VERSION 5.8 ;
BUSBITCHARS "[]" ;
DIVIDERCHAR "/" ;
UNITS
    DATABASE MICRONS 1000 ;
END UNITS

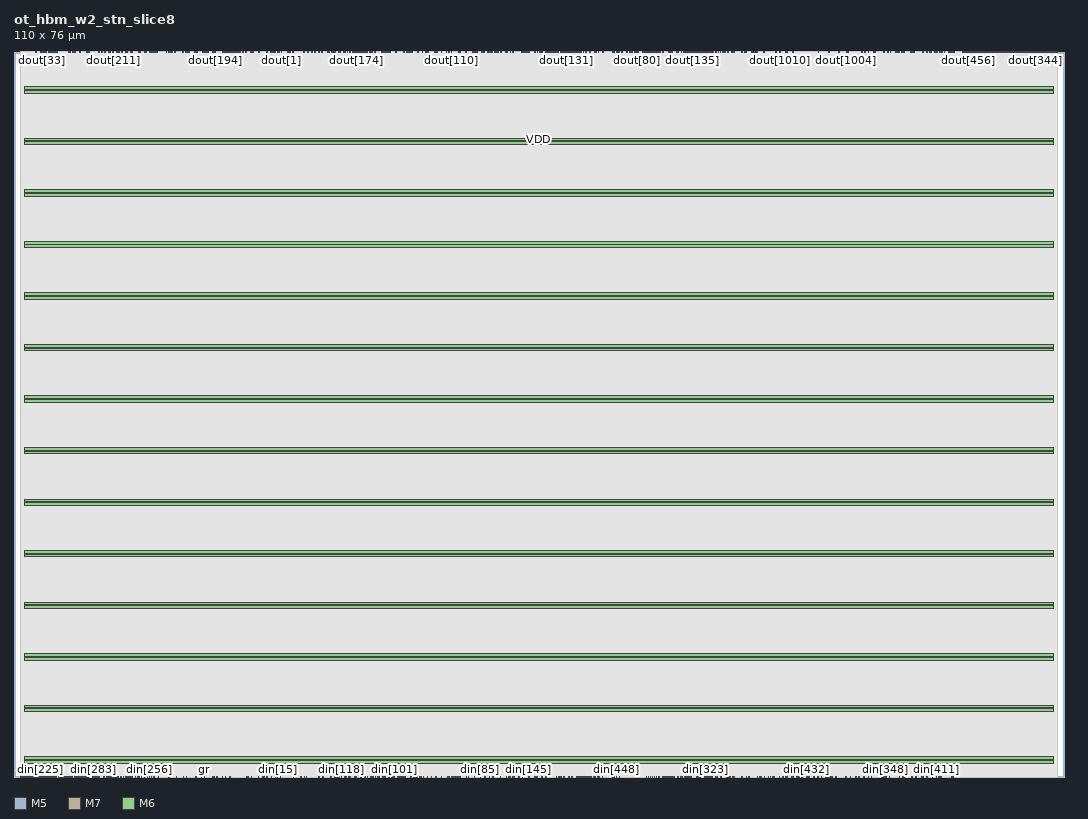
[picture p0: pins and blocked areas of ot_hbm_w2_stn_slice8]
MACRO ot_hbm_w2_stn_slice8
  FOREIGN ot_hbm_w2_stn_slice8 0 0 ;
  CLASS BLOCK ;
  SIZE 110 BY 76 ;
  PIN clk
    DIRECTION INPUT ;
    USE SIGNAL ;
    PORT
      LAYER M5 ;
        RECT  3.36 0 3.384 0.084 ;
    END
  END clk
  PIN din[0]
    DIRECTION INPUT ;
    USE SIGNAL ;
    PORT
      LAYER M5 ;
        RECT  13.68 0 13.704 0.084 ;
    END
  END din[0]
  PIN din[100]
    DIRECTION INPUT ;
    USE SIGNAL ;
    PORT
      LAYER M5 ;
        RECT  41.856 0 41.88 0.084 ;
    END
  END din[100]
  PIN din[101]
    DIRECTION INPUT ;
    USE SIGNAL ;
    PORT
      LAYER M5 ;
        RECT  39.84 0 39.864 0.084 ;
    END
  END din[101]
  PIN din[102]
    DIRECTION INPUT ;
    USE SIGNAL ;
    PORT
      LAYER M5 ;
        RECT  40.224 0 40.248 0.084 ;
    END
  END din[102]
  PIN din[103]
    DIRECTION INPUT ;
    USE SIGNAL ;
    PORT
      LAYER M5 ;
        RECT  38.592 0 38.616 0.084 ;
    END
  END din[103]
  PIN din[104]
    DIRECTION INPUT ;
    USE SIGNAL ;
    PORT
      LAYER M5 ;
        RECT  39.648 0 39.672 0.084 ;
    END
  END din[104]
  PIN din[105]
    DIRECTION INPUT ;
    USE SIGNAL ;
    PORT
      LAYER M5 ;
        RECT  38.832 0 38.856 0.084 ;
    END
  END din[105]
  PIN din[106]
    DIRECTION INPUT ;
    USE SIGNAL ;
    PORT
      LAYER M5 ;
        RECT  38.928 0 38.952 0.084 ;
    END
  END din[106]
  PIN din[107]
    DIRECTION INPUT ;
    USE SIGNAL ;
    PORT
      LAYER M5 ;
        RECT  35.808 0 35.832 0.084 ;
    END
  END din[107]
  PIN din[108]
    DIRECTION INPUT ;
    USE SIGNAL ;
    PORT
      LAYER M5 ;
        RECT  38.304 0 38.328 0.084 ;
    END
  END din[108]
  PIN din[109]
    DIRECTION INPUT ;
    USE SIGNAL ;
    PORT
      LAYER M5 ;
        RECT  35.904 0 35.928 0.084 ;
    END
  END din[109]
  PIN din[10]
    DIRECTION INPUT ;
    USE SIGNAL ;
    PORT
      LAYER M7 ;
        RECT  20.8 0 20.832 0.069 ;
    END
  END din[10]
  PIN din[110]
    DIRECTION INPUT ;
    USE SIGNAL ;
    PORT
      LAYER M5 ;
        RECT  38.88 0 38.904 0.084 ;
    END
  END din[110]
  PIN din[111]
    DIRECTION INPUT ;
    USE SIGNAL ;
    PORT
      LAYER M5 ;
        RECT  35.712 0 35.736 0.084 ;
    END
  END din[111]
  PIN din[112]
    DIRECTION INPUT ;
    USE SIGNAL ;
    PORT
      LAYER M5 ;
        RECT  35.856 0 35.88 0.084 ;
    END
  END din[112]
  PIN din[113]
    DIRECTION INPUT ;
    USE SIGNAL ;
    PORT
      LAYER M5 ;
        RECT  37.632 0 37.656 0.084 ;
    END
  END din[113]
  PIN din[114]
    DIRECTION INPUT ;
    USE SIGNAL ;
    PORT
      LAYER M5 ;
        RECT  35.232 0 35.256 0.084 ;
    END
  END din[114]
  PIN din[115]
    DIRECTION INPUT ;
    USE SIGNAL ;
    PORT
      LAYER M5 ;
        RECT  38.064 0 38.088 0.084 ;
    END
  END din[115]
  PIN din[116]
    DIRECTION INPUT ;
    USE SIGNAL ;
    PORT
      LAYER M7 ;
        RECT  33.536 0 33.568 0.069 ;
    END
  END din[116]
  PIN din[117]
    DIRECTION INPUT ;
    USE SIGNAL ;
    PORT
      LAYER M7 ;
        RECT  33.152 0 33.184 0.069 ;
    END
  END din[117]
  PIN din[118]
    DIRECTION INPUT ;
    USE SIGNAL ;
    PORT
      LAYER M5 ;
        RECT  34.272 0 34.296 0.084 ;
    END
  END din[118]
  PIN din[119]
    DIRECTION INPUT ;
    USE SIGNAL ;
    PORT
      LAYER M7 ;
        RECT  33.216 0 33.248 0.069 ;
    END
  END din[119]
  PIN din[11]
    DIRECTION INPUT ;
    USE SIGNAL ;
    PORT
      LAYER M5 ;
        RECT  17.04 0 17.064 0.084 ;
    END
  END din[11]
  PIN din[120]
    DIRECTION INPUT ;
    USE SIGNAL ;
    PORT
      LAYER M5 ;
        RECT  35.04 0 35.064 0.084 ;
    END
  END din[120]
  PIN din[121]
    DIRECTION INPUT ;
    USE SIGNAL ;
    PORT
      LAYER M5 ;
        RECT  37.008 0 37.032 0.084 ;
    END
  END din[121]
  PIN din[122]
    DIRECTION INPUT ;
    USE SIGNAL ;
    PORT
      LAYER M5 ;
        RECT  36.816 0 36.84 0.084 ;
    END
  END din[122]
  PIN din[123]
    DIRECTION INPUT ;
    USE SIGNAL ;
    PORT
      LAYER M5 ;
        RECT  36.768 0 36.792 0.084 ;
    END
  END din[123]
  PIN din[124]
    DIRECTION INPUT ;
    USE SIGNAL ;
    PORT
      LAYER M7 ;
        RECT  33.6 0 33.632 0.069 ;
    END
  END din[124]
  PIN din[125]
    DIRECTION INPUT ;
    USE SIGNAL ;
    PORT
      LAYER M5 ;
        RECT  34.656 0 34.68 0.084 ;
    END
  END din[125]
  PIN din[126]
    DIRECTION INPUT ;
    USE SIGNAL ;
    PORT
      LAYER M5 ;
        RECT  33.744 0 33.768 0.084 ;
    END
  END din[126]
  PIN din[127]
    DIRECTION INPUT ;
    USE SIGNAL ;
    PORT
      LAYER M5 ;
        RECT  35.088 0 35.112 0.084 ;
    END
  END din[127]
  PIN din[128]
    DIRECTION INPUT ;
    USE SIGNAL ;
    PORT
      LAYER M5 ;
        RECT  39.504 0 39.528 0.084 ;
    END
  END din[128]
  PIN din[129]
    DIRECTION INPUT ;
    USE SIGNAL ;
    PORT
      LAYER M7 ;
        RECT  56.832 0 56.864 0.069 ;
    END
  END din[129]
  PIN din[12]
    DIRECTION INPUT ;
    USE SIGNAL ;
    PORT
      LAYER M5 ;
        RECT  24.528 0 24.552 0.084 ;
    END
  END din[12]
  PIN din[130]
    DIRECTION INPUT ;
    USE SIGNAL ;
    PORT
      LAYER M5 ;
        RECT  41.904 0 41.928 0.084 ;
    END
  END din[130]
  PIN din[131]
    DIRECTION INPUT ;
    USE SIGNAL ;
    PORT
      LAYER M5 ;
        RECT  52.176 0 52.2 0.084 ;
    END
  END din[131]
  PIN din[132]
    DIRECTION INPUT ;
    USE SIGNAL ;
    PORT
      LAYER M5 ;
        RECT  55.296 0 55.32 0.084 ;
    END
  END din[132]
  PIN din[133]
    DIRECTION INPUT ;
    USE SIGNAL ;
    PORT
      LAYER M5 ;
        RECT  54.864 0 54.888 0.084 ;
    END
  END din[133]
  PIN din[134]
    DIRECTION INPUT ;
    USE SIGNAL ;
    PORT
      LAYER M5 ;
        RECT  53.28 0 53.304 0.084 ;
    END
  END din[134]
  PIN din[135]
    DIRECTION INPUT ;
    USE SIGNAL ;
    PORT
      LAYER M7 ;
        RECT  57.216 0 57.248 0.069 ;
    END
  END din[135]
  PIN din[136]
    DIRECTION INPUT ;
    USE SIGNAL ;
    PORT
      LAYER M7 ;
        RECT  57.344 0 57.376 0.069 ;
    END
  END din[136]
  PIN din[137]
    DIRECTION INPUT ;
    USE SIGNAL ;
    PORT
      LAYER M5 ;
        RECT  40.56 0 40.584 0.084 ;
    END
  END din[137]
  PIN din[138]
    DIRECTION INPUT ;
    USE SIGNAL ;
    PORT
      LAYER M7 ;
        RECT  57.6 0 57.632 0.069 ;
    END
  END din[138]
  PIN din[139]
    DIRECTION INPUT ;
    USE SIGNAL ;
    PORT
      LAYER M5 ;
        RECT  42.192 0 42.216 0.084 ;
    END
  END din[139]
  PIN din[13]
    DIRECTION INPUT ;
    USE SIGNAL ;
    PORT
      LAYER M7 ;
        RECT  17.728 0 17.76 0.069 ;
    END
  END din[13]
  PIN din[140]
    DIRECTION INPUT ;
    USE SIGNAL ;
    PORT
      LAYER M5 ;
        RECT  44.208 0 44.232 0.084 ;
    END
  END din[140]
  PIN din[141]
    DIRECTION INPUT ;
    USE SIGNAL ;
    PORT
      LAYER M5 ;
        RECT  51.792 0 51.816 0.084 ;
    END
  END din[141]
  PIN din[142]
    DIRECTION INPUT ;
    USE SIGNAL ;
    PORT
      LAYER M7 ;
        RECT  60.032 0 60.064 0.069 ;
    END
  END din[142]
  PIN din[143]
    DIRECTION INPUT ;
    USE SIGNAL ;
    PORT
      LAYER M7 ;
        RECT  59.968 0 60 0.069 ;
    END
  END din[143]
  PIN din[144]
    DIRECTION INPUT ;
    USE SIGNAL ;
    PORT
      LAYER M5 ;
        RECT  43.728 0 43.752 0.084 ;
    END
  END din[144]
  PIN din[145]
    DIRECTION INPUT ;
    USE SIGNAL ;
    PORT
      LAYER M5 ;
        RECT  53.904 0 53.928 0.084 ;
    END
  END din[145]
  PIN din[146]
    DIRECTION INPUT ;
    USE SIGNAL ;
    PORT
      LAYER M7 ;
        RECT  60.224 0 60.256 0.069 ;
    END
  END din[146]
  PIN din[147]
    DIRECTION INPUT ;
    USE SIGNAL ;
    PORT
      LAYER M7 ;
        RECT  57.536 0 57.568 0.069 ;
    END
  END din[147]
  PIN din[148]
    DIRECTION INPUT ;
    USE SIGNAL ;
    PORT
      LAYER M5 ;
        RECT  55.728 0 55.752 0.084 ;
    END
  END din[148]
  PIN din[149]
    DIRECTION INPUT ;
    USE SIGNAL ;
    PORT
      LAYER M7 ;
        RECT  58.112 0 58.144 0.069 ;
    END
  END din[149]
  PIN din[14]
    DIRECTION INPUT ;
    USE SIGNAL ;
    PORT
      LAYER M5 ;
        RECT  27.36 0 27.384 0.084 ;
    END
  END din[14]
  PIN din[150]
    DIRECTION INPUT ;
    USE SIGNAL ;
    PORT
      LAYER M7 ;
        RECT  49.408 0 49.44 0.069 ;
    END
  END din[150]
  PIN din[151]
    DIRECTION INPUT ;
    USE SIGNAL ;
    PORT
      LAYER M5 ;
        RECT  40.656 0 40.68 0.084 ;
    END
  END din[151]
  PIN din[152]
    DIRECTION INPUT ;
    USE SIGNAL ;
    PORT
      LAYER M7 ;
        RECT  46.72 0 46.752 0.069 ;
    END
  END din[152]
  PIN din[153]
    DIRECTION INPUT ;
    USE SIGNAL ;
    PORT
      LAYER M7 ;
        RECT  49.28 0 49.312 0.069 ;
    END
  END din[153]
  PIN din[154]
    DIRECTION INPUT ;
    USE SIGNAL ;
    PORT
      LAYER M7 ;
        RECT  45.44 0 45.472 0.069 ;
    END
  END din[154]
  PIN din[155]
    DIRECTION INPUT ;
    USE SIGNAL ;
    PORT
      LAYER M7 ;
        RECT  45.568 0 45.6 0.069 ;
    END
  END din[155]
  PIN din[156]
    DIRECTION INPUT ;
    USE SIGNAL ;
    PORT
      LAYER M5 ;
        RECT  42.672 0 42.696 0.084 ;
    END
  END din[156]
  PIN din[157]
    DIRECTION INPUT ;
    USE SIGNAL ;
    PORT
      LAYER M7 ;
        RECT  45.888 0 45.92 0.069 ;
    END
  END din[157]
  PIN din[158]
    DIRECTION INPUT ;
    USE SIGNAL ;
    PORT
      LAYER M5 ;
        RECT  39.216 0 39.24 0.084 ;
    END
  END din[158]
  PIN din[159]
    DIRECTION INPUT ;
    USE SIGNAL ;
    PORT
      LAYER M7 ;
        RECT  46.144 0 46.176 0.069 ;
    END
  END din[159]
  PIN din[15]
    DIRECTION INPUT ;
    USE SIGNAL ;
    PORT
      LAYER M5 ;
        RECT  27.6 0 27.624 0.084 ;
    END
  END din[15]
  PIN din[160]
    DIRECTION INPUT ;
    USE SIGNAL ;
    PORT
      LAYER M7 ;
        RECT  46.656 0 46.688 0.069 ;
    END
  END din[160]
  PIN din[161]
    DIRECTION INPUT ;
    USE SIGNAL ;
    PORT
      LAYER M7 ;
        RECT  45.824 0 45.856 0.069 ;
    END
  END din[161]
  PIN din[162]
    DIRECTION INPUT ;
    USE SIGNAL ;
    PORT
      LAYER M5 ;
        RECT  38.688 0 38.712 0.084 ;
    END
  END din[162]
  PIN din[163]
    DIRECTION INPUT ;
    USE SIGNAL ;
    PORT
      LAYER M5 ;
        RECT  40.848 0 40.872 0.084 ;
    END
  END din[163]
  PIN din[164]
    DIRECTION INPUT ;
    USE SIGNAL ;
    PORT
      LAYER M5 ;
        RECT  42.144 0 42.168 0.084 ;
    END
  END din[164]
  PIN din[165]
    DIRECTION INPUT ;
    USE SIGNAL ;
    PORT
      LAYER M5 ;
        RECT  40.128 0 40.152 0.084 ;
    END
  END din[165]
  PIN din[166]
    DIRECTION INPUT ;
    USE SIGNAL ;
    PORT
      LAYER M7 ;
        RECT  44.8 0 44.832 0.069 ;
    END
  END din[166]
  PIN din[167]
    DIRECTION INPUT ;
    USE SIGNAL ;
    PORT
      LAYER M5 ;
        RECT  44.16 0 44.184 0.084 ;
    END
  END din[167]
  PIN din[168]
    DIRECTION INPUT ;
    USE SIGNAL ;
    PORT
      LAYER M5 ;
        RECT  42.864 0 42.888 0.084 ;
    END
  END din[168]
  PIN din[169]
    DIRECTION INPUT ;
    USE SIGNAL ;
    PORT
      LAYER M5 ;
        RECT  42.528 0 42.552 0.084 ;
    END
  END din[169]
  PIN din[16]
    DIRECTION INPUT ;
    USE SIGNAL ;
    PORT
      LAYER M5 ;
        RECT  24.432 0 24.456 0.084 ;
    END
  END din[16]
  PIN din[170]
    DIRECTION INPUT ;
    USE SIGNAL ;
    PORT
      LAYER M5 ;
        RECT  42.24 0 42.264 0.084 ;
    END
  END din[170]
  PIN din[171]
    DIRECTION INPUT ;
    USE SIGNAL ;
    PORT
      LAYER M5 ;
        RECT  42.048 0 42.072 0.084 ;
    END
  END din[171]
  PIN din[172]
    DIRECTION INPUT ;
    USE SIGNAL ;
    PORT
      LAYER M5 ;
        RECT  41.952 0 41.976 0.084 ;
    END
  END din[172]
  PIN din[173]
    DIRECTION INPUT ;
    USE SIGNAL ;
    PORT
      LAYER M5 ;
        RECT  40.704 0 40.728 0.084 ;
    END
  END din[173]
  PIN din[174]
    DIRECTION INPUT ;
    USE SIGNAL ;
    PORT
      LAYER M5 ;
        RECT  41.04 0 41.064 0.084 ;
    END
  END din[174]
  PIN din[175]
    DIRECTION INPUT ;
    USE SIGNAL ;
    PORT
      LAYER M5 ;
        RECT  40.608 0 40.632 0.084 ;
    END
  END din[175]
  PIN din[176]
    DIRECTION INPUT ;
    USE SIGNAL ;
    PORT
      LAYER M5 ;
        RECT  39.888 0 39.912 0.084 ;
    END
  END din[176]
  PIN din[177]
    DIRECTION INPUT ;
    USE SIGNAL ;
    PORT
      LAYER M5 ;
        RECT  38.784 0 38.808 0.084 ;
    END
  END din[177]
  PIN din[178]
    DIRECTION INPUT ;
    USE SIGNAL ;
    PORT
      LAYER M5 ;
        RECT  38.64 0 38.664 0.084 ;
    END
  END din[178]
  PIN din[179]
    DIRECTION INPUT ;
    USE SIGNAL ;
    PORT
      LAYER M5 ;
        RECT  39.312 0 39.336 0.084 ;
    END
  END din[179]
  PIN din[17]
    DIRECTION INPUT ;
    USE SIGNAL ;
    PORT
      LAYER M5 ;
        RECT  26.064 0 26.088 0.084 ;
    END
  END din[17]
  PIN din[180]
    DIRECTION INPUT ;
    USE SIGNAL ;
    PORT
      LAYER M5 ;
        RECT  36.72 0 36.744 0.084 ;
    END
  END din[180]
  PIN din[181]
    DIRECTION INPUT ;
    USE SIGNAL ;
    PORT
      LAYER M5 ;
        RECT  37.344 0 37.368 0.084 ;
    END
  END din[181]
  PIN din[182]
    DIRECTION INPUT ;
    USE SIGNAL ;
    PORT
      LAYER M5 ;
        RECT  37.392 0 37.416 0.084 ;
    END
  END din[182]
  PIN din[183]
    DIRECTION INPUT ;
    USE SIGNAL ;
    PORT
      LAYER M5 ;
        RECT  39.696 0 39.72 0.084 ;
    END
  END din[183]
  PIN din[184]
    DIRECTION INPUT ;
    USE SIGNAL ;
    PORT
      LAYER M5 ;
        RECT  36.384 0 36.408 0.084 ;
    END
  END din[184]
  PIN din[185]
    DIRECTION INPUT ;
    USE SIGNAL ;
    PORT
      LAYER M5 ;
        RECT  35.136 0 35.16 0.084 ;
    END
  END din[185]
  PIN din[186]
    DIRECTION INPUT ;
    USE SIGNAL ;
    PORT
      LAYER M5 ;
        RECT  34.752 0 34.776 0.084 ;
    END
  END din[186]
  PIN din[187]
    DIRECTION INPUT ;
    USE SIGNAL ;
    PORT
      LAYER M5 ;
        RECT  34.848 0 34.872 0.084 ;
    END
  END din[187]
  PIN din[188]
    DIRECTION INPUT ;
    USE SIGNAL ;
    PORT
      LAYER M5 ;
        RECT  35.664 0 35.688 0.084 ;
    END
  END din[188]
  PIN din[189]
    DIRECTION INPUT ;
    USE SIGNAL ;
    PORT
      LAYER M5 ;
        RECT  35.28 0 35.304 0.084 ;
    END
  END din[189]
  PIN din[18]
    DIRECTION INPUT ;
    USE SIGNAL ;
    PORT
      LAYER M7 ;
        RECT  29.248 0 29.28 0.069 ;
    END
  END din[18]
  PIN din[190]
    DIRECTION INPUT ;
    USE SIGNAL ;
    PORT
      LAYER M5 ;
        RECT  36.672 0 36.696 0.084 ;
    END
  END din[190]
  PIN din[191]
    DIRECTION INPUT ;
    USE SIGNAL ;
    PORT
      LAYER M5 ;
        RECT  36.288 0 36.312 0.084 ;
    END
  END din[191]
  PIN din[192]
    DIRECTION INPUT ;
    USE SIGNAL ;
    PORT
      LAYER M5 ;
        RECT  5.424 0 5.448 0.084 ;
    END
  END din[192]
  PIN din[193]
    DIRECTION INPUT ;
    USE SIGNAL ;
    PORT
      LAYER M5 ;
        RECT  3.312 0 3.336 0.084 ;
    END
  END din[193]
  PIN din[194]
    DIRECTION INPUT ;
    USE SIGNAL ;
    PORT
      LAYER M5 ;
        RECT  3.552 0 3.576 0.084 ;
    END
  END din[194]
  PIN din[195]
    DIRECTION INPUT ;
    USE SIGNAL ;
    PORT
      LAYER M5 ;
        RECT  3.024 0 3.048 0.084 ;
    END
  END din[195]
  PIN din[196]
    DIRECTION INPUT ;
    USE SIGNAL ;
    PORT
      LAYER M5 ;
        RECT  0.72 0 0.744 0.084 ;
    END
  END din[196]
  PIN din[197]
    DIRECTION INPUT ;
    USE SIGNAL ;
    PORT
      LAYER M5 ;
        RECT  0.864 0 0.888 0.084 ;
    END
  END din[197]
  PIN din[198]
    DIRECTION INPUT ;
    USE SIGNAL ;
    PORT
      LAYER M5 ;
        RECT  1.68 0 1.704 0.084 ;
    END
  END din[198]
  PIN din[199]
    DIRECTION INPUT ;
    USE SIGNAL ;
    PORT
      LAYER M5 ;
        RECT  4.8 0 4.824 0.084 ;
    END
  END din[199]
  PIN din[19]
    DIRECTION INPUT ;
    USE SIGNAL ;
    PORT
      LAYER M5 ;
        RECT  26.976 0 27 0.084 ;
    END
  END din[19]
  PIN din[1]
    DIRECTION INPUT ;
    USE SIGNAL ;
    PORT
      LAYER M7 ;
        RECT  18.048 0 18.08 0.069 ;
    END
  END din[1]
  PIN din[200]
    DIRECTION INPUT ;
    USE SIGNAL ;
    PORT
      LAYER M5 ;
        RECT  1.872 0 1.896 0.084 ;
    END
  END din[200]
  PIN din[201]
    DIRECTION INPUT ;
    USE SIGNAL ;
    PORT
      LAYER M5 ;
        RECT  2.304 0 2.328 0.084 ;
    END
  END din[201]
  PIN din[202]
    DIRECTION INPUT ;
    USE SIGNAL ;
    PORT
      LAYER M5 ;
        RECT  0.768 0 0.792 0.084 ;
    END
  END din[202]
  PIN din[203]
    DIRECTION INPUT ;
    USE SIGNAL ;
    PORT
      LAYER M5 ;
        RECT  3.12 0 3.144 0.084 ;
    END
  END din[203]
  PIN din[204]
    DIRECTION INPUT ;
    USE SIGNAL ;
    PORT
      LAYER M5 ;
        RECT  2.832 0 2.856 0.084 ;
    END
  END din[204]
  PIN din[205]
    DIRECTION INPUT ;
    USE SIGNAL ;
    PORT
      LAYER M5 ;
        RECT  0.912 0 0.936 0.084 ;
    END
  END din[205]
  PIN din[206]
    DIRECTION INPUT ;
    USE SIGNAL ;
    PORT
      LAYER M5 ;
        RECT  2.064 0 2.088 0.084 ;
    END
  END din[206]
  PIN din[207]
    DIRECTION INPUT ;
    USE SIGNAL ;
    PORT
      LAYER M5 ;
        RECT  0.816 0 0.84 0.084 ;
    END
  END din[207]
  PIN din[208]
    DIRECTION INPUT ;
    USE SIGNAL ;
    PORT
      LAYER M5 ;
        RECT  1.776 0 1.8 0.084 ;
    END
  END din[208]
  PIN din[209]
    DIRECTION INPUT ;
    USE SIGNAL ;
    PORT
      LAYER M5 ;
        RECT  1.44 0 1.464 0.084 ;
    END
  END din[209]
  PIN din[20]
    DIRECTION INPUT ;
    USE SIGNAL ;
    PORT
      LAYER M5 ;
        RECT  25.632 0 25.656 0.084 ;
    END
  END din[20]
  PIN din[210]
    DIRECTION INPUT ;
    USE SIGNAL ;
    PORT
      LAYER M5 ;
        RECT  2.4 0 2.424 0.084 ;
    END
  END din[210]
  PIN din[211]
    DIRECTION INPUT ;
    USE SIGNAL ;
    PORT
      LAYER M5 ;
        RECT  2.448 0 2.472 0.084 ;
    END
  END din[211]
  PIN din[212]
    DIRECTION INPUT ;
    USE SIGNAL ;
    PORT
      LAYER M5 ;
        RECT  2.256 0 2.28 0.084 ;
    END
  END din[212]
  PIN din[213]
    DIRECTION INPUT ;
    USE SIGNAL ;
    PORT
      LAYER M5 ;
        RECT  1.392 0 1.416 0.084 ;
    END
  END din[213]
  PIN din[214]
    DIRECTION INPUT ;
    USE SIGNAL ;
    PORT
      LAYER M5 ;
        RECT  1.968 0 1.992 0.084 ;
    END
  END din[214]
  PIN din[215]
    DIRECTION INPUT ;
    USE SIGNAL ;
    PORT
      LAYER M5 ;
        RECT  0.96 0 0.984 0.084 ;
    END
  END din[215]
  PIN din[216]
    DIRECTION INPUT ;
    USE SIGNAL ;
    PORT
      LAYER M5 ;
        RECT  3.264 0 3.288 0.084 ;
    END
  END din[216]
  PIN din[217]
    DIRECTION INPUT ;
    USE SIGNAL ;
    PORT
      LAYER M5 ;
        RECT  1.536 0 1.56 0.084 ;
    END
  END din[217]
  PIN din[218]
    DIRECTION INPUT ;
    USE SIGNAL ;
    PORT
      LAYER M5 ;
        RECT  1.344 0 1.368 0.084 ;
    END
  END din[218]
  PIN din[219]
    DIRECTION INPUT ;
    USE SIGNAL ;
    PORT
      LAYER M5 ;
        RECT  1.632 0 1.656 0.084 ;
    END
  END din[219]
  PIN din[21]
    DIRECTION INPUT ;
    USE SIGNAL ;
    PORT
      LAYER M5 ;
        RECT  24.864 0 24.888 0.084 ;
    END
  END din[21]
  PIN din[220]
    DIRECTION INPUT ;
    USE SIGNAL ;
    PORT
      LAYER M5 ;
        RECT  1.296 0 1.32 0.084 ;
    END
  END din[220]
  PIN din[221]
    DIRECTION INPUT ;
    USE SIGNAL ;
    PORT
      LAYER M5 ;
        RECT  1.584 0 1.608 0.084 ;
    END
  END din[221]
  PIN din[222]
    DIRECTION INPUT ;
    USE SIGNAL ;
    PORT
      LAYER M5 ;
        RECT  1.248 0 1.272 0.084 ;
    END
  END din[222]
  PIN din[223]
    DIRECTION INPUT ;
    USE SIGNAL ;
    PORT
      LAYER M5 ;
        RECT  1.008 0 1.032 0.084 ;
    END
  END din[223]
  PIN din[224]
    DIRECTION INPUT ;
    USE SIGNAL ;
    PORT
      LAYER M5 ;
        RECT  1.824 0 1.848 0.084 ;
    END
  END din[224]
  PIN din[225]
    DIRECTION INPUT ;
    USE SIGNAL ;
    PORT
      LAYER M5 ;
        RECT  2.736 0 2.76 0.084 ;
    END
  END din[225]
  PIN din[226]
    DIRECTION INPUT ;
    USE SIGNAL ;
    PORT
      LAYER M5 ;
        RECT  1.2 0 1.224 0.084 ;
    END
  END din[226]
  PIN din[227]
    DIRECTION INPUT ;
    USE SIGNAL ;
    PORT
      LAYER M5 ;
        RECT  6.096 0 6.12 0.084 ;
    END
  END din[227]
  PIN din[228]
    DIRECTION INPUT ;
    USE SIGNAL ;
    PORT
      LAYER M5 ;
        RECT  6.144 0 6.168 0.084 ;
    END
  END din[228]
  PIN din[229]
    DIRECTION INPUT ;
    USE SIGNAL ;
    PORT
      LAYER M5 ;
        RECT  2.688 0 2.712 0.084 ;
    END
  END din[229]
  PIN din[22]
    DIRECTION INPUT ;
    USE SIGNAL ;
    PORT
      LAYER M5 ;
        RECT  26.256 0 26.28 0.084 ;
    END
  END din[22]
  PIN din[230]
    DIRECTION INPUT ;
    USE SIGNAL ;
    PORT
      LAYER M5 ;
        RECT  4.128 0 4.152 0.084 ;
    END
  END din[230]
  PIN din[231]
    DIRECTION INPUT ;
    USE SIGNAL ;
    PORT
      LAYER M5 ;
        RECT  4.992 0 5.016 0.084 ;
    END
  END din[231]
  PIN din[232]
    DIRECTION INPUT ;
    USE SIGNAL ;
    PORT
      LAYER M5 ;
        RECT  5.76 0 5.784 0.084 ;
    END
  END din[232]
  PIN din[233]
    DIRECTION INPUT ;
    USE SIGNAL ;
    PORT
      LAYER M5 ;
        RECT  2.544 0 2.568 0.084 ;
    END
  END din[233]
  PIN din[234]
    DIRECTION INPUT ;
    USE SIGNAL ;
    PORT
      LAYER M5 ;
        RECT  3.504 0 3.528 0.084 ;
    END
  END din[234]
  PIN din[235]
    DIRECTION INPUT ;
    USE SIGNAL ;
    PORT
      LAYER M5 ;
        RECT  4.752 0 4.776 0.084 ;
    END
  END din[235]
  PIN din[236]
    DIRECTION INPUT ;
    USE SIGNAL ;
    PORT
      LAYER M5 ;
        RECT  5.232 0 5.256 0.084 ;
    END
  END din[236]
  PIN din[237]
    DIRECTION INPUT ;
    USE SIGNAL ;
    PORT
      LAYER M5 ;
        RECT  2.208 0 2.232 0.084 ;
    END
  END din[237]
  PIN din[238]
    DIRECTION INPUT ;
    USE SIGNAL ;
    PORT
      LAYER M5 ;
        RECT  1.152 0 1.176 0.084 ;
    END
  END din[238]
  PIN din[239]
    DIRECTION INPUT ;
    USE SIGNAL ;
    PORT
      LAYER M5 ;
        RECT  2.112 0 2.136 0.084 ;
    END
  END din[239]
  PIN din[23]
    DIRECTION INPUT ;
    USE SIGNAL ;
    PORT
      LAYER M5 ;
        RECT  26.496 0 26.52 0.084 ;
    END
  END din[23]
  PIN din[240]
    DIRECTION INPUT ;
    USE SIGNAL ;
    PORT
      LAYER M5 ;
        RECT  2.496 0 2.52 0.084 ;
    END
  END din[240]
  PIN din[241]
    DIRECTION INPUT ;
    USE SIGNAL ;
    PORT
      LAYER M5 ;
        RECT  3.072 0 3.096 0.084 ;
    END
  END din[241]
  PIN din[242]
    DIRECTION INPUT ;
    USE SIGNAL ;
    PORT
      LAYER M5 ;
        RECT  1.104 0 1.128 0.084 ;
    END
  END din[242]
  PIN din[243]
    DIRECTION INPUT ;
    USE SIGNAL ;
    PORT
      LAYER M5 ;
        RECT  3.84 0 3.864 0.084 ;
    END
  END din[243]
  PIN din[244]
    DIRECTION INPUT ;
    USE SIGNAL ;
    PORT
      LAYER M5 ;
        RECT  3.216 0 3.24 0.084 ;
    END
  END din[244]
  PIN din[245]
    DIRECTION INPUT ;
    USE SIGNAL ;
    PORT
      LAYER M5 ;
        RECT  3.168 0 3.192 0.084 ;
    END
  END din[245]
  PIN din[246]
    DIRECTION INPUT ;
    USE SIGNAL ;
    PORT
      LAYER M5 ;
        RECT  3.696 0 3.72 0.084 ;
    END
  END din[246]
  PIN din[247]
    DIRECTION INPUT ;
    USE SIGNAL ;
    PORT
      LAYER M5 ;
        RECT  3.888 0 3.912 0.084 ;
    END
  END din[247]
  PIN din[248]
    DIRECTION INPUT ;
    USE SIGNAL ;
    PORT
      LAYER M5 ;
        RECT  3.456 0 3.48 0.084 ;
    END
  END din[248]
  PIN din[249]
    DIRECTION INPUT ;
    USE SIGNAL ;
    PORT
      LAYER M5 ;
        RECT  2.88 0 2.904 0.084 ;
    END
  END din[249]
  PIN din[24]
    DIRECTION INPUT ;
    USE SIGNAL ;
    PORT
      LAYER M5 ;
        RECT  24.384 0 24.408 0.084 ;
    END
  END din[24]
  PIN din[250]
    DIRECTION INPUT ;
    USE SIGNAL ;
    PORT
      LAYER M5 ;
        RECT  2.784 0 2.808 0.084 ;
    END
  END din[250]
  PIN din[251]
    DIRECTION INPUT ;
    USE SIGNAL ;
    PORT
      LAYER M5 ;
        RECT  1.728 0 1.752 0.084 ;
    END
  END din[251]
  PIN din[252]
    DIRECTION INPUT ;
    USE SIGNAL ;
    PORT
      LAYER M5 ;
        RECT  3.408 0 3.432 0.084 ;
    END
  END din[252]
  PIN din[253]
    DIRECTION INPUT ;
    USE SIGNAL ;
    PORT
      LAYER M5 ;
        RECT  2.64 0 2.664 0.084 ;
    END
  END din[253]
  PIN din[254]
    DIRECTION INPUT ;
    USE SIGNAL ;
    PORT
      LAYER M5 ;
        RECT  2.352 0 2.376 0.084 ;
    END
  END din[254]
  PIN din[255]
    DIRECTION INPUT ;
    USE SIGNAL ;
    PORT
      LAYER M5 ;
        RECT  1.056 0 1.08 0.084 ;
    END
  END din[255]
  PIN din[256]
    DIRECTION INPUT ;
    USE SIGNAL ;
    PORT
      LAYER M5 ;
        RECT  14.208 0 14.232 0.084 ;
    END
  END din[256]
  PIN din[257]
    DIRECTION INPUT ;
    USE SIGNAL ;
    PORT
      LAYER M5 ;
        RECT  12.72 0 12.744 0.084 ;
    END
  END din[257]
  PIN din[258]
    DIRECTION INPUT ;
    USE SIGNAL ;
    PORT
      LAYER M5 ;
        RECT  11.952 0 11.976 0.084 ;
    END
  END din[258]
  PIN din[259]
    DIRECTION INPUT ;
    USE SIGNAL ;
    PORT
      LAYER M5 ;
        RECT  14.64 0 14.664 0.084 ;
    END
  END din[259]
  PIN din[25]
    DIRECTION INPUT ;
    USE SIGNAL ;
    PORT
      LAYER M5 ;
        RECT  24.336 0 24.36 0.084 ;
    END
  END din[25]
  PIN din[260]
    DIRECTION INPUT ;
    USE SIGNAL ;
    PORT
      LAYER M7 ;
        RECT  6.592 0 6.624 0.069 ;
    END
  END din[260]
  PIN din[261]
    DIRECTION INPUT ;
    USE SIGNAL ;
    PORT
      LAYER M5 ;
        RECT  13.056 0 13.08 0.084 ;
    END
  END din[261]
  PIN din[262]
    DIRECTION INPUT ;
    USE SIGNAL ;
    PORT
      LAYER M5 ;
        RECT  13.968 0 13.992 0.084 ;
    END
  END din[262]
  PIN din[263]
    DIRECTION INPUT ;
    USE SIGNAL ;
    PORT
      LAYER M5 ;
        RECT  12.048 0 12.072 0.084 ;
    END
  END din[263]
  PIN din[264]
    DIRECTION INPUT ;
    USE SIGNAL ;
    PORT
      LAYER M5 ;
        RECT  11.808 0 11.832 0.084 ;
    END
  END din[264]
  PIN din[265]
    DIRECTION INPUT ;
    USE SIGNAL ;
    PORT
      LAYER M7 ;
        RECT  10.88 0 10.912 0.069 ;
    END
  END din[265]
  PIN din[266]
    DIRECTION INPUT ;
    USE SIGNAL ;
    PORT
      LAYER M5 ;
        RECT  14.736 0 14.76 0.084 ;
    END
  END din[266]
  PIN din[267]
    DIRECTION INPUT ;
    USE SIGNAL ;
    PORT
      LAYER M5 ;
        RECT  12.912 0 12.936 0.084 ;
    END
  END din[267]
  PIN din[268]
    DIRECTION INPUT ;
    USE SIGNAL ;
    PORT
      LAYER M7 ;
        RECT  9.664 0 9.696 0.069 ;
    END
  END din[268]
  PIN din[269]
    DIRECTION INPUT ;
    USE SIGNAL ;
    PORT
      LAYER M5 ;
        RECT  14.688 0 14.712 0.084 ;
    END
  END din[269]
  PIN din[26]
    DIRECTION INPUT ;
    USE SIGNAL ;
    PORT
      LAYER M7 ;
        RECT  22.144 0 22.176 0.069 ;
    END
  END din[26]
  PIN din[270]
    DIRECTION INPUT ;
    USE SIGNAL ;
    PORT
      LAYER M5 ;
        RECT  12.336 0 12.36 0.084 ;
    END
  END din[270]
  PIN din[271]
    DIRECTION INPUT ;
    USE SIGNAL ;
    PORT
      LAYER M5 ;
        RECT  12.384 0 12.408 0.084 ;
    END
  END din[271]
  PIN din[272]
    DIRECTION INPUT ;
    USE SIGNAL ;
    PORT
      LAYER M7 ;
        RECT  10.816 0 10.848 0.069 ;
    END
  END din[272]
  PIN din[273]
    DIRECTION INPUT ;
    USE SIGNAL ;
    PORT
      LAYER M5 ;
        RECT  11.664 0 11.688 0.084 ;
    END
  END din[273]
  PIN din[274]
    DIRECTION INPUT ;
    USE SIGNAL ;
    PORT
      LAYER M5 ;
        RECT  11.712 0 11.736 0.084 ;
    END
  END din[274]
  PIN din[275]
    DIRECTION INPUT ;
    USE SIGNAL ;
    PORT
      LAYER M5 ;
        RECT  13.104 0 13.128 0.084 ;
    END
  END din[275]
  PIN din[276]
    DIRECTION INPUT ;
    USE SIGNAL ;
    PORT
      LAYER M7 ;
        RECT  9.728 0 9.76 0.069 ;
    END
  END din[276]
  PIN din[277]
    DIRECTION INPUT ;
    USE SIGNAL ;
    PORT
      LAYER M5 ;
        RECT  13.344 0 13.368 0.084 ;
    END
  END din[277]
  PIN din[278]
    DIRECTION INPUT ;
    USE SIGNAL ;
    PORT
      LAYER M7 ;
        RECT  10.752 0 10.784 0.069 ;
    END
  END din[278]
  PIN din[279]
    DIRECTION INPUT ;
    USE SIGNAL ;
    PORT
      LAYER M7 ;
        RECT  10.496 0 10.528 0.069 ;
    END
  END din[279]
  PIN din[27]
    DIRECTION INPUT ;
    USE SIGNAL ;
    PORT
      LAYER M7 ;
        RECT  20.864 0 20.896 0.069 ;
    END
  END din[27]
  PIN din[280]
    DIRECTION INPUT ;
    USE SIGNAL ;
    PORT
      LAYER M7 ;
        RECT  9.92 0 9.952 0.069 ;
    END
  END din[280]
  PIN din[281]
    DIRECTION INPUT ;
    USE SIGNAL ;
    PORT
      LAYER M7 ;
        RECT  10.432 0 10.464 0.069 ;
    END
  END din[281]
  PIN din[282]
    DIRECTION INPUT ;
    USE SIGNAL ;
    PORT
      LAYER M7 ;
        RECT  7.808 0 7.84 0.069 ;
    END
  END din[282]
  PIN din[283]
    DIRECTION INPUT ;
    USE SIGNAL ;
    PORT
      LAYER M7 ;
        RECT  8.32 0 8.352 0.069 ;
    END
  END din[283]
  PIN din[284]
    DIRECTION INPUT ;
    USE SIGNAL ;
    PORT
      LAYER M7 ;
        RECT  8.64 0 8.672 0.069 ;
    END
  END din[284]
  PIN din[285]
    DIRECTION INPUT ;
    USE SIGNAL ;
    PORT
      LAYER M7 ;
        RECT  6.848 0 6.88 0.069 ;
    END
  END din[285]
  PIN din[286]
    DIRECTION INPUT ;
    USE SIGNAL ;
    PORT
      LAYER M7 ;
        RECT  7.04 0 7.072 0.069 ;
    END
  END din[286]
  PIN din[287]
    DIRECTION INPUT ;
    USE SIGNAL ;
    PORT
      LAYER M5 ;
        RECT  6.384 0 6.408 0.084 ;
    END
  END din[287]
  PIN din[288]
    DIRECTION INPUT ;
    USE SIGNAL ;
    PORT
      LAYER M7 ;
        RECT  7.232 0 7.264 0.069 ;
    END
  END din[288]
  PIN din[289]
    DIRECTION INPUT ;
    USE SIGNAL ;
    PORT
      LAYER M5 ;
        RECT  6 0 6.024 0.084 ;
    END
  END din[289]
  PIN din[28]
    DIRECTION INPUT ;
    USE SIGNAL ;
    PORT
      LAYER M7 ;
        RECT  19.136 0 19.168 0.069 ;
    END
  END din[28]
  PIN din[290]
    DIRECTION INPUT ;
    USE SIGNAL ;
    PORT
      LAYER M5 ;
        RECT  5.376 0 5.4 0.084 ;
    END
  END din[290]
  PIN din[291]
    DIRECTION INPUT ;
    USE SIGNAL ;
    PORT
      LAYER M5 ;
        RECT  5.712 0 5.736 0.084 ;
    END
  END din[291]
  PIN din[292]
    DIRECTION INPUT ;
    USE SIGNAL ;
    PORT
      LAYER M5 ;
        RECT  5.808 0 5.832 0.084 ;
    END
  END din[292]
  PIN din[293]
    DIRECTION INPUT ;
    USE SIGNAL ;
    PORT
      LAYER M5 ;
        RECT  5.088 0 5.112 0.084 ;
    END
  END din[293]
  PIN din[294]
    DIRECTION INPUT ;
    USE SIGNAL ;
    PORT
      LAYER M7 ;
        RECT  7.424 0 7.456 0.069 ;
    END
  END din[294]
  PIN din[295]
    DIRECTION INPUT ;
    USE SIGNAL ;
    PORT
      LAYER M7 ;
        RECT  7.616 0 7.648 0.069 ;
    END
  END din[295]
  PIN din[296]
    DIRECTION INPUT ;
    USE SIGNAL ;
    PORT
      LAYER M7 ;
        RECT  8.192 0 8.224 0.069 ;
    END
  END din[296]
  PIN din[297]
    DIRECTION INPUT ;
    USE SIGNAL ;
    PORT
      LAYER M7 ;
        RECT  6.72 0 6.752 0.069 ;
    END
  END din[297]
  PIN din[298]
    DIRECTION INPUT ;
    USE SIGNAL ;
    PORT
      LAYER M5 ;
        RECT  5.472 0 5.496 0.084 ;
    END
  END din[298]
  PIN din[299]
    DIRECTION INPUT ;
    USE SIGNAL ;
    PORT
      LAYER M7 ;
        RECT  8.512 0 8.544 0.069 ;
    END
  END din[299]
  PIN din[29]
    DIRECTION INPUT ;
    USE SIGNAL ;
    PORT
      LAYER M5 ;
        RECT  22.608 0 22.632 0.084 ;
    END
  END din[29]
  PIN din[2]
    DIRECTION INPUT ;
    USE SIGNAL ;
    PORT
      LAYER M5 ;
        RECT  11.232 0 11.256 0.084 ;
    END
  END din[2]
  PIN din[300]
    DIRECTION INPUT ;
    USE SIGNAL ;
    PORT
      LAYER M7 ;
        RECT  8.448 0 8.48 0.069 ;
    END
  END din[300]
  PIN din[301]
    DIRECTION INPUT ;
    USE SIGNAL ;
    PORT
      LAYER M5 ;
        RECT  6.048 0 6.072 0.084 ;
    END
  END din[301]
  PIN din[302]
    DIRECTION INPUT ;
    USE SIGNAL ;
    PORT
      LAYER M7 ;
        RECT  7.68 0 7.712 0.069 ;
    END
  END din[302]
  PIN din[303]
    DIRECTION INPUT ;
    USE SIGNAL ;
    PORT
      LAYER M7 ;
        RECT  7.744 0 7.776 0.069 ;
    END
  END din[303]
  PIN din[304]
    DIRECTION INPUT ;
    USE SIGNAL ;
    PORT
      LAYER M7 ;
        RECT  8.256 0 8.288 0.069 ;
    END
  END din[304]
  PIN din[305]
    DIRECTION INPUT ;
    USE SIGNAL ;
    PORT
      LAYER M7 ;
        RECT  7.104 0 7.136 0.069 ;
    END
  END din[305]
  PIN din[306]
    DIRECTION INPUT ;
    USE SIGNAL ;
    PORT
      LAYER M7 ;
        RECT  7.552 0 7.584 0.069 ;
    END
  END din[306]
  PIN din[307]
    DIRECTION INPUT ;
    USE SIGNAL ;
    PORT
      LAYER M7 ;
        RECT  10.112 0 10.144 0.069 ;
    END
  END din[307]
  PIN din[308]
    DIRECTION INPUT ;
    USE SIGNAL ;
    PORT
      LAYER M7 ;
        RECT  8.96 0 8.992 0.069 ;
    END
  END din[308]
  PIN din[309]
    DIRECTION INPUT ;
    USE SIGNAL ;
    PORT
      LAYER M5 ;
        RECT  11.472 0 11.496 0.084 ;
    END
  END din[309]
  PIN din[30]
    DIRECTION INPUT ;
    USE SIGNAL ;
    PORT
      LAYER M7 ;
        RECT  20.992 0 21.024 0.069 ;
    END
  END din[30]
  PIN din[310]
    DIRECTION INPUT ;
    USE SIGNAL ;
    PORT
      LAYER M7 ;
        RECT  10.368 0 10.4 0.069 ;
    END
  END din[310]
  PIN din[311]
    DIRECTION INPUT ;
    USE SIGNAL ;
    PORT
      LAYER M7 ;
        RECT  10.944 0 10.976 0.069 ;
    END
  END din[311]
  PIN din[312]
    DIRECTION INPUT ;
    USE SIGNAL ;
    PORT
      LAYER M7 ;
        RECT  10.048 0 10.08 0.069 ;
    END
  END din[312]
  PIN din[313]
    DIRECTION INPUT ;
    USE SIGNAL ;
    PORT
      LAYER M5 ;
        RECT  11.856 0 11.88 0.084 ;
    END
  END din[313]
  PIN din[314]
    DIRECTION INPUT ;
    USE SIGNAL ;
    PORT
      LAYER M5 ;
        RECT  11.28 0 11.304 0.084 ;
    END
  END din[314]
  PIN din[315]
    DIRECTION INPUT ;
    USE SIGNAL ;
    PORT
      LAYER M7 ;
        RECT  11.2 0 11.232 0.069 ;
    END
  END din[315]
  PIN din[316]
    DIRECTION INPUT ;
    USE SIGNAL ;
    PORT
      LAYER M5 ;
        RECT  14.16 0 14.184 0.084 ;
    END
  END din[316]
  PIN din[317]
    DIRECTION INPUT ;
    USE SIGNAL ;
    PORT
      LAYER M5 ;
        RECT  13.152 0 13.176 0.084 ;
    END
  END din[317]
  PIN din[318]
    DIRECTION INPUT ;
    USE SIGNAL ;
    PORT
      LAYER M7 ;
        RECT  10.24 0 10.272 0.069 ;
    END
  END din[318]
  PIN din[319]
    DIRECTION INPUT ;
    USE SIGNAL ;
    PORT
      LAYER M5 ;
        RECT  14.4 0 14.424 0.084 ;
    END
  END din[319]
  PIN din[31]
    DIRECTION INPUT ;
    USE SIGNAL ;
    PORT
      LAYER M7 ;
        RECT  21.248 0 21.28 0.069 ;
    END
  END din[31]
  PIN din[320]
    DIRECTION INPUT ;
    USE SIGNAL ;
    PORT
      LAYER M5 ;
        RECT  79.248 0 79.272 0.084 ;
    END
  END din[320]
  PIN din[321]
    DIRECTION INPUT ;
    USE SIGNAL ;
    PORT
      LAYER M7 ;
        RECT  70.976 0 71.008 0.069 ;
    END
  END din[321]
  PIN din[322]
    DIRECTION INPUT ;
    USE SIGNAL ;
    PORT
      LAYER M7 ;
        RECT  70.848 0 70.88 0.069 ;
    END
  END din[322]
  PIN din[323]
    DIRECTION INPUT ;
    USE SIGNAL ;
    PORT
      LAYER M5 ;
        RECT  72.48 0 72.504 0.084 ;
    END
  END din[323]
  PIN din[324]
    DIRECTION INPUT ;
    USE SIGNAL ;
    PORT
      LAYER M7 ;
        RECT  70.272 0 70.304 0.069 ;
    END
  END din[324]
  PIN din[325]
    DIRECTION INPUT ;
    USE SIGNAL ;
    PORT
      LAYER M7 ;
        RECT  69.056 0 69.088 0.069 ;
    END
  END din[325]
  PIN din[326]
    DIRECTION INPUT ;
    USE SIGNAL ;
    PORT
      LAYER M7 ;
        RECT  68.224 0 68.256 0.069 ;
    END
  END din[326]
  PIN din[327]
    DIRECTION INPUT ;
    USE SIGNAL ;
    PORT
      LAYER M7 ;
        RECT  70.912 0 70.944 0.069 ;
    END
  END din[327]
  PIN din[328]
    DIRECTION INPUT ;
    USE SIGNAL ;
    PORT
      LAYER M7 ;
        RECT  70.784 0 70.816 0.069 ;
    END
  END din[328]
  PIN din[329]
    DIRECTION INPUT ;
    USE SIGNAL ;
    PORT
      LAYER M7 ;
        RECT  67.904 0 67.936 0.069 ;
    END
  END din[329]
  PIN din[32]
    DIRECTION INPUT ;
    USE SIGNAL ;
    PORT
      LAYER M7 ;
        RECT  21.824 0 21.856 0.069 ;
    END
  END din[32]
  PIN din[330]
    DIRECTION INPUT ;
    USE SIGNAL ;
    PORT
      LAYER M7 ;
        RECT  68.16 0 68.192 0.069 ;
    END
  END din[330]
  PIN din[331]
    DIRECTION INPUT ;
    USE SIGNAL ;
    PORT
      LAYER M7 ;
        RECT  71.936 0 71.968 0.069 ;
    END
  END din[331]
  PIN din[332]
    DIRECTION INPUT ;
    USE SIGNAL ;
    PORT
      LAYER M7 ;
        RECT  68.928 0 68.96 0.069 ;
    END
  END din[332]
  PIN din[333]
    DIRECTION INPUT ;
    USE SIGNAL ;
    PORT
      LAYER M5 ;
        RECT  72.576 0 72.6 0.084 ;
    END
  END din[333]
  PIN din[334]
    DIRECTION INPUT ;
    USE SIGNAL ;
    PORT
      LAYER M5 ;
        RECT  72.72 0 72.744 0.084 ;
    END
  END din[334]
  PIN din[335]
    DIRECTION INPUT ;
    USE SIGNAL ;
    PORT
      LAYER M5 ;
        RECT  72.432 0 72.456 0.084 ;
    END
  END din[335]
  PIN din[336]
    DIRECTION INPUT ;
    USE SIGNAL ;
    PORT
      LAYER M7 ;
        RECT  68.544 0 68.576 0.069 ;
    END
  END din[336]
  PIN din[337]
    DIRECTION INPUT ;
    USE SIGNAL ;
    PORT
      LAYER M5 ;
        RECT  72.336 0 72.36 0.084 ;
    END
  END din[337]
  PIN din[338]
    DIRECTION INPUT ;
    USE SIGNAL ;
    PORT
      LAYER M5 ;
        RECT  74.016 0 74.04 0.084 ;
    END
  END din[338]
  PIN din[339]
    DIRECTION INPUT ;
    USE SIGNAL ;
    PORT
      LAYER M7 ;
        RECT  71.616 0 71.648 0.069 ;
    END
  END din[339]
  PIN din[33]
    DIRECTION INPUT ;
    USE SIGNAL ;
    PORT
      LAYER M5 ;
        RECT  11.76 0 11.784 0.084 ;
    END
  END din[33]
  PIN din[340]
    DIRECTION INPUT ;
    USE SIGNAL ;
    PORT
      LAYER M7 ;
        RECT  68.672 0 68.704 0.069 ;
    END
  END din[340]
  PIN din[341]
    DIRECTION INPUT ;
    USE SIGNAL ;
    PORT
      LAYER M7 ;
        RECT  69.824 0 69.856 0.069 ;
    END
  END din[341]
  PIN din[342]
    DIRECTION INPUT ;
    USE SIGNAL ;
    PORT
      LAYER M5 ;
        RECT  74.112 0 74.136 0.084 ;
    END
  END din[342]
  PIN din[343]
    DIRECTION INPUT ;
    USE SIGNAL ;
    PORT
      LAYER M5 ;
        RECT  72.672 0 72.696 0.084 ;
    END
  END din[343]
  PIN din[344]
    DIRECTION INPUT ;
    USE SIGNAL ;
    PORT
      LAYER M7 ;
        RECT  70.72 0 70.752 0.069 ;
    END
  END din[344]
  PIN din[345]
    DIRECTION INPUT ;
    USE SIGNAL ;
    PORT
      LAYER M5 ;
        RECT  72.96 0 72.984 0.084 ;
    END
  END din[345]
  PIN din[346]
    DIRECTION INPUT ;
    USE SIGNAL ;
    PORT
      LAYER M5 ;
        RECT  89.088 0 89.112 0.084 ;
    END
  END din[346]
  PIN din[347]
    DIRECTION INPUT ;
    USE SIGNAL ;
    PORT
      LAYER M5 ;
        RECT  90.912 0 90.936 0.084 ;
    END
  END din[347]
  PIN din[348]
    DIRECTION INPUT ;
    USE SIGNAL ;
    PORT
      LAYER M5 ;
        RECT  91.296 0 91.32 0.084 ;
    END
  END din[348]
  PIN din[349]
    DIRECTION INPUT ;
    USE SIGNAL ;
    PORT
      LAYER M5 ;
        RECT  91.104 0 91.128 0.084 ;
    END
  END din[349]
  PIN din[34]
    DIRECTION INPUT ;
    USE SIGNAL ;
    PORT
      LAYER M5 ;
        RECT  12.24 0 12.264 0.084 ;
    END
  END din[34]
  PIN din[350]
    DIRECTION INPUT ;
    USE SIGNAL ;
    PORT
      LAYER M5 ;
        RECT  88.272 0 88.296 0.084 ;
    END
  END din[350]
  PIN din[351]
    DIRECTION INPUT ;
    USE SIGNAL ;
    PORT
      LAYER M5 ;
        RECT  90.96 0 90.984 0.084 ;
    END
  END din[351]
  PIN din[352]
    DIRECTION INPUT ;
    USE SIGNAL ;
    PORT
      LAYER M5 ;
        RECT  89.808 0 89.832 0.084 ;
    END
  END din[352]
  PIN din[353]
    DIRECTION INPUT ;
    USE SIGNAL ;
    PORT
      LAYER M5 ;
        RECT  89.04 0 89.064 0.084 ;
    END
  END din[353]
  PIN din[354]
    DIRECTION INPUT ;
    USE SIGNAL ;
    PORT
      LAYER M5 ;
        RECT  79.632 0 79.656 0.084 ;
    END
  END din[354]
  PIN din[355]
    DIRECTION INPUT ;
    USE SIGNAL ;
    PORT
      LAYER M5 ;
        RECT  78.624 0 78.648 0.084 ;
    END
  END din[355]
  PIN din[356]
    DIRECTION INPUT ;
    USE SIGNAL ;
    PORT
      LAYER M7 ;
        RECT  86.08 0 86.112 0.069 ;
    END
  END din[356]
  PIN din[357]
    DIRECTION INPUT ;
    USE SIGNAL ;
    PORT
      LAYER M7 ;
        RECT  85.696 0 85.728 0.069 ;
    END
  END din[357]
  PIN din[358]
    DIRECTION INPUT ;
    USE SIGNAL ;
    PORT
      LAYER M7 ;
        RECT  85.184 0 85.216 0.069 ;
    END
  END din[358]
  PIN din[359]
    DIRECTION INPUT ;
    USE SIGNAL ;
    PORT
      LAYER M5 ;
        RECT  79.44 0 79.464 0.084 ;
    END
  END din[359]
  PIN din[35]
    DIRECTION INPUT ;
    USE SIGNAL ;
    PORT
      LAYER M7 ;
        RECT  7.168 0 7.2 0.069 ;
    END
  END din[35]
  PIN din[360]
    DIRECTION INPUT ;
    USE SIGNAL ;
    PORT
      LAYER M7 ;
        RECT  83.712 0 83.744 0.069 ;
    END
  END din[360]
  PIN din[361]
    DIRECTION INPUT ;
    USE SIGNAL ;
    PORT
      LAYER M7 ;
        RECT  85.76 0 85.792 0.069 ;
    END
  END din[361]
  PIN din[362]
    DIRECTION INPUT ;
    USE SIGNAL ;
    PORT
      LAYER M5 ;
        RECT  80.784 0 80.808 0.084 ;
    END
  END din[362]
  PIN din[363]
    DIRECTION INPUT ;
    USE SIGNAL ;
    PORT
      LAYER M5 ;
        RECT  78.24 0 78.264 0.084 ;
    END
  END din[363]
  PIN din[364]
    DIRECTION INPUT ;
    USE SIGNAL ;
    PORT
      LAYER M7 ;
        RECT  85.312 0 85.344 0.069 ;
    END
  END din[364]
  PIN din[365]
    DIRECTION INPUT ;
    USE SIGNAL ;
    PORT
      LAYER M7 ;
        RECT  83.328 0 83.36 0.069 ;
    END
  END din[365]
  PIN din[366]
    DIRECTION INPUT ;
    USE SIGNAL ;
    PORT
      LAYER M5 ;
        RECT  82.032 0 82.056 0.084 ;
    END
  END din[366]
  PIN din[367]
    DIRECTION INPUT ;
    USE SIGNAL ;
    PORT
      LAYER M5 ;
        RECT  83.088 0 83.112 0.084 ;
    END
  END din[367]
  PIN din[368]
    DIRECTION INPUT ;
    USE SIGNAL ;
    PORT
      LAYER M7 ;
        RECT  83.2 0 83.232 0.069 ;
    END
  END din[368]
  PIN din[369]
    DIRECTION INPUT ;
    USE SIGNAL ;
    PORT
      LAYER M5 ;
        RECT  80.544 0 80.568 0.084 ;
    END
  END din[369]
  PIN din[36]
    DIRECTION INPUT ;
    USE SIGNAL ;
    PORT
      LAYER M7 ;
        RECT  9.472 0 9.504 0.069 ;
    END
  END din[36]
  PIN din[370]
    DIRECTION INPUT ;
    USE SIGNAL ;
    PORT
      LAYER M5 ;
        RECT  80.208 0 80.232 0.084 ;
    END
  END din[370]
  PIN din[371]
    DIRECTION INPUT ;
    USE SIGNAL ;
    PORT
      LAYER M5 ;
        RECT  82.992 0 83.016 0.084 ;
    END
  END din[371]
  PIN din[372]
    DIRECTION INPUT ;
    USE SIGNAL ;
    PORT
      LAYER M5 ;
        RECT  82.608 0 82.632 0.084 ;
    END
  END din[372]
  PIN din[373]
    DIRECTION INPUT ;
    USE SIGNAL ;
    PORT
      LAYER M5 ;
        RECT  80.16 0 80.184 0.084 ;
    END
  END din[373]
  PIN din[374]
    DIRECTION INPUT ;
    USE SIGNAL ;
    PORT
      LAYER M5 ;
        RECT  82.272 0 82.296 0.084 ;
    END
  END din[374]
  PIN din[375]
    DIRECTION INPUT ;
    USE SIGNAL ;
    PORT
      LAYER M7 ;
        RECT  69.568 0 69.6 0.069 ;
    END
  END din[375]
  PIN din[376]
    DIRECTION INPUT ;
    USE SIGNAL ;
    PORT
      LAYER M5 ;
        RECT  81.984 0 82.008 0.084 ;
    END
  END din[376]
  PIN din[377]
    DIRECTION INPUT ;
    USE SIGNAL ;
    PORT
      LAYER M7 ;
        RECT  68.288 0 68.32 0.069 ;
    END
  END din[377]
  PIN din[378]
    DIRECTION INPUT ;
    USE SIGNAL ;
    PORT
      LAYER M7 ;
        RECT  69.12 0 69.152 0.069 ;
    END
  END din[378]
  PIN din[379]
    DIRECTION INPUT ;
    USE SIGNAL ;
    PORT
      LAYER M7 ;
        RECT  68.416 0 68.448 0.069 ;
    END
  END din[379]
  PIN din[37]
    DIRECTION INPUT ;
    USE SIGNAL ;
    PORT
      LAYER M7 ;
        RECT  8.384 0 8.416 0.069 ;
    END
  END din[37]
  PIN din[380]
    DIRECTION INPUT ;
    USE SIGNAL ;
    PORT
      LAYER M7 ;
        RECT  69.952 0 69.984 0.069 ;
    END
  END din[380]
  PIN din[381]
    DIRECTION INPUT ;
    USE SIGNAL ;
    PORT
      LAYER M7 ;
        RECT  70.464 0 70.496 0.069 ;
    END
  END din[381]
  PIN din[382]
    DIRECTION INPUT ;
    USE SIGNAL ;
    PORT
      LAYER M7 ;
        RECT  69.504 0 69.536 0.069 ;
    END
  END din[382]
  PIN din[383]
    DIRECTION INPUT ;
    USE SIGNAL ;
    PORT
      LAYER M7 ;
        RECT  69.888 0 69.92 0.069 ;
    END
  END din[383]
  PIN din[384]
    DIRECTION INPUT ;
    USE SIGNAL ;
    PORT
      LAYER M7 ;
        RECT  84.544 0 84.576 0.069 ;
    END
  END din[384]
  PIN din[385]
    DIRECTION INPUT ;
    USE SIGNAL ;
    PORT
      LAYER M5 ;
        RECT  75.408 0 75.432 0.084 ;
    END
  END din[385]
  PIN din[386]
    DIRECTION INPUT ;
    USE SIGNAL ;
    PORT
      LAYER M5 ;
        RECT  76.752 0 76.776 0.084 ;
    END
  END din[386]
  PIN din[387]
    DIRECTION INPUT ;
    USE SIGNAL ;
    PORT
      LAYER M5 ;
        RECT  76.944 0 76.968 0.084 ;
    END
  END din[387]
  PIN din[388]
    DIRECTION INPUT ;
    USE SIGNAL ;
    PORT
      LAYER M5 ;
        RECT  80.976 0 81 0.084 ;
    END
  END din[388]
  PIN din[389]
    DIRECTION INPUT ;
    USE SIGNAL ;
    PORT
      LAYER M5 ;
        RECT  81.6 0 81.624 0.084 ;
    END
  END din[389]
  PIN din[38]
    DIRECTION INPUT ;
    USE SIGNAL ;
    PORT
      LAYER M7 ;
        RECT  10.56 0 10.592 0.069 ;
    END
  END din[38]
  PIN din[390]
    DIRECTION INPUT ;
    USE SIGNAL ;
    PORT
      LAYER M5 ;
        RECT  81.456 0 81.48 0.084 ;
    END
  END din[390]
  PIN din[391]
    DIRECTION INPUT ;
    USE SIGNAL ;
    PORT
      LAYER M5 ;
        RECT  78.576 0 78.6 0.084 ;
    END
  END din[391]
  PIN din[392]
    DIRECTION INPUT ;
    USE SIGNAL ;
    PORT
      LAYER M5 ;
        RECT  78.144 0 78.168 0.084 ;
    END
  END din[392]
  PIN din[393]
    DIRECTION INPUT ;
    USE SIGNAL ;
    PORT
      LAYER M5 ;
        RECT  76.992 0 77.016 0.084 ;
    END
  END din[393]
  PIN din[394]
    DIRECTION INPUT ;
    USE SIGNAL ;
    PORT
      LAYER M5 ;
        RECT  77.856 0 77.88 0.084 ;
    END
  END din[394]
  PIN din[395]
    DIRECTION INPUT ;
    USE SIGNAL ;
    PORT
      LAYER M5 ;
        RECT  79.536 0 79.56 0.084 ;
    END
  END din[395]
  PIN din[396]
    DIRECTION INPUT ;
    USE SIGNAL ;
    PORT
      LAYER M5 ;
        RECT  82.464 0 82.488 0.084 ;
    END
  END din[396]
  PIN din[397]
    DIRECTION INPUT ;
    USE SIGNAL ;
    PORT
      LAYER M5 ;
        RECT  82.224 0 82.248 0.084 ;
    END
  END din[397]
  PIN din[398]
    DIRECTION INPUT ;
    USE SIGNAL ;
    PORT
      LAYER M7 ;
        RECT  83.264 0 83.296 0.069 ;
    END
  END din[398]
  PIN din[399]
    DIRECTION INPUT ;
    USE SIGNAL ;
    PORT
      LAYER M7 ;
        RECT  83.84 0 83.872 0.069 ;
    END
  END din[399]
  PIN din[39]
    DIRECTION INPUT ;
    USE SIGNAL ;
    PORT
      LAYER M7 ;
        RECT  7.36 0 7.392 0.069 ;
    END
  END din[39]
  PIN din[3]
    DIRECTION INPUT ;
    USE SIGNAL ;
    PORT
      LAYER M5 ;
        RECT  4.272 0 4.296 0.084 ;
    END
  END din[3]
  PIN din[400]
    DIRECTION INPUT ;
    USE SIGNAL ;
    PORT
      LAYER M7 ;
        RECT  85.632 0 85.664 0.069 ;
    END
  END din[400]
  PIN din[401]
    DIRECTION INPUT ;
    USE SIGNAL ;
    PORT
      LAYER M7 ;
        RECT  84.224 0 84.256 0.069 ;
    END
  END din[401]
  PIN din[402]
    DIRECTION INPUT ;
    USE SIGNAL ;
    PORT
      LAYER M5 ;
        RECT  91.392 0 91.416 0.084 ;
    END
  END din[402]
  PIN din[403]
    DIRECTION INPUT ;
    USE SIGNAL ;
    PORT
      LAYER M5 ;
        RECT  93.312 0 93.336 0.084 ;
    END
  END din[403]
  PIN din[404]
    DIRECTION INPUT ;
    USE SIGNAL ;
    PORT
      LAYER M7 ;
        RECT  87.104 0 87.136 0.069 ;
    END
  END din[404]
  PIN din[405]
    DIRECTION INPUT ;
    USE SIGNAL ;
    PORT
      LAYER M5 ;
        RECT  91.152 0 91.176 0.084 ;
    END
  END din[405]
  PIN din[406]
    DIRECTION INPUT ;
    USE SIGNAL ;
    PORT
      LAYER M5 ;
        RECT  88.512 0 88.536 0.084 ;
    END
  END din[406]
  PIN din[407]
    DIRECTION INPUT ;
    USE SIGNAL ;
    PORT
      LAYER M5 ;
        RECT  88.128 0 88.152 0.084 ;
    END
  END din[407]
  PIN din[408]
    DIRECTION INPUT ;
    USE SIGNAL ;
    PORT
      LAYER M7 ;
        RECT  87.232 0 87.264 0.069 ;
    END
  END din[408]
  PIN din[409]
    DIRECTION INPUT ;
    USE SIGNAL ;
    PORT
      LAYER M5 ;
        RECT  89.472 0 89.496 0.084 ;
    END
  END din[409]
  PIN din[40]
    DIRECTION INPUT ;
    USE SIGNAL ;
    PORT
      LAYER M7 ;
        RECT  8.768 0 8.8 0.069 ;
    END
  END din[40]
  PIN din[410]
    DIRECTION INPUT ;
    USE SIGNAL ;
    PORT
      LAYER M5 ;
        RECT  79.008 0 79.032 0.084 ;
    END
  END din[410]
  PIN din[411]
    DIRECTION INPUT ;
    USE SIGNAL ;
    PORT
      LAYER M7 ;
        RECT  96.64 0 96.672 0.069 ;
    END
  END din[411]
  PIN din[412]
    DIRECTION INPUT ;
    USE SIGNAL ;
    PORT
      LAYER M5 ;
        RECT  79.584 0 79.608 0.084 ;
    END
  END din[412]
  PIN din[413]
    DIRECTION INPUT ;
    USE SIGNAL ;
    PORT
      LAYER M7 ;
        RECT  98.176 0 98.208 0.069 ;
    END
  END din[413]
  PIN din[414]
    DIRECTION INPUT ;
    USE SIGNAL ;
    PORT
      LAYER M7 ;
        RECT  98.304 0 98.336 0.069 ;
    END
  END din[414]
  PIN din[415]
    DIRECTION INPUT ;
    USE SIGNAL ;
    PORT
      LAYER M5 ;
        RECT  94.032 0 94.056 0.084 ;
    END
  END din[415]
  PIN din[416]
    DIRECTION INPUT ;
    USE SIGNAL ;
    PORT
      LAYER M5 ;
        RECT  93.12 0 93.144 0.084 ;
    END
  END din[416]
  PIN din[417]
    DIRECTION INPUT ;
    USE SIGNAL ;
    PORT
      LAYER M5 ;
        RECT  92.736 0 92.76 0.084 ;
    END
  END din[417]
  PIN din[418]
    DIRECTION INPUT ;
    USE SIGNAL ;
    PORT
      LAYER M5 ;
        RECT  94.08 0 94.104 0.084 ;
    END
  END din[418]
  PIN din[419]
    DIRECTION INPUT ;
    USE SIGNAL ;
    PORT
      LAYER M7 ;
        RECT  98.24 0 98.272 0.069 ;
    END
  END din[419]
  PIN din[41]
    DIRECTION INPUT ;
    USE SIGNAL ;
    PORT
      LAYER M7 ;
        RECT  8.576 0 8.608 0.069 ;
    END
  END din[41]
  PIN din[420]
    DIRECTION INPUT ;
    USE SIGNAL ;
    PORT
      LAYER M7 ;
        RECT  97.088 0 97.12 0.069 ;
    END
  END din[420]
  PIN din[421]
    DIRECTION INPUT ;
    USE SIGNAL ;
    PORT
      LAYER M7 ;
        RECT  98.368 0 98.4 0.069 ;
    END
  END din[421]
  PIN din[422]
    DIRECTION INPUT ;
    USE SIGNAL ;
    PORT
      LAYER M7 ;
        RECT  96.896 0 96.928 0.069 ;
    END
  END din[422]
  PIN din[423]
    DIRECTION INPUT ;
    USE SIGNAL ;
    PORT
      LAYER M7 ;
        RECT  96.192 0 96.224 0.069 ;
    END
  END din[423]
  PIN din[424]
    DIRECTION INPUT ;
    USE SIGNAL ;
    PORT
      LAYER M7 ;
        RECT  95.232 0 95.264 0.069 ;
    END
  END din[424]
  PIN din[425]
    DIRECTION INPUT ;
    USE SIGNAL ;
    PORT
      LAYER M7 ;
        RECT  95.104 0 95.136 0.069 ;
    END
  END din[425]
  PIN din[426]
    DIRECTION INPUT ;
    USE SIGNAL ;
    PORT
      LAYER M7 ;
        RECT  95.168 0 95.2 0.069 ;
    END
  END din[426]
  PIN din[427]
    DIRECTION INPUT ;
    USE SIGNAL ;
    PORT
      LAYER M7 ;
        RECT  95.616 0 95.648 0.069 ;
    END
  END din[427]
  PIN din[428]
    DIRECTION INPUT ;
    USE SIGNAL ;
    PORT
      LAYER M7 ;
        RECT  94.464 0 94.496 0.069 ;
    END
  END din[428]
  PIN din[429]
    DIRECTION INPUT ;
    USE SIGNAL ;
    PORT
      LAYER M5 ;
        RECT  91.68 0 91.704 0.084 ;
    END
  END din[429]
  PIN din[42]
    DIRECTION INPUT ;
    USE SIGNAL ;
    PORT
      LAYER M7 ;
        RECT  7.488 0 7.52 0.069 ;
    END
  END din[42]
  PIN din[430]
    DIRECTION INPUT ;
    USE SIGNAL ;
    PORT
      LAYER M5 ;
        RECT  88.176 0 88.2 0.084 ;
    END
  END din[430]
  PIN din[431]
    DIRECTION INPUT ;
    USE SIGNAL ;
    PORT
      LAYER M7 ;
        RECT  87.168 0 87.2 0.069 ;
    END
  END din[431]
  PIN din[432]
    DIRECTION INPUT ;
    USE SIGNAL ;
    PORT
      LAYER M5 ;
        RECT  83.04 0 83.064 0.084 ;
    END
  END din[432]
  PIN din[433]
    DIRECTION INPUT ;
    USE SIGNAL ;
    PORT
      LAYER M5 ;
        RECT  88.992 0 89.016 0.084 ;
    END
  END din[433]
  PIN din[434]
    DIRECTION INPUT ;
    USE SIGNAL ;
    PORT
      LAYER M7 ;
        RECT  87.616 0 87.648 0.069 ;
    END
  END din[434]
  PIN din[435]
    DIRECTION INPUT ;
    USE SIGNAL ;
    PORT
      LAYER M7 ;
        RECT  86.144 0 86.176 0.069 ;
    END
  END din[435]
  PIN din[436]
    DIRECTION INPUT ;
    USE SIGNAL ;
    PORT
      LAYER M7 ;
        RECT  85.504 0 85.536 0.069 ;
    END
  END din[436]
  PIN din[437]
    DIRECTION INPUT ;
    USE SIGNAL ;
    PORT
      LAYER M7 ;
        RECT  85.44 0 85.472 0.069 ;
    END
  END din[437]
  PIN din[438]
    DIRECTION INPUT ;
    USE SIGNAL ;
    PORT
      LAYER M5 ;
        RECT  75.264 0 75.288 0.084 ;
    END
  END din[438]
  PIN din[439]
    DIRECTION INPUT ;
    USE SIGNAL ;
    PORT
      LAYER M7 ;
        RECT  85.056 0 85.088 0.069 ;
    END
  END din[439]
  PIN din[43]
    DIRECTION INPUT ;
    USE SIGNAL ;
    PORT
      LAYER M7 ;
        RECT  6.976 0 7.008 0.069 ;
    END
  END din[43]
  PIN din[440]
    DIRECTION INPUT ;
    USE SIGNAL ;
    PORT
      LAYER M5 ;
        RECT  76.176 0 76.2 0.084 ;
    END
  END din[440]
  PIN din[441]
    DIRECTION INPUT ;
    USE SIGNAL ;
    PORT
      LAYER M5 ;
        RECT  75.072 0 75.096 0.084 ;
    END
  END din[441]
  PIN din[442]
    DIRECTION INPUT ;
    USE SIGNAL ;
    PORT
      LAYER M5 ;
        RECT  74.688 0 74.712 0.084 ;
    END
  END din[442]
  PIN din[443]
    DIRECTION INPUT ;
    USE SIGNAL ;
    PORT
      LAYER M5 ;
        RECT  74.832 0 74.856 0.084 ;
    END
  END din[443]
  PIN din[444]
    DIRECTION INPUT ;
    USE SIGNAL ;
    PORT
      LAYER M5 ;
        RECT  73.008 0 73.032 0.084 ;
    END
  END din[444]
  PIN din[445]
    DIRECTION INPUT ;
    USE SIGNAL ;
    PORT
      LAYER M5 ;
        RECT  73.488 0 73.512 0.084 ;
    END
  END din[445]
  PIN din[446]
    DIRECTION INPUT ;
    USE SIGNAL ;
    PORT
      LAYER M5 ;
        RECT  72.912 0 72.936 0.084 ;
    END
  END din[446]
  PIN din[447]
    DIRECTION INPUT ;
    USE SIGNAL ;
    PORT
      LAYER M5 ;
        RECT  73.104 0 73.128 0.084 ;
    END
  END din[447]
  PIN din[448]
    DIRECTION INPUT ;
    USE SIGNAL ;
    PORT
      LAYER M5 ;
        RECT  63.072 0 63.096 0.084 ;
    END
  END din[448]
  PIN din[449]
    DIRECTION INPUT ;
    USE SIGNAL ;
    PORT
      LAYER M7 ;
        RECT  67.584 0 67.616 0.069 ;
    END
  END din[449]
  PIN din[44]
    DIRECTION INPUT ;
    USE SIGNAL ;
    PORT
      LAYER M7 ;
        RECT  6.912 0 6.944 0.069 ;
    END
  END din[44]
  PIN din[450]
    DIRECTION INPUT ;
    USE SIGNAL ;
    PORT
      LAYER M7 ;
        RECT  67.328 0 67.36 0.069 ;
    END
  END din[450]
  PIN din[451]
    DIRECTION INPUT ;
    USE SIGNAL ;
    PORT
      LAYER M7 ;
        RECT  68.608 0 68.64 0.069 ;
    END
  END din[451]
  PIN din[452]
    DIRECTION INPUT ;
    USE SIGNAL ;
    PORT
      LAYER M5 ;
        RECT  66.288 0 66.312 0.084 ;
    END
  END din[452]
  PIN din[453]
    DIRECTION INPUT ;
    USE SIGNAL ;
    PORT
      LAYER M5 ;
        RECT  66.672 0 66.696 0.084 ;
    END
  END din[453]
  PIN din[454]
    DIRECTION INPUT ;
    USE SIGNAL ;
    PORT
      LAYER M5 ;
        RECT  66.864 0 66.888 0.084 ;
    END
  END din[454]
  PIN din[455]
    DIRECTION INPUT ;
    USE SIGNAL ;
    PORT
      LAYER M7 ;
        RECT  70.592 0 70.624 0.069 ;
    END
  END din[455]
  PIN din[456]
    DIRECTION INPUT ;
    USE SIGNAL ;
    PORT
      LAYER M5 ;
        RECT  61.68 0 61.704 0.084 ;
    END
  END din[456]
  PIN din[457]
    DIRECTION INPUT ;
    USE SIGNAL ;
    PORT
      LAYER M7 ;
        RECT  68.8 0 68.832 0.069 ;
    END
  END din[457]
  PIN din[458]
    DIRECTION INPUT ;
    USE SIGNAL ;
    PORT
      LAYER M7 ;
        RECT  70.528 0 70.56 0.069 ;
    END
  END din[458]
  PIN din[459]
    DIRECTION INPUT ;
    USE SIGNAL ;
    PORT
      LAYER M5 ;
        RECT  66.48 0 66.504 0.084 ;
    END
  END din[459]
  PIN din[45]
    DIRECTION INPUT ;
    USE SIGNAL ;
    PORT
      LAYER M7 ;
        RECT  9.408 0 9.44 0.069 ;
    END
  END din[45]
  PIN din[460]
    DIRECTION INPUT ;
    USE SIGNAL ;
    PORT
      LAYER M5 ;
        RECT  66.912 0 66.936 0.084 ;
    END
  END din[460]
  PIN din[461]
    DIRECTION INPUT ;
    USE SIGNAL ;
    PORT
      LAYER M5 ;
        RECT  67.056 0 67.08 0.084 ;
    END
  END din[461]
  PIN din[462]
    DIRECTION INPUT ;
    USE SIGNAL ;
    PORT
      LAYER M5 ;
        RECT  76.32 0 76.344 0.084 ;
    END
  END din[462]
  PIN din[463]
    DIRECTION INPUT ;
    USE SIGNAL ;
    PORT
      LAYER M7 ;
        RECT  70.4 0 70.432 0.069 ;
    END
  END din[463]
  PIN din[464]
    DIRECTION INPUT ;
    USE SIGNAL ;
    PORT
      LAYER M5 ;
        RECT  73.632 0 73.656 0.084 ;
    END
  END din[464]
  PIN din[465]
    DIRECTION INPUT ;
    USE SIGNAL ;
    PORT
      LAYER M5 ;
        RECT  74.976 0 75 0.084 ;
    END
  END din[465]
  PIN din[466]
    DIRECTION INPUT ;
    USE SIGNAL ;
    PORT
      LAYER M5 ;
        RECT  74.736 0 74.76 0.084 ;
    END
  END din[466]
  PIN din[467]
    DIRECTION INPUT ;
    USE SIGNAL ;
    PORT
      LAYER M7 ;
        RECT  68.992 0 69.024 0.069 ;
    END
  END din[467]
  PIN din[468]
    DIRECTION INPUT ;
    USE SIGNAL ;
    PORT
      LAYER M7 ;
        RECT  67.52 0 67.552 0.069 ;
    END
  END din[468]
  PIN din[469]
    DIRECTION INPUT ;
    USE SIGNAL ;
    PORT
      LAYER M5 ;
        RECT  74.928 0 74.952 0.084 ;
    END
  END din[469]
  PIN din[46]
    DIRECTION INPUT ;
    USE SIGNAL ;
    PORT
      LAYER M7 ;
        RECT  6.528 0 6.56 0.069 ;
    END
  END din[46]
  PIN din[470]
    DIRECTION INPUT ;
    USE SIGNAL ;
    PORT
      LAYER M7 ;
        RECT  71.744 0 71.776 0.069 ;
    END
  END din[470]
  PIN din[471]
    DIRECTION INPUT ;
    USE SIGNAL ;
    PORT
      LAYER M7 ;
        RECT  70.336 0 70.368 0.069 ;
    END
  END din[471]
  PIN din[472]
    DIRECTION INPUT ;
    USE SIGNAL ;
    PORT
      LAYER M7 ;
        RECT  71.488 0 71.52 0.069 ;
    END
  END din[472]
  PIN din[473]
    DIRECTION INPUT ;
    USE SIGNAL ;
    PORT
      LAYER M7 ;
        RECT  70.656 0 70.688 0.069 ;
    END
  END din[473]
  PIN din[474]
    DIRECTION INPUT ;
    USE SIGNAL ;
    PORT
      LAYER M7 ;
        RECT  68.736 0 68.768 0.069 ;
    END
  END din[474]
  PIN din[475]
    DIRECTION INPUT ;
    USE SIGNAL ;
    PORT
      LAYER M7 ;
        RECT  68.864 0 68.896 0.069 ;
    END
  END din[475]
  PIN din[476]
    DIRECTION INPUT ;
    USE SIGNAL ;
    PORT
      LAYER M7 ;
        RECT  71.552 0 71.584 0.069 ;
    END
  END din[476]
  PIN din[477]
    DIRECTION INPUT ;
    USE SIGNAL ;
    PORT
      LAYER M5 ;
        RECT  61.2 0 61.224 0.084 ;
    END
  END din[477]
  PIN din[478]
    DIRECTION INPUT ;
    USE SIGNAL ;
    PORT
      LAYER M7 ;
        RECT  59.328 0 59.36 0.069 ;
    END
  END din[478]
  PIN din[479]
    DIRECTION INPUT ;
    USE SIGNAL ;
    PORT
      LAYER M7 ;
        RECT  60.288 0 60.32 0.069 ;
    END
  END din[479]
  PIN din[47]
    DIRECTION INPUT ;
    USE SIGNAL ;
    PORT
      LAYER M5 ;
        RECT  5.616 0 5.64 0.084 ;
    END
  END din[47]
  PIN din[480]
    DIRECTION INPUT ;
    USE SIGNAL ;
    PORT
      LAYER M5 ;
        RECT  62.784 0 62.808 0.084 ;
    END
  END din[480]
  PIN din[481]
    DIRECTION INPUT ;
    USE SIGNAL ;
    PORT
      LAYER M7 ;
        RECT  60.096 0 60.128 0.069 ;
    END
  END din[481]
  PIN din[482]
    DIRECTION INPUT ;
    USE SIGNAL ;
    PORT
      LAYER M7 ;
        RECT  58.88 0 58.912 0.069 ;
    END
  END din[482]
  PIN din[483]
    DIRECTION INPUT ;
    USE SIGNAL ;
    PORT
      LAYER M7 ;
        RECT  59.712 0 59.744 0.069 ;
    END
  END din[483]
  PIN din[484]
    DIRECTION INPUT ;
    USE SIGNAL ;
    PORT
      LAYER M7 ;
        RECT  59.52 0 59.552 0.069 ;
    END
  END din[484]
  PIN din[485]
    DIRECTION INPUT ;
    USE SIGNAL ;
    PORT
      LAYER M7 ;
        RECT  59.84 0 59.872 0.069 ;
    END
  END din[485]
  PIN din[486]
    DIRECTION INPUT ;
    USE SIGNAL ;
    PORT
      LAYER M7 ;
        RECT  59.2 0 59.232 0.069 ;
    END
  END din[486]
  PIN din[487]
    DIRECTION INPUT ;
    USE SIGNAL ;
    PORT
      LAYER M7 ;
        RECT  59.648 0 59.68 0.069 ;
    END
  END din[487]
  PIN din[488]
    DIRECTION INPUT ;
    USE SIGNAL ;
    PORT
      LAYER M7 ;
        RECT  58.944 0 58.976 0.069 ;
    END
  END din[488]
  PIN din[489]
    DIRECTION INPUT ;
    USE SIGNAL ;
    PORT
      LAYER M7 ;
        RECT  60.48 0 60.512 0.069 ;
    END
  END din[489]
  PIN din[48]
    DIRECTION INPUT ;
    USE SIGNAL ;
    PORT
      LAYER M5 ;
        RECT  3.984 0 4.008 0.084 ;
    END
  END din[48]
  PIN din[490]
    DIRECTION INPUT ;
    USE SIGNAL ;
    PORT
      LAYER M7 ;
        RECT  59.072 0 59.104 0.069 ;
    END
  END din[490]
  PIN din[491]
    DIRECTION INPUT ;
    USE SIGNAL ;
    PORT
      LAYER M7 ;
        RECT  59.584 0 59.616 0.069 ;
    END
  END din[491]
  PIN din[492]
    DIRECTION INPUT ;
    USE SIGNAL ;
    PORT
      LAYER M7 ;
        RECT  59.008 0 59.04 0.069 ;
    END
  END din[492]
  PIN din[493]
    DIRECTION INPUT ;
    USE SIGNAL ;
    PORT
      LAYER M7 ;
        RECT  60.352 0 60.384 0.069 ;
    END
  END din[493]
  PIN din[494]
    DIRECTION INPUT ;
    USE SIGNAL ;
    PORT
      LAYER M7 ;
        RECT  59.136 0 59.168 0.069 ;
    END
  END din[494]
  PIN din[495]
    DIRECTION INPUT ;
    USE SIGNAL ;
    PORT
      LAYER M7 ;
        RECT  59.776 0 59.808 0.069 ;
    END
  END din[495]
  PIN din[496]
    DIRECTION INPUT ;
    USE SIGNAL ;
    PORT
      LAYER M7 ;
        RECT  60.416 0 60.448 0.069 ;
    END
  END din[496]
  PIN din[497]
    DIRECTION INPUT ;
    USE SIGNAL ;
    PORT
      LAYER M7 ;
        RECT  59.264 0 59.296 0.069 ;
    END
  END din[497]
  PIN din[498]
    DIRECTION INPUT ;
    USE SIGNAL ;
    PORT
      LAYER M7 ;
        RECT  59.392 0 59.424 0.069 ;
    END
  END din[498]
  PIN din[499]
    DIRECTION INPUT ;
    USE SIGNAL ;
    PORT
      LAYER M7 ;
        RECT  59.456 0 59.488 0.069 ;
    END
  END din[499]
  PIN din[49]
    DIRECTION INPUT ;
    USE SIGNAL ;
    PORT
      LAYER M5 ;
        RECT  2.16 0 2.184 0.084 ;
    END
  END din[49]
  PIN din[4]
    DIRECTION INPUT ;
    USE SIGNAL ;
    PORT
      LAYER M5 ;
        RECT  16.272 0 16.296 0.084 ;
    END
  END din[4]
  PIN din[500]
    DIRECTION INPUT ;
    USE SIGNAL ;
    PORT
      LAYER M7 ;
        RECT  59.904 0 59.936 0.069 ;
    END
  END din[500]
  PIN din[501]
    DIRECTION INPUT ;
    USE SIGNAL ;
    PORT
      LAYER M7 ;
        RECT  60.736 0 60.768 0.069 ;
    END
  END din[501]
  PIN din[502]
    DIRECTION INPUT ;
    USE SIGNAL ;
    PORT
      LAYER M7 ;
        RECT  60.16 0 60.192 0.069 ;
    END
  END din[502]
  PIN din[503]
    DIRECTION INPUT ;
    USE SIGNAL ;
    PORT
      LAYER M7 ;
        RECT  60.8 0 60.832 0.069 ;
    END
  END din[503]
  PIN din[504]
    DIRECTION INPUT ;
    USE SIGNAL ;
    PORT
      LAYER M5 ;
        RECT  60.912 0 60.936 0.084 ;
    END
  END din[504]
  PIN din[505]
    DIRECTION INPUT ;
    USE SIGNAL ;
    PORT
      LAYER M5 ;
        RECT  63.456 0 63.48 0.084 ;
    END
  END din[505]
  PIN din[506]
    DIRECTION INPUT ;
    USE SIGNAL ;
    PORT
      LAYER M5 ;
        RECT  62.928 0 62.952 0.084 ;
    END
  END din[506]
  PIN din[507]
    DIRECTION INPUT ;
    USE SIGNAL ;
    PORT
      LAYER M5 ;
        RECT  62.88 0 62.904 0.084 ;
    END
  END din[507]
  PIN din[508]
    DIRECTION INPUT ;
    USE SIGNAL ;
    PORT
      LAYER M5 ;
        RECT  61.104 0 61.128 0.084 ;
    END
  END din[508]
  PIN din[509]
    DIRECTION INPUT ;
    USE SIGNAL ;
    PORT
      LAYER M5 ;
        RECT  61.344 0 61.368 0.084 ;
    END
  END din[509]
  PIN din[50]
    DIRECTION INPUT ;
    USE SIGNAL ;
    PORT
      LAYER M5 ;
        RECT  2.928 0 2.952 0.084 ;
    END
  END din[50]
  PIN din[510]
    DIRECTION INPUT ;
    USE SIGNAL ;
    PORT
      LAYER M5 ;
        RECT  61.248 0 61.272 0.084 ;
    END
  END din[510]
  PIN din[511]
    DIRECTION INPUT ;
    USE SIGNAL ;
    PORT
      LAYER M5 ;
        RECT  61.152 0 61.176 0.084 ;
    END
  END din[511]
  PIN din[51]
    DIRECTION INPUT ;
    USE SIGNAL ;
    PORT
      LAYER M5 ;
        RECT  4.704 0 4.728 0.084 ;
    END
  END din[51]
  PIN din[52]
    DIRECTION INPUT ;
    USE SIGNAL ;
    PORT
      LAYER M5 ;
        RECT  4.224 0 4.248 0.084 ;
    END
  END din[52]
  PIN din[53]
    DIRECTION INPUT ;
    USE SIGNAL ;
    PORT
      LAYER M5 ;
        RECT  1.488 0 1.512 0.084 ;
    END
  END din[53]
  PIN din[54]
    DIRECTION INPUT ;
    USE SIGNAL ;
    PORT
      LAYER M5 ;
        RECT  2.976 0 3 0.084 ;
    END
  END din[54]
  PIN din[55]
    DIRECTION INPUT ;
    USE SIGNAL ;
    PORT
      LAYER M5 ;
        RECT  3.648 0 3.672 0.084 ;
    END
  END din[55]
  PIN din[56]
    DIRECTION INPUT ;
    USE SIGNAL ;
    PORT
      LAYER M5 ;
        RECT  3.6 0 3.624 0.084 ;
    END
  END din[56]
  PIN din[57]
    DIRECTION INPUT ;
    USE SIGNAL ;
    PORT
      LAYER M5 ;
        RECT  1.92 0 1.944 0.084 ;
    END
  END din[57]
  PIN din[58]
    DIRECTION INPUT ;
    USE SIGNAL ;
    PORT
      LAYER M5 ;
        RECT  5.904 0 5.928 0.084 ;
    END
  END din[58]
  PIN din[59]
    DIRECTION INPUT ;
    USE SIGNAL ;
    PORT
      LAYER M5 ;
        RECT  2.016 0 2.04 0.084 ;
    END
  END din[59]
  PIN din[5]
    DIRECTION INPUT ;
    USE SIGNAL ;
    PORT
      LAYER M5 ;
        RECT  16.224 0 16.248 0.084 ;
    END
  END din[5]
  PIN din[60]
    DIRECTION INPUT ;
    USE SIGNAL ;
    PORT
      LAYER M5 ;
        RECT  5.568 0 5.592 0.084 ;
    END
  END din[60]
  PIN din[61]
    DIRECTION INPUT ;
    USE SIGNAL ;
    PORT
      LAYER M5 ;
        RECT  3.936 0 3.96 0.084 ;
    END
  END din[61]
  PIN din[62]
    DIRECTION INPUT ;
    USE SIGNAL ;
    PORT
      LAYER M5 ;
        RECT  2.592 0 2.616 0.084 ;
    END
  END din[62]
  PIN din[63]
    DIRECTION INPUT ;
    USE SIGNAL ;
    PORT
      LAYER M5 ;
        RECT  5.856 0 5.88 0.084 ;
    END
  END din[63]
  PIN din[64]
    DIRECTION INPUT ;
    USE SIGNAL ;
    PORT
      LAYER M5 ;
        RECT  41.616 0 41.64 0.084 ;
    END
  END din[64]
  PIN din[65]
    DIRECTION INPUT ;
    USE SIGNAL ;
    PORT
      LAYER M7 ;
        RECT  49.344 0 49.376 0.069 ;
    END
  END din[65]
  PIN din[66]
    DIRECTION INPUT ;
    USE SIGNAL ;
    PORT
      LAYER M5 ;
        RECT  52.944 0 52.968 0.084 ;
    END
  END din[66]
  PIN din[67]
    DIRECTION INPUT ;
    USE SIGNAL ;
    PORT
      LAYER M5 ;
        RECT  52.368 0 52.392 0.084 ;
    END
  END din[67]
  PIN din[68]
    DIRECTION INPUT ;
    USE SIGNAL ;
    PORT
      LAYER M5 ;
        RECT  53.952 0 53.976 0.084 ;
    END
  END din[68]
  PIN din[69]
    DIRECTION INPUT ;
    USE SIGNAL ;
    PORT
      LAYER M5 ;
        RECT  52.896 0 52.92 0.084 ;
    END
  END din[69]
  PIN din[6]
    DIRECTION INPUT ;
    USE SIGNAL ;
    PORT
      LAYER M7 ;
        RECT  20.928 0 20.96 0.069 ;
    END
  END din[6]
  PIN din[70]
    DIRECTION INPUT ;
    USE SIGNAL ;
    PORT
      LAYER M5 ;
        RECT  55.632 0 55.656 0.084 ;
    END
  END din[70]
  PIN din[71]
    DIRECTION INPUT ;
    USE SIGNAL ;
    PORT
      LAYER M7 ;
        RECT  57.28 0 57.312 0.069 ;
    END
  END din[71]
  PIN din[72]
    DIRECTION INPUT ;
    USE SIGNAL ;
    PORT
      LAYER M5 ;
        RECT  50.112 0 50.136 0.084 ;
    END
  END din[72]
  PIN din[73]
    DIRECTION INPUT ;
    USE SIGNAL ;
    PORT
      LAYER M7 ;
        RECT  57.088 0 57.12 0.069 ;
    END
  END din[73]
  PIN din[74]
    DIRECTION INPUT ;
    USE SIGNAL ;
    PORT
      LAYER M7 ;
        RECT  58.496 0 58.528 0.069 ;
    END
  END din[74]
  PIN din[75]
    DIRECTION INPUT ;
    USE SIGNAL ;
    PORT
      LAYER M7 ;
        RECT  58.176 0 58.208 0.069 ;
    END
  END din[75]
  PIN din[76]
    DIRECTION INPUT ;
    USE SIGNAL ;
    PORT
      LAYER M7 ;
        RECT  58.432 0 58.464 0.069 ;
    END
  END din[76]
  PIN din[77]
    DIRECTION INPUT ;
    USE SIGNAL ;
    PORT
      LAYER M5 ;
        RECT  54.48 0 54.504 0.084 ;
    END
  END din[77]
  PIN din[78]
    DIRECTION INPUT ;
    USE SIGNAL ;
    PORT
      LAYER M5 ;
        RECT  54.672 0 54.696 0.084 ;
    END
  END din[78]
  PIN din[79]
    DIRECTION INPUT ;
    USE SIGNAL ;
    PORT
      LAYER M7 ;
        RECT  46.272 0 46.304 0.069 ;
    END
  END din[79]
  PIN din[7]
    DIRECTION INPUT ;
    USE SIGNAL ;
    PORT
      LAYER M7 ;
        RECT  19.648 0 19.68 0.069 ;
    END
  END din[7]
  PIN din[80]
    DIRECTION INPUT ;
    USE SIGNAL ;
    PORT
      LAYER M5 ;
        RECT  55.68 0 55.704 0.084 ;
    END
  END din[80]
  PIN din[81]
    DIRECTION INPUT ;
    USE SIGNAL ;
    PORT
      LAYER M7 ;
        RECT  58.048 0 58.08 0.069 ;
    END
  END din[81]
  PIN din[82]
    DIRECTION INPUT ;
    USE SIGNAL ;
    PORT
      LAYER M5 ;
        RECT  52.032 0 52.056 0.084 ;
    END
  END din[82]
  PIN din[83]
    DIRECTION INPUT ;
    USE SIGNAL ;
    PORT
      LAYER M5 ;
        RECT  50.256 0 50.28 0.084 ;
    END
  END din[83]
  PIN din[84]
    DIRECTION INPUT ;
    USE SIGNAL ;
    PORT
      LAYER M7 ;
        RECT  47.616 0 47.648 0.069 ;
    END
  END din[84]
  PIN din[85]
    DIRECTION INPUT ;
    USE SIGNAL ;
    PORT
      LAYER M7 ;
        RECT  48.832 0 48.864 0.069 ;
    END
  END din[85]
  PIN din[86]
    DIRECTION INPUT ;
    USE SIGNAL ;
    PORT
      LAYER M5 ;
        RECT  51.552 0 51.576 0.084 ;
    END
  END din[86]
  PIN din[87]
    DIRECTION INPUT ;
    USE SIGNAL ;
    PORT
      LAYER M5 ;
        RECT  51.888 0 51.912 0.084 ;
    END
  END din[87]
  PIN din[88]
    DIRECTION INPUT ;
    USE SIGNAL ;
    PORT
      LAYER M7 ;
        RECT  48.256 0 48.288 0.069 ;
    END
  END din[88]
  PIN din[89]
    DIRECTION INPUT ;
    USE SIGNAL ;
    PORT
      LAYER M5 ;
        RECT  49.824 0 49.848 0.084 ;
    END
  END din[89]
  PIN din[8]
    DIRECTION INPUT ;
    USE SIGNAL ;
    PORT
      LAYER M5 ;
        RECT  4.416 0 4.44 0.084 ;
    END
  END din[8]
  PIN din[90]
    DIRECTION INPUT ;
    USE SIGNAL ;
    PORT
      LAYER M5 ;
        RECT  40.416 0 40.44 0.084 ;
    END
  END din[90]
  PIN din[91]
    DIRECTION INPUT ;
    USE SIGNAL ;
    PORT
      LAYER M7 ;
        RECT  47.36 0 47.392 0.069 ;
    END
  END din[91]
  PIN din[92]
    DIRECTION INPUT ;
    USE SIGNAL ;
    PORT
      LAYER M5 ;
        RECT  42.096 0 42.12 0.084 ;
    END
  END din[92]
  PIN din[93]
    DIRECTION INPUT ;
    USE SIGNAL ;
    PORT
      LAYER M7 ;
        RECT  46.592 0 46.624 0.069 ;
    END
  END din[93]
  PIN din[94]
    DIRECTION INPUT ;
    USE SIGNAL ;
    PORT
      LAYER M7 ;
        RECT  46.208 0 46.24 0.069 ;
    END
  END din[94]
  PIN din[95]
    DIRECTION INPUT ;
    USE SIGNAL ;
    PORT
      LAYER M7 ;
        RECT  46.336 0 46.368 0.069 ;
    END
  END din[95]
  PIN din[96]
    DIRECTION INPUT ;
    USE SIGNAL ;
    PORT
      LAYER M7 ;
        RECT  46.08 0 46.112 0.069 ;
    END
  END din[96]
  PIN din[97]
    DIRECTION INPUT ;
    USE SIGNAL ;
    PORT
      LAYER M5 ;
        RECT  43.296 0 43.32 0.084 ;
    END
  END din[97]
  PIN din[98]
    DIRECTION INPUT ;
    USE SIGNAL ;
    PORT
      LAYER M7 ;
        RECT  46.016 0 46.048 0.069 ;
    END
  END din[98]
  PIN din[99]
    DIRECTION INPUT ;
    USE SIGNAL ;
    PORT
      LAYER M5 ;
        RECT  42 0 42.024 0.084 ;
    END
  END din[99]
  PIN din[9]
    DIRECTION INPUT ;
    USE SIGNAL ;
    PORT
      LAYER M7 ;
        RECT  19.008 0 19.04 0.069 ;
    END
  END din[9]
  PIN dout[0]
    DIRECTION OUTPUT ;
    USE SIGNAL ;
    PORT
      LAYER M7 ;
        RECT  14.528 75.931 14.56 76 ;
    END
  END dout[0]
  PIN dout[1000]
    DIRECTION OUTPUT ;
    USE SIGNAL ;
    PORT
      LAYER M5 ;
        RECT  98.544 75.916 98.568 76 ;
    END
  END dout[1000]
  PIN dout[1001]
    DIRECTION OUTPUT ;
    USE SIGNAL ;
    PORT
      LAYER M5 ;
        RECT  97.488 75.916 97.512 76 ;
    END
  END dout[1001]
  PIN dout[1002]
    DIRECTION OUTPUT ;
    USE SIGNAL ;
    PORT
      LAYER M5 ;
        RECT  96.48 75.916 96.504 76 ;
    END
  END dout[1002]
  PIN dout[1003]
    DIRECTION OUTPUT ;
    USE SIGNAL ;
    PORT
      LAYER M5 ;
        RECT  104.304 75.916 104.328 76 ;
    END
  END dout[1003]
  PIN dout[1004]
    DIRECTION OUTPUT ;
    USE SIGNAL ;
    PORT
      LAYER M5 ;
        RECT  87.168 75.916 87.192 76 ;
    END
  END dout[1004]
  PIN dout[1005]
    DIRECTION OUTPUT ;
    USE SIGNAL ;
    PORT
      LAYER M7 ;
        RECT  99.712 75.931 99.744 76 ;
    END
  END dout[1005]
  PIN dout[1006]
    DIRECTION OUTPUT ;
    USE SIGNAL ;
    PORT
      LAYER M7 ;
        RECT  90.24 75.931 90.272 76 ;
    END
  END dout[1006]
  PIN dout[1007]
    DIRECTION OUTPUT ;
    USE SIGNAL ;
    PORT
      LAYER M5 ;
        RECT  105.216 75.916 105.24 76 ;
    END
  END dout[1007]
  PIN dout[1008]
    DIRECTION OUTPUT ;
    USE SIGNAL ;
    PORT
      LAYER M5 ;
        RECT  109.248 75.916 109.272 76 ;
    END
  END dout[1008]
  PIN dout[1009]
    DIRECTION OUTPUT ;
    USE SIGNAL ;
    PORT
      LAYER M5 ;
        RECT  93.264 75.916 93.288 76 ;
    END
  END dout[1009]
  PIN dout[100]
    DIRECTION OUTPUT ;
    USE SIGNAL ;
    PORT
      LAYER M7 ;
        RECT  80.832 75.931 80.864 76 ;
    END
  END dout[100]
  PIN dout[1010]
    DIRECTION OUTPUT ;
    USE SIGNAL ;
    PORT
      LAYER M7 ;
        RECT  80.256 75.931 80.288 76 ;
    END
  END dout[1010]
  PIN dout[1011]
    DIRECTION OUTPUT ;
    USE SIGNAL ;
    PORT
      LAYER M5 ;
        RECT  92.544 75.916 92.568 76 ;
    END
  END dout[1011]
  PIN dout[1012]
    DIRECTION OUTPUT ;
    USE SIGNAL ;
    PORT
      LAYER M5 ;
        RECT  104.016 75.916 104.04 76 ;
    END
  END dout[1012]
  PIN dout[1013]
    DIRECTION OUTPUT ;
    USE SIGNAL ;
    PORT
      LAYER M7 ;
        RECT  103.808 75.931 103.84 76 ;
    END
  END dout[1013]
  PIN dout[1014]
    DIRECTION OUTPUT ;
    USE SIGNAL ;
    PORT
      LAYER M5 ;
        RECT  107.376 75.916 107.4 76 ;
    END
  END dout[1014]
  PIN dout[1015]
    DIRECTION OUTPUT ;
    USE SIGNAL ;
    PORT
      LAYER M7 ;
        RECT  102.4 75.931 102.432 76 ;
    END
  END dout[1015]
  PIN dout[1016]
    DIRECTION OUTPUT ;
    USE SIGNAL ;
    PORT
      LAYER M5 ;
        RECT  65.904 75.916 65.928 76 ;
    END
  END dout[1016]
  PIN dout[1017]
    DIRECTION OUTPUT ;
    USE SIGNAL ;
    PORT
      LAYER M5 ;
        RECT  95.664 75.916 95.688 76 ;
    END
  END dout[1017]
  PIN dout[1018]
    DIRECTION OUTPUT ;
    USE SIGNAL ;
    PORT
      LAYER M5 ;
        RECT  81.648 75.916 81.672 76 ;
    END
  END dout[1018]
  PIN dout[1019]
    DIRECTION OUTPUT ;
    USE SIGNAL ;
    PORT
      LAYER M5 ;
        RECT  98.016 75.916 98.04 76 ;
    END
  END dout[1019]
  PIN dout[101]
    DIRECTION OUTPUT ;
    USE SIGNAL ;
    PORT
      LAYER M5 ;
        RECT  66.624 75.916 66.648 76 ;
    END
  END dout[101]
  PIN dout[1020]
    DIRECTION OUTPUT ;
    USE SIGNAL ;
    PORT
      LAYER M5 ;
        RECT  93.936 75.916 93.96 76 ;
    END
  END dout[1020]
  PIN dout[1021]
    DIRECTION OUTPUT ;
    USE SIGNAL ;
    PORT
      LAYER M7 ;
        RECT  61.696 75.931 61.728 76 ;
    END
  END dout[1021]
  PIN dout[1022]
    DIRECTION OUTPUT ;
    USE SIGNAL ;
    PORT
      LAYER M7 ;
        RECT  78.528 75.931 78.56 76 ;
    END
  END dout[1022]
  PIN dout[1023]
    DIRECTION OUTPUT ;
    USE SIGNAL ;
    PORT
      LAYER M7 ;
        RECT  64.128 75.931 64.16 76 ;
    END
  END dout[1023]
  PIN dout[102]
    DIRECTION OUTPUT ;
    USE SIGNAL ;
    PORT
      LAYER M5 ;
        RECT  60.24 75.916 60.264 76 ;
    END
  END dout[102]
  PIN dout[103]
    DIRECTION OUTPUT ;
    USE SIGNAL ;
    PORT
      LAYER M5 ;
        RECT  73.152 75.916 73.176 76 ;
    END
  END dout[103]
  PIN dout[104]
    DIRECTION OUTPUT ;
    USE SIGNAL ;
    PORT
      LAYER M5 ;
        RECT  66.144 75.916 66.168 76 ;
    END
  END dout[104]
  PIN dout[105]
    DIRECTION OUTPUT ;
    USE SIGNAL ;
    PORT
      LAYER M5 ;
        RECT  54.864 75.916 54.888 76 ;
    END
  END dout[105]
  PIN dout[106]
    DIRECTION OUTPUT ;
    USE SIGNAL ;
    PORT
      LAYER M5 ;
        RECT  72.72 75.916 72.744 76 ;
    END
  END dout[106]
  PIN dout[107]
    DIRECTION OUTPUT ;
    USE SIGNAL ;
    PORT
      LAYER M5 ;
        RECT  72.96 75.916 72.984 76 ;
    END
  END dout[107]
  PIN dout[108]
    DIRECTION OUTPUT ;
    USE SIGNAL ;
    PORT
      LAYER M5 ;
        RECT  74.208 75.916 74.232 76 ;
    END
  END dout[108]
  PIN dout[109]
    DIRECTION OUTPUT ;
    USE SIGNAL ;
    PORT
      LAYER M5 ;
        RECT  72.912 75.916 72.936 76 ;
    END
  END dout[109]
  PIN dout[10]
    DIRECTION OUTPUT ;
    USE SIGNAL ;
    PORT
      LAYER M5 ;
        RECT  34.896 75.916 34.92 76 ;
    END
  END dout[10]
  PIN dout[110]
    DIRECTION OUTPUT ;
    USE SIGNAL ;
    PORT
      LAYER M5 ;
        RECT  45.84 75.916 45.864 76 ;
    END
  END dout[110]
  PIN dout[111]
    DIRECTION OUTPUT ;
    USE SIGNAL ;
    PORT
      LAYER M5 ;
        RECT  74.304 75.916 74.328 76 ;
    END
  END dout[111]
  PIN dout[112]
    DIRECTION OUTPUT ;
    USE SIGNAL ;
    PORT
      LAYER M5 ;
        RECT  73.968 75.916 73.992 76 ;
    END
  END dout[112]
  PIN dout[113]
    DIRECTION OUTPUT ;
    USE SIGNAL ;
    PORT
      LAYER M5 ;
        RECT  65.184 75.916 65.208 76 ;
    END
  END dout[113]
  PIN dout[114]
    DIRECTION OUTPUT ;
    USE SIGNAL ;
    PORT
      LAYER M5 ;
        RECT  34.56 75.916 34.584 76 ;
    END
  END dout[114]
  PIN dout[115]
    DIRECTION OUTPUT ;
    USE SIGNAL ;
    PORT
      LAYER M7 ;
        RECT  60.992 75.931 61.024 76 ;
    END
  END dout[115]
  PIN dout[116]
    DIRECTION OUTPUT ;
    USE SIGNAL ;
    PORT
      LAYER M5 ;
        RECT  66.192 75.916 66.216 76 ;
    END
  END dout[116]
  PIN dout[117]
    DIRECTION OUTPUT ;
    USE SIGNAL ;
    PORT
      LAYER M5 ;
        RECT  47.376 75.916 47.4 76 ;
    END
  END dout[117]
  PIN dout[118]
    DIRECTION OUTPUT ;
    USE SIGNAL ;
    PORT
      LAYER M5 ;
        RECT  70.704 75.916 70.728 76 ;
    END
  END dout[118]
  PIN dout[119]
    DIRECTION OUTPUT ;
    USE SIGNAL ;
    PORT
      LAYER M5 ;
        RECT  66 75.916 66.024 76 ;
    END
  END dout[119]
  PIN dout[11]
    DIRECTION OUTPUT ;
    USE SIGNAL ;
    PORT
      LAYER M5 ;
        RECT  36.672 75.916 36.696 76 ;
    END
  END dout[11]
  PIN dout[120]
    DIRECTION OUTPUT ;
    USE SIGNAL ;
    PORT
      LAYER M5 ;
        RECT  66.816 75.916 66.84 76 ;
    END
  END dout[120]
  PIN dout[121]
    DIRECTION OUTPUT ;
    USE SIGNAL ;
    PORT
      LAYER M7 ;
        RECT  42.368 75.931 42.4 76 ;
    END
  END dout[121]
  PIN dout[122]
    DIRECTION OUTPUT ;
    USE SIGNAL ;
    PORT
      LAYER M7 ;
        RECT  41.664 75.931 41.696 76 ;
    END
  END dout[122]
  PIN dout[123]
    DIRECTION OUTPUT ;
    USE SIGNAL ;
    PORT
      LAYER M5 ;
        RECT  42.816 75.916 42.84 76 ;
    END
  END dout[123]
  PIN dout[124]
    DIRECTION OUTPUT ;
    USE SIGNAL ;
    PORT
      LAYER M7 ;
        RECT  41.28 75.931 41.312 76 ;
    END
  END dout[124]
  PIN dout[125]
    DIRECTION OUTPUT ;
    USE SIGNAL ;
    PORT
      LAYER M7 ;
        RECT  49.856 75.931 49.888 76 ;
    END
  END dout[125]
  PIN dout[126]
    DIRECTION OUTPUT ;
    USE SIGNAL ;
    PORT
      LAYER M7 ;
        RECT  41.152 75.931 41.184 76 ;
    END
  END dout[126]
  PIN dout[127]
    DIRECTION OUTPUT ;
    USE SIGNAL ;
    PORT
      LAYER M5 ;
        RECT  44.784 75.916 44.808 76 ;
    END
  END dout[127]
  PIN dout[128]
    DIRECTION OUTPUT ;
    USE SIGNAL ;
    PORT
      LAYER M5 ;
        RECT  72 75.916 72.024 76 ;
    END
  END dout[128]
  PIN dout[129]
    DIRECTION OUTPUT ;
    USE SIGNAL ;
    PORT
      LAYER M7 ;
        RECT  65.152 75.931 65.184 76 ;
    END
  END dout[129]
  PIN dout[12]
    DIRECTION OUTPUT ;
    USE SIGNAL ;
    PORT
      LAYER M5 ;
        RECT  36.768 75.916 36.792 76 ;
    END
  END dout[12]
  PIN dout[130]
    DIRECTION OUTPUT ;
    USE SIGNAL ;
    PORT
      LAYER M5 ;
        RECT  72.096 75.916 72.12 76 ;
    END
  END dout[130]
  PIN dout[131]
    DIRECTION OUTPUT ;
    USE SIGNAL ;
    PORT
      LAYER M5 ;
        RECT  57.84 75.916 57.864 76 ;
    END
  END dout[131]
  PIN dout[132]
    DIRECTION OUTPUT ;
    USE SIGNAL ;
    PORT
      LAYER M5 ;
        RECT  73.104 75.916 73.128 76 ;
    END
  END dout[132]
  PIN dout[133]
    DIRECTION OUTPUT ;
    USE SIGNAL ;
    PORT
      LAYER M7 ;
        RECT  63.168 75.931 63.2 76 ;
    END
  END dout[133]
  PIN dout[134]
    DIRECTION OUTPUT ;
    USE SIGNAL ;
    PORT
      LAYER M7 ;
        RECT  61.184 75.931 61.216 76 ;
    END
  END dout[134]
  PIN dout[135]
    DIRECTION OUTPUT ;
    USE SIGNAL ;
    PORT
      LAYER M5 ;
        RECT  71.04 75.916 71.064 76 ;
    END
  END dout[135]
  PIN dout[136]
    DIRECTION OUTPUT ;
    USE SIGNAL ;
    PORT
      LAYER M7 ;
        RECT  63.36 75.931 63.392 76 ;
    END
  END dout[136]
  PIN dout[137]
    DIRECTION OUTPUT ;
    USE SIGNAL ;
    PORT
      LAYER M5 ;
        RECT  65.424 75.916 65.448 76 ;
    END
  END dout[137]
  PIN dout[138]
    DIRECTION OUTPUT ;
    USE SIGNAL ;
    PORT
      LAYER M5 ;
        RECT  72.192 75.916 72.216 76 ;
    END
  END dout[138]
  PIN dout[139]
    DIRECTION OUTPUT ;
    USE SIGNAL ;
    PORT
      LAYER M5 ;
        RECT  71.616 75.916 71.64 76 ;
    END
  END dout[139]
  PIN dout[13]
    DIRECTION OUTPUT ;
    USE SIGNAL ;
    PORT
      LAYER M7 ;
        RECT  40.896 75.931 40.928 76 ;
    END
  END dout[13]
  PIN dout[140]
    DIRECTION OUTPUT ;
    USE SIGNAL ;
    PORT
      LAYER M5 ;
        RECT  67.68 75.916 67.704 76 ;
    END
  END dout[140]
  PIN dout[141]
    DIRECTION OUTPUT ;
    USE SIGNAL ;
    PORT
      LAYER M5 ;
        RECT  68.544 75.916 68.568 76 ;
    END
  END dout[141]
  PIN dout[142]
    DIRECTION OUTPUT ;
    USE SIGNAL ;
    PORT
      LAYER M7 ;
        RECT  60.864 75.931 60.896 76 ;
    END
  END dout[142]
  PIN dout[143]
    DIRECTION OUTPUT ;
    USE SIGNAL ;
    PORT
      LAYER M5 ;
        RECT  70.128 75.916 70.152 76 ;
    END
  END dout[143]
  PIN dout[144]
    DIRECTION OUTPUT ;
    USE SIGNAL ;
    PORT
      LAYER M5 ;
        RECT  66.672 75.916 66.696 76 ;
    END
  END dout[144]
  PIN dout[145]
    DIRECTION OUTPUT ;
    USE SIGNAL ;
    PORT
      LAYER M5 ;
        RECT  68.688 75.916 68.712 76 ;
    END
  END dout[145]
  PIN dout[146]
    DIRECTION OUTPUT ;
    USE SIGNAL ;
    PORT
      LAYER M5 ;
        RECT  68.016 75.916 68.04 76 ;
    END
  END dout[146]
  PIN dout[147]
    DIRECTION OUTPUT ;
    USE SIGNAL ;
    PORT
      LAYER M5 ;
        RECT  68.928 75.916 68.952 76 ;
    END
  END dout[147]
  PIN dout[148]
    DIRECTION OUTPUT ;
    USE SIGNAL ;
    PORT
      LAYER M5 ;
        RECT  69.552 75.916 69.576 76 ;
    END
  END dout[148]
  PIN dout[149]
    DIRECTION OUTPUT ;
    USE SIGNAL ;
    PORT
      LAYER M5 ;
        RECT  70.464 75.916 70.488 76 ;
    END
  END dout[149]
  PIN dout[14]
    DIRECTION OUTPUT ;
    USE SIGNAL ;
    PORT
      LAYER M5 ;
        RECT  33.984 75.916 34.008 76 ;
    END
  END dout[14]
  PIN dout[150]
    DIRECTION OUTPUT ;
    USE SIGNAL ;
    PORT
      LAYER M7 ;
        RECT  64.576 75.931 64.608 76 ;
    END
  END dout[150]
  PIN dout[151]
    DIRECTION OUTPUT ;
    USE SIGNAL ;
    PORT
      LAYER M5 ;
        RECT  65.808 75.916 65.832 76 ;
    END
  END dout[151]
  PIN dout[152]
    DIRECTION OUTPUT ;
    USE SIGNAL ;
    PORT
      LAYER M5 ;
        RECT  69.936 75.916 69.96 76 ;
    END
  END dout[152]
  PIN dout[153]
    DIRECTION OUTPUT ;
    USE SIGNAL ;
    PORT
      LAYER M5 ;
        RECT  56.256 75.916 56.28 76 ;
    END
  END dout[153]
  PIN dout[154]
    DIRECTION OUTPUT ;
    USE SIGNAL ;
    PORT
      LAYER M5 ;
        RECT  57.408 75.916 57.432 76 ;
    END
  END dout[154]
  PIN dout[155]
    DIRECTION OUTPUT ;
    USE SIGNAL ;
    PORT
      LAYER M5 ;
        RECT  59.904 75.916 59.928 76 ;
    END
  END dout[155]
  PIN dout[156]
    DIRECTION OUTPUT ;
    USE SIGNAL ;
    PORT
      LAYER M5 ;
        RECT  60.336 75.916 60.36 76 ;
    END
  END dout[156]
  PIN dout[157]
    DIRECTION OUTPUT ;
    USE SIGNAL ;
    PORT
      LAYER M7 ;
        RECT  51.712 75.931 51.744 76 ;
    END
  END dout[157]
  PIN dout[158]
    DIRECTION OUTPUT ;
    USE SIGNAL ;
    PORT
      LAYER M5 ;
        RECT  59.664 75.916 59.688 76 ;
    END
  END dout[158]
  PIN dout[159]
    DIRECTION OUTPUT ;
    USE SIGNAL ;
    PORT
      LAYER M5 ;
        RECT  56.304 75.916 56.328 76 ;
    END
  END dout[159]
  PIN dout[15]
    DIRECTION OUTPUT ;
    USE SIGNAL ;
    PORT
      LAYER M5 ;
        RECT  37.248 75.916 37.272 76 ;
    END
  END dout[15]
  PIN dout[160]
    DIRECTION OUTPUT ;
    USE SIGNAL ;
    PORT
      LAYER M7 ;
        RECT  53.76 75.931 53.792 76 ;
    END
  END dout[160]
  PIN dout[161]
    DIRECTION OUTPUT ;
    USE SIGNAL ;
    PORT
      LAYER M5 ;
        RECT  66.384 75.916 66.408 76 ;
    END
  END dout[161]
  PIN dout[162]
    DIRECTION OUTPUT ;
    USE SIGNAL ;
    PORT
      LAYER M7 ;
        RECT  50.368 75.931 50.4 76 ;
    END
  END dout[162]
  PIN dout[163]
    DIRECTION OUTPUT ;
    USE SIGNAL ;
    PORT
      LAYER M5 ;
        RECT  43.392 75.916 43.416 76 ;
    END
  END dout[163]
  PIN dout[164]
    DIRECTION OUTPUT ;
    USE SIGNAL ;
    PORT
      LAYER M5 ;
        RECT  46.56 75.916 46.584 76 ;
    END
  END dout[164]
  PIN dout[165]
    DIRECTION OUTPUT ;
    USE SIGNAL ;
    PORT
      LAYER M5 ;
        RECT  44.064 75.916 44.088 76 ;
    END
  END dout[165]
  PIN dout[166]
    DIRECTION OUTPUT ;
    USE SIGNAL ;
    PORT
      LAYER M5 ;
        RECT  55.632 75.916 55.656 76 ;
    END
  END dout[166]
  PIN dout[167]
    DIRECTION OUTPUT ;
    USE SIGNAL ;
    PORT
      LAYER M5 ;
        RECT  46.8 75.916 46.824 76 ;
    END
  END dout[167]
  PIN dout[168]
    DIRECTION OUTPUT ;
    USE SIGNAL ;
    PORT
      LAYER M7 ;
        RECT  49.088 75.931 49.12 76 ;
    END
  END dout[168]
  PIN dout[169]
    DIRECTION OUTPUT ;
    USE SIGNAL ;
    PORT
      LAYER M7 ;
        RECT  50.496 75.931 50.528 76 ;
    END
  END dout[169]
  PIN dout[16]
    DIRECTION OUTPUT ;
    USE SIGNAL ;
    PORT
      LAYER M7 ;
        RECT  40.064 75.931 40.096 76 ;
    END
  END dout[16]
  PIN dout[170]
    DIRECTION OUTPUT ;
    USE SIGNAL ;
    PORT
      LAYER M5 ;
        RECT  48.144 75.916 48.168 76 ;
    END
  END dout[170]
  PIN dout[171]
    DIRECTION OUTPUT ;
    USE SIGNAL ;
    PORT
      LAYER M5 ;
        RECT  54.576 75.916 54.6 76 ;
    END
  END dout[171]
  PIN dout[172]
    DIRECTION OUTPUT ;
    USE SIGNAL ;
    PORT
      LAYER M7 ;
        RECT  49.28 75.931 49.312 76 ;
    END
  END dout[172]
  PIN dout[173]
    DIRECTION OUTPUT ;
    USE SIGNAL ;
    PORT
      LAYER M5 ;
        RECT  44.256 75.916 44.28 76 ;
    END
  END dout[173]
  PIN dout[174]
    DIRECTION OUTPUT ;
    USE SIGNAL ;
    PORT
      LAYER M5 ;
        RECT  35.904 75.916 35.928 76 ;
    END
  END dout[174]
  PIN dout[175]
    DIRECTION OUTPUT ;
    USE SIGNAL ;
    PORT
      LAYER M7 ;
        RECT  41.472 75.931 41.504 76 ;
    END
  END dout[175]
  PIN dout[176]
    DIRECTION OUTPUT ;
    USE SIGNAL ;
    PORT
      LAYER M5 ;
        RECT  35.76 75.916 35.784 76 ;
    END
  END dout[176]
  PIN dout[177]
    DIRECTION OUTPUT ;
    USE SIGNAL ;
    PORT
      LAYER M5 ;
        RECT  67.296 75.916 67.32 76 ;
    END
  END dout[177]
  PIN dout[178]
    DIRECTION OUTPUT ;
    USE SIGNAL ;
    PORT
      LAYER M7 ;
        RECT  53.248 75.931 53.28 76 ;
    END
  END dout[178]
  PIN dout[179]
    DIRECTION OUTPUT ;
    USE SIGNAL ;
    PORT
      LAYER M5 ;
        RECT  48.384 75.916 48.408 76 ;
    END
  END dout[179]
  PIN dout[17]
    DIRECTION OUTPUT ;
    USE SIGNAL ;
    PORT
      LAYER M7 ;
        RECT  38.72 75.931 38.752 76 ;
    END
  END dout[17]
  PIN dout[180]
    DIRECTION OUTPUT ;
    USE SIGNAL ;
    PORT
      LAYER M5 ;
        RECT  37.536 75.916 37.56 76 ;
    END
  END dout[180]
  PIN dout[181]
    DIRECTION OUTPUT ;
    USE SIGNAL ;
    PORT
      LAYER M5 ;
        RECT  70.896 75.916 70.92 76 ;
    END
  END dout[181]
  PIN dout[182]
    DIRECTION OUTPUT ;
    USE SIGNAL ;
    PORT
      LAYER M5 ;
        RECT  43.104 75.916 43.128 76 ;
    END
  END dout[182]
  PIN dout[183]
    DIRECTION OUTPUT ;
    USE SIGNAL ;
    PORT
      LAYER M5 ;
        RECT  73.584 75.916 73.608 76 ;
    END
  END dout[183]
  PIN dout[184]
    DIRECTION OUTPUT ;
    USE SIGNAL ;
    PORT
      LAYER M5 ;
        RECT  71.952 75.916 71.976 76 ;
    END
  END dout[184]
  PIN dout[185]
    DIRECTION OUTPUT ;
    USE SIGNAL ;
    PORT
      LAYER M5 ;
        RECT  36.24 75.916 36.264 76 ;
    END
  END dout[185]
  PIN dout[186]
    DIRECTION OUTPUT ;
    USE SIGNAL ;
    PORT
      LAYER M5 ;
        RECT  34.224 75.916 34.248 76 ;
    END
  END dout[186]
  PIN dout[187]
    DIRECTION OUTPUT ;
    USE SIGNAL ;
    PORT
      LAYER M7 ;
        RECT  63.616 75.931 63.648 76 ;
    END
  END dout[187]
  PIN dout[188]
    DIRECTION OUTPUT ;
    USE SIGNAL ;
    PORT
      LAYER M5 ;
        RECT  71.328 75.916 71.352 76 ;
    END
  END dout[188]
  PIN dout[189]
    DIRECTION OUTPUT ;
    USE SIGNAL ;
    PORT
      LAYER M5 ;
        RECT  36.48 75.916 36.504 76 ;
    END
  END dout[189]
  PIN dout[18]
    DIRECTION OUTPUT ;
    USE SIGNAL ;
    PORT
      LAYER M5 ;
        RECT  35.52 75.916 35.544 76 ;
    END
  END dout[18]
  PIN dout[190]
    DIRECTION OUTPUT ;
    USE SIGNAL ;
    PORT
      LAYER M5 ;
        RECT  72.384 75.916 72.408 76 ;
    END
  END dout[190]
  PIN dout[191]
    DIRECTION OUTPUT ;
    USE SIGNAL ;
    PORT
      LAYER M5 ;
        RECT  72.624 75.916 72.648 76 ;
    END
  END dout[191]
  PIN dout[192]
    DIRECTION OUTPUT ;
    USE SIGNAL ;
    PORT
      LAYER M7 ;
        RECT  23.68 75.931 23.712 76 ;
    END
  END dout[192]
  PIN dout[193]
    DIRECTION OUTPUT ;
    USE SIGNAL ;
    PORT
      LAYER M5 ;
        RECT  9.552 75.916 9.576 76 ;
    END
  END dout[193]
  PIN dout[194]
    DIRECTION OUTPUT ;
    USE SIGNAL ;
    PORT
      LAYER M5 ;
        RECT  21.12 75.916 21.144 76 ;
    END
  END dout[194]
  PIN dout[195]
    DIRECTION OUTPUT ;
    USE SIGNAL ;
    PORT
      LAYER M5 ;
        RECT  9.168 75.916 9.192 76 ;
    END
  END dout[195]
  PIN dout[196]
    DIRECTION OUTPUT ;
    USE SIGNAL ;
    PORT
      LAYER M5 ;
        RECT  16.176 75.916 16.2 76 ;
    END
  END dout[196]
  PIN dout[197]
    DIRECTION OUTPUT ;
    USE SIGNAL ;
    PORT
      LAYER M5 ;
        RECT  6.816 75.916 6.84 76 ;
    END
  END dout[197]
  PIN dout[198]
    DIRECTION OUTPUT ;
    USE SIGNAL ;
    PORT
      LAYER M7 ;
        RECT  22.784 75.931 22.816 76 ;
    END
  END dout[198]
  PIN dout[199]
    DIRECTION OUTPUT ;
    USE SIGNAL ;
    PORT
      LAYER M5 ;
        RECT  32.208 75.916 32.232 76 ;
    END
  END dout[199]
  PIN dout[19]
    DIRECTION OUTPUT ;
    USE SIGNAL ;
    PORT
      LAYER M7 ;
        RECT  39.36 75.931 39.392 76 ;
    END
  END dout[19]
  PIN dout[1]
    DIRECTION OUTPUT ;
    USE SIGNAL ;
    PORT
      LAYER M5 ;
        RECT  27.984 75.916 28.008 76 ;
    END
  END dout[1]
  PIN dout[200]
    DIRECTION OUTPUT ;
    USE SIGNAL ;
    PORT
      LAYER M5 ;
        RECT  26.88 75.916 26.904 76 ;
    END
  END dout[200]
  PIN dout[201]
    DIRECTION OUTPUT ;
    USE SIGNAL ;
    PORT
      LAYER M5 ;
        RECT  27.744 75.916 27.768 76 ;
    END
  END dout[201]
  PIN dout[202]
    DIRECTION OUTPUT ;
    USE SIGNAL ;
    PORT
      LAYER M5 ;
        RECT  20.88 75.916 20.904 76 ;
    END
  END dout[202]
  PIN dout[203]
    DIRECTION OUTPUT ;
    USE SIGNAL ;
    PORT
      LAYER M7 ;
        RECT  22.848 75.931 22.88 76 ;
    END
  END dout[203]
  PIN dout[204]
    DIRECTION OUTPUT ;
    USE SIGNAL ;
    PORT
      LAYER M5 ;
        RECT  6.912 75.916 6.936 76 ;
    END
  END dout[204]
  PIN dout[205]
    DIRECTION OUTPUT ;
    USE SIGNAL ;
    PORT
      LAYER M7 ;
        RECT  12.416 75.931 12.448 76 ;
    END
  END dout[205]
  PIN dout[206]
    DIRECTION OUTPUT ;
    USE SIGNAL ;
    PORT
      LAYER M5 ;
        RECT  7.92 75.916 7.944 76 ;
    END
  END dout[206]
  PIN dout[207]
    DIRECTION OUTPUT ;
    USE SIGNAL ;
    PORT
      LAYER M7 ;
        RECT  14.656 75.931 14.688 76 ;
    END
  END dout[207]
  PIN dout[208]
    DIRECTION OUTPUT ;
    USE SIGNAL ;
    PORT
      LAYER M7 ;
        RECT  5.824 75.931 5.856 76 ;
    END
  END dout[208]
  PIN dout[209]
    DIRECTION OUTPUT ;
    USE SIGNAL ;
    PORT
      LAYER M7 ;
        RECT  14.848 75.931 14.88 76 ;
    END
  END dout[209]
  PIN dout[20]
    DIRECTION OUTPUT ;
    USE SIGNAL ;
    PORT
      LAYER M5 ;
        RECT  37.824 75.916 37.848 76 ;
    END
  END dout[20]
  PIN dout[210]
    DIRECTION OUTPUT ;
    USE SIGNAL ;
    PORT
      LAYER M7 ;
        RECT  3.712 75.931 3.744 76 ;
    END
  END dout[210]
  PIN dout[211]
    DIRECTION OUTPUT ;
    USE SIGNAL ;
    PORT
      LAYER M5 ;
        RECT  10.368 75.916 10.392 76 ;
    END
  END dout[211]
  PIN dout[212]
    DIRECTION OUTPUT ;
    USE SIGNAL ;
    PORT
      LAYER M7 ;
        RECT  12.16 75.931 12.192 76 ;
    END
  END dout[212]
  PIN dout[213]
    DIRECTION OUTPUT ;
    USE SIGNAL ;
    PORT
      LAYER M5 ;
        RECT  10.032 75.916 10.056 76 ;
    END
  END dout[213]
  PIN dout[214]
    DIRECTION OUTPUT ;
    USE SIGNAL ;
    PORT
      LAYER M7 ;
        RECT  10.816 75.931 10.848 76 ;
    END
  END dout[214]
  PIN dout[215]
    DIRECTION OUTPUT ;
    USE SIGNAL ;
    PORT
      LAYER M5 ;
        RECT  7.776 75.916 7.8 76 ;
    END
  END dout[215]
  PIN dout[216]
    DIRECTION OUTPUT ;
    USE SIGNAL ;
    PORT
      LAYER M5 ;
        RECT  29.184 75.916 29.208 76 ;
    END
  END dout[216]
  PIN dout[217]
    DIRECTION OUTPUT ;
    USE SIGNAL ;
    PORT
      LAYER M5 ;
        RECT  10.752 75.916 10.776 76 ;
    END
  END dout[217]
  PIN dout[218]
    DIRECTION OUTPUT ;
    USE SIGNAL ;
    PORT
      LAYER M7 ;
        RECT  24.768 75.931 24.8 76 ;
    END
  END dout[218]
  PIN dout[219]
    DIRECTION OUTPUT ;
    USE SIGNAL ;
    PORT
      LAYER M5 ;
        RECT  18 75.916 18.024 76 ;
    END
  END dout[219]
  PIN dout[21]
    DIRECTION OUTPUT ;
    USE SIGNAL ;
    PORT
      LAYER M7 ;
        RECT  38.528 75.931 38.56 76 ;
    END
  END dout[21]
  PIN dout[220]
    DIRECTION OUTPUT ;
    USE SIGNAL ;
    PORT
      LAYER M5 ;
        RECT  16.8 75.916 16.824 76 ;
    END
  END dout[220]
  PIN dout[221]
    DIRECTION OUTPUT ;
    USE SIGNAL ;
    PORT
      LAYER M7 ;
        RECT  11.264 75.931 11.296 76 ;
    END
  END dout[221]
  PIN dout[222]
    DIRECTION OUTPUT ;
    USE SIGNAL ;
    PORT
      LAYER M5 ;
        RECT  32.976 75.916 33 76 ;
    END
  END dout[222]
  PIN dout[223]
    DIRECTION OUTPUT ;
    USE SIGNAL ;
    PORT
      LAYER M7 ;
        RECT  14.144 75.931 14.176 76 ;
    END
  END dout[223]
  PIN dout[224]
    DIRECTION OUTPUT ;
    USE SIGNAL ;
    PORT
      LAYER M5 ;
        RECT  18.96 75.916 18.984 76 ;
    END
  END dout[224]
  PIN dout[225]
    DIRECTION OUTPUT ;
    USE SIGNAL ;
    PORT
      LAYER M5 ;
        RECT  31.968 75.916 31.992 76 ;
    END
  END dout[225]
  PIN dout[226]
    DIRECTION OUTPUT ;
    USE SIGNAL ;
    PORT
      LAYER M5 ;
        RECT  28.608 75.916 28.632 76 ;
    END
  END dout[226]
  PIN dout[227]
    DIRECTION OUTPUT ;
    USE SIGNAL ;
    PORT
      LAYER M5 ;
        RECT  15.936 75.916 15.96 76 ;
    END
  END dout[227]
  PIN dout[228]
    DIRECTION OUTPUT ;
    USE SIGNAL ;
    PORT
      LAYER M5 ;
        RECT  18.192 75.916 18.216 76 ;
    END
  END dout[228]
  PIN dout[229]
    DIRECTION OUTPUT ;
    USE SIGNAL ;
    PORT
      LAYER M5 ;
        RECT  30.432 75.916 30.456 76 ;
    END
  END dout[229]
  PIN dout[22]
    DIRECTION OUTPUT ;
    USE SIGNAL ;
    PORT
      LAYER M5 ;
        RECT  36.96 75.916 36.984 76 ;
    END
  END dout[22]
  PIN dout[230]
    DIRECTION OUTPUT ;
    USE SIGNAL ;
    PORT
      LAYER M5 ;
        RECT  20.784 75.916 20.808 76 ;
    END
  END dout[230]
  PIN dout[231]
    DIRECTION OUTPUT ;
    USE SIGNAL ;
    PORT
      LAYER M5 ;
        RECT  27.648 75.916 27.672 76 ;
    END
  END dout[231]
  PIN dout[232]
    DIRECTION OUTPUT ;
    USE SIGNAL ;
    PORT
      LAYER M5 ;
        RECT  30.816 75.916 30.84 76 ;
    END
  END dout[232]
  PIN dout[233]
    DIRECTION OUTPUT ;
    USE SIGNAL ;
    PORT
      LAYER M5 ;
        RECT  31.152 75.916 31.176 76 ;
    END
  END dout[233]
  PIN dout[234]
    DIRECTION OUTPUT ;
    USE SIGNAL ;
    PORT
      LAYER M5 ;
        RECT  20.112 75.916 20.136 76 ;
    END
  END dout[234]
  PIN dout[235]
    DIRECTION OUTPUT ;
    USE SIGNAL ;
    PORT
      LAYER M7 ;
        RECT  14.272 75.931 14.304 76 ;
    END
  END dout[235]
  PIN dout[236]
    DIRECTION OUTPUT ;
    USE SIGNAL ;
    PORT
      LAYER M5 ;
        RECT  18.096 75.916 18.12 76 ;
    END
  END dout[236]
  PIN dout[237]
    DIRECTION OUTPUT ;
    USE SIGNAL ;
    PORT
      LAYER M7 ;
        RECT  25.088 75.931 25.12 76 ;
    END
  END dout[237]
  PIN dout[238]
    DIRECTION OUTPUT ;
    USE SIGNAL ;
    PORT
      LAYER M5 ;
        RECT  28.944 75.916 28.968 76 ;
    END
  END dout[238]
  PIN dout[239]
    DIRECTION OUTPUT ;
    USE SIGNAL ;
    PORT
      LAYER M5 ;
        RECT  28.704 75.916 28.728 76 ;
    END
  END dout[239]
  PIN dout[23]
    DIRECTION OUTPUT ;
    USE SIGNAL ;
    PORT
      LAYER M5 ;
        RECT  35.232 75.916 35.256 76 ;
    END
  END dout[23]
  PIN dout[240]
    DIRECTION OUTPUT ;
    USE SIGNAL ;
    PORT
      LAYER M7 ;
        RECT  23.296 75.931 23.328 76 ;
    END
  END dout[240]
  PIN dout[241]
    DIRECTION OUTPUT ;
    USE SIGNAL ;
    PORT
      LAYER M5 ;
        RECT  33.648 75.916 33.672 76 ;
    END
  END dout[241]
  PIN dout[242]
    DIRECTION OUTPUT ;
    USE SIGNAL ;
    PORT
      LAYER M7 ;
        RECT  22.336 75.931 22.368 76 ;
    END
  END dout[242]
  PIN dout[243]
    DIRECTION OUTPUT ;
    USE SIGNAL ;
    PORT
      LAYER M5 ;
        RECT  19.776 75.916 19.8 76 ;
    END
  END dout[243]
  PIN dout[244]
    DIRECTION OUTPUT ;
    USE SIGNAL ;
    PORT
      LAYER M7 ;
        RECT  22.528 75.931 22.56 76 ;
    END
  END dout[244]
  PIN dout[245]
    DIRECTION OUTPUT ;
    USE SIGNAL ;
    PORT
      LAYER M5 ;
        RECT  21.84 75.916 21.864 76 ;
    END
  END dout[245]
  PIN dout[246]
    DIRECTION OUTPUT ;
    USE SIGNAL ;
    PORT
      LAYER M7 ;
        RECT  26.496 75.931 26.528 76 ;
    END
  END dout[246]
  PIN dout[247]
    DIRECTION OUTPUT ;
    USE SIGNAL ;
    PORT
      LAYER M5 ;
        RECT  33.312 75.916 33.336 76 ;
    END
  END dout[247]
  PIN dout[248]
    DIRECTION OUTPUT ;
    USE SIGNAL ;
    PORT
      LAYER M5 ;
        RECT  30.288 75.916 30.312 76 ;
    END
  END dout[248]
  PIN dout[249]
    DIRECTION OUTPUT ;
    USE SIGNAL ;
    PORT
      LAYER M5 ;
        RECT  17.712 75.916 17.736 76 ;
    END
  END dout[249]
  PIN dout[24]
    DIRECTION OUTPUT ;
    USE SIGNAL ;
    PORT
      LAYER M5 ;
        RECT  32.928 75.916 32.952 76 ;
    END
  END dout[24]
  PIN dout[250]
    DIRECTION OUTPUT ;
    USE SIGNAL ;
    PORT
      LAYER M7 ;
        RECT  25.664 75.931 25.696 76 ;
    END
  END dout[250]
  PIN dout[251]
    DIRECTION OUTPUT ;
    USE SIGNAL ;
    PORT
      LAYER M7 ;
        RECT  13.632 75.931 13.664 76 ;
    END
  END dout[251]
  PIN dout[252]
    DIRECTION OUTPUT ;
    USE SIGNAL ;
    PORT
      LAYER M7 ;
        RECT  22.208 75.931 22.24 76 ;
    END
  END dout[252]
  PIN dout[253]
    DIRECTION OUTPUT ;
    USE SIGNAL ;
    PORT
      LAYER M7 ;
        RECT  13.056 75.931 13.088 76 ;
    END
  END dout[253]
  PIN dout[254]
    DIRECTION OUTPUT ;
    USE SIGNAL ;
    PORT
      LAYER M7 ;
        RECT  11.008 75.931 11.04 76 ;
    END
  END dout[254]
  PIN dout[255]
    DIRECTION OUTPUT ;
    USE SIGNAL ;
    PORT
      LAYER M5 ;
        RECT  16.608 75.916 16.632 76 ;
    END
  END dout[255]
  PIN dout[256]
    DIRECTION OUTPUT ;
    USE SIGNAL ;
    PORT
      LAYER M5 ;
        RECT  57.552 75.916 57.576 76 ;
    END
  END dout[256]
  PIN dout[257]
    DIRECTION OUTPUT ;
    USE SIGNAL ;
    PORT
      LAYER M5 ;
        RECT  58.704 75.916 58.728 76 ;
    END
  END dout[257]
  PIN dout[258]
    DIRECTION OUTPUT ;
    USE SIGNAL ;
    PORT
      LAYER M5 ;
        RECT  59.424 75.916 59.448 76 ;
    END
  END dout[258]
  PIN dout[259]
    DIRECTION OUTPUT ;
    USE SIGNAL ;
    PORT
      LAYER M5 ;
        RECT  58.896 75.916 58.92 76 ;
    END
  END dout[259]
  PIN dout[25]
    DIRECTION OUTPUT ;
    USE SIGNAL ;
    PORT
      LAYER M7 ;
        RECT  38.592 75.931 38.624 76 ;
    END
  END dout[25]
  PIN dout[260]
    DIRECTION OUTPUT ;
    USE SIGNAL ;
    PORT
      LAYER M5 ;
        RECT  57.216 75.916 57.24 76 ;
    END
  END dout[260]
  PIN dout[261]
    DIRECTION OUTPUT ;
    USE SIGNAL ;
    PORT
      LAYER M5 ;
        RECT  56.448 75.916 56.472 76 ;
    END
  END dout[261]
  PIN dout[262]
    DIRECTION OUTPUT ;
    USE SIGNAL ;
    PORT
      LAYER M5 ;
        RECT  56.688 75.916 56.712 76 ;
    END
  END dout[262]
  PIN dout[263]
    DIRECTION OUTPUT ;
    USE SIGNAL ;
    PORT
      LAYER M5 ;
        RECT  56.64 75.916 56.664 76 ;
    END
  END dout[263]
  PIN dout[264]
    DIRECTION OUTPUT ;
    USE SIGNAL ;
    PORT
      LAYER M5 ;
        RECT  48.048 75.916 48.072 76 ;
    END
  END dout[264]
  PIN dout[265]
    DIRECTION OUTPUT ;
    USE SIGNAL ;
    PORT
      LAYER M5 ;
        RECT  58.128 75.916 58.152 76 ;
    END
  END dout[265]
  PIN dout[266]
    DIRECTION OUTPUT ;
    USE SIGNAL ;
    PORT
      LAYER M7 ;
        RECT  52.288 75.931 52.32 76 ;
    END
  END dout[266]
  PIN dout[267]
    DIRECTION OUTPUT ;
    USE SIGNAL ;
    PORT
      LAYER M5 ;
        RECT  55.152 75.916 55.176 76 ;
    END
  END dout[267]
  PIN dout[268]
    DIRECTION OUTPUT ;
    USE SIGNAL ;
    PORT
      LAYER M5 ;
        RECT  56.976 75.916 57 76 ;
    END
  END dout[268]
  PIN dout[269]
    DIRECTION OUTPUT ;
    USE SIGNAL ;
    PORT
      LAYER M5 ;
        RECT  56.112 75.916 56.136 76 ;
    END
  END dout[269]
  PIN dout[26]
    DIRECTION OUTPUT ;
    USE SIGNAL ;
    PORT
      LAYER M5 ;
        RECT  30.72 75.916 30.744 76 ;
    END
  END dout[26]
  PIN dout[270]
    DIRECTION OUTPUT ;
    USE SIGNAL ;
    PORT
      LAYER M5 ;
        RECT  56.064 75.916 56.088 76 ;
    END
  END dout[270]
  PIN dout[271]
    DIRECTION OUTPUT ;
    USE SIGNAL ;
    PORT
      LAYER M7 ;
        RECT  51.456 75.931 51.488 76 ;
    END
  END dout[271]
  PIN dout[272]
    DIRECTION OUTPUT ;
    USE SIGNAL ;
    PORT
      LAYER M7 ;
        RECT  53.952 75.931 53.984 76 ;
    END
  END dout[272]
  PIN dout[273]
    DIRECTION OUTPUT ;
    USE SIGNAL ;
    PORT
      LAYER M5 ;
        RECT  57.648 75.916 57.672 76 ;
    END
  END dout[273]
  PIN dout[274]
    DIRECTION OUTPUT ;
    USE SIGNAL ;
    PORT
      LAYER M5 ;
        RECT  56.88 75.916 56.904 76 ;
    END
  END dout[274]
  PIN dout[275]
    DIRECTION OUTPUT ;
    USE SIGNAL ;
    PORT
      LAYER M5 ;
        RECT  48.528 75.916 48.552 76 ;
    END
  END dout[275]
  PIN dout[276]
    DIRECTION OUTPUT ;
    USE SIGNAL ;
    PORT
      LAYER M5 ;
        RECT  58.176 75.916 58.2 76 ;
    END
  END dout[276]
  PIN dout[277]
    DIRECTION OUTPUT ;
    USE SIGNAL ;
    PORT
      LAYER M5 ;
        RECT  45.264 75.916 45.288 76 ;
    END
  END dout[277]
  PIN dout[278]
    DIRECTION OUTPUT ;
    USE SIGNAL ;
    PORT
      LAYER M5 ;
        RECT  46.704 75.916 46.728 76 ;
    END
  END dout[278]
  PIN dout[279]
    DIRECTION OUTPUT ;
    USE SIGNAL ;
    PORT
      LAYER M5 ;
        RECT  55.296 75.916 55.32 76 ;
    END
  END dout[279]
  PIN dout[27]
    DIRECTION OUTPUT ;
    USE SIGNAL ;
    PORT
      LAYER M5 ;
        RECT  34.656 75.916 34.68 76 ;
    END
  END dout[27]
  PIN dout[280]
    DIRECTION OUTPUT ;
    USE SIGNAL ;
    PORT
      LAYER M7 ;
        RECT  49.664 75.931 49.696 76 ;
    END
  END dout[280]
  PIN dout[281]
    DIRECTION OUTPUT ;
    USE SIGNAL ;
    PORT
      LAYER M5 ;
        RECT  58.416 75.916 58.44 76 ;
    END
  END dout[281]
  PIN dout[282]
    DIRECTION OUTPUT ;
    USE SIGNAL ;
    PORT
      LAYER M7 ;
        RECT  50.112 75.931 50.144 76 ;
    END
  END dout[282]
  PIN dout[283]
    DIRECTION OUTPUT ;
    USE SIGNAL ;
    PORT
      LAYER M5 ;
        RECT  45.504 75.916 45.528 76 ;
    END
  END dout[283]
  PIN dout[284]
    DIRECTION OUTPUT ;
    USE SIGNAL ;
    PORT
      LAYER M5 ;
        RECT  43.344 75.916 43.368 76 ;
    END
  END dout[284]
  PIN dout[285]
    DIRECTION OUTPUT ;
    USE SIGNAL ;
    PORT
      LAYER M5 ;
        RECT  48.96 75.916 48.984 76 ;
    END
  END dout[285]
  PIN dout[286]
    DIRECTION OUTPUT ;
    USE SIGNAL ;
    PORT
      LAYER M7 ;
        RECT  53.12 75.931 53.152 76 ;
    END
  END dout[286]
  PIN dout[287]
    DIRECTION OUTPUT ;
    USE SIGNAL ;
    PORT
      LAYER M7 ;
        RECT  24 75.931 24.032 76 ;
    END
  END dout[287]
  PIN dout[288]
    DIRECTION OUTPUT ;
    USE SIGNAL ;
    PORT
      LAYER M5 ;
        RECT  31.536 75.916 31.56 76 ;
    END
  END dout[288]
  PIN dout[289]
    DIRECTION OUTPUT ;
    USE SIGNAL ;
    PORT
      LAYER M7 ;
        RECT  51.072 75.931 51.104 76 ;
    END
  END dout[289]
  PIN dout[28]
    DIRECTION OUTPUT ;
    USE SIGNAL ;
    PORT
      LAYER M5 ;
        RECT  29.232 75.916 29.256 76 ;
    END
  END dout[28]
  PIN dout[290]
    DIRECTION OUTPUT ;
    USE SIGNAL ;
    PORT
      LAYER M5 ;
        RECT  58.656 75.916 58.68 76 ;
    END
  END dout[290]
  PIN dout[291]
    DIRECTION OUTPUT ;
    USE SIGNAL ;
    PORT
      LAYER M5 ;
        RECT  59.184 75.916 59.208 76 ;
    END
  END dout[291]
  PIN dout[292]
    DIRECTION OUTPUT ;
    USE SIGNAL ;
    PORT
      LAYER M5 ;
        RECT  58.56 75.916 58.584 76 ;
    END
  END dout[292]
  PIN dout[293]
    DIRECTION OUTPUT ;
    USE SIGNAL ;
    PORT
      LAYER M7 ;
        RECT  53.568 75.931 53.6 76 ;
    END
  END dout[293]
  PIN dout[294]
    DIRECTION OUTPUT ;
    USE SIGNAL ;
    PORT
      LAYER M5 ;
        RECT  55.872 75.916 55.896 76 ;
    END
  END dout[294]
  PIN dout[295]
    DIRECTION OUTPUT ;
    USE SIGNAL ;
    PORT
      LAYER M7 ;
        RECT  39.296 75.931 39.328 76 ;
    END
  END dout[295]
  PIN dout[296]
    DIRECTION OUTPUT ;
    USE SIGNAL ;
    PORT
      LAYER M7 ;
        RECT  23.04 75.931 23.072 76 ;
    END
  END dout[296]
  PIN dout[297]
    DIRECTION OUTPUT ;
    USE SIGNAL ;
    PORT
      LAYER M5 ;
        RECT  58.08 75.916 58.104 76 ;
    END
  END dout[297]
  PIN dout[298]
    DIRECTION OUTPUT ;
    USE SIGNAL ;
    PORT
      LAYER M5 ;
        RECT  59.136 75.916 59.16 76 ;
    END
  END dout[298]
  PIN dout[299]
    DIRECTION OUTPUT ;
    USE SIGNAL ;
    PORT
      LAYER M5 ;
        RECT  57.696 75.916 57.72 76 ;
    END
  END dout[299]
  PIN dout[29]
    DIRECTION OUTPUT ;
    USE SIGNAL ;
    PORT
      LAYER M5 ;
        RECT  27.072 75.916 27.096 76 ;
    END
  END dout[29]
  PIN dout[2]
    DIRECTION OUTPUT ;
    USE SIGNAL ;
    PORT
      LAYER M7 ;
        RECT  14.976 75.931 15.008 76 ;
    END
  END dout[2]
  PIN dout[300]
    DIRECTION OUTPUT ;
    USE SIGNAL ;
    PORT
      LAYER M5 ;
        RECT  55.968 75.916 55.992 76 ;
    END
  END dout[300]
  PIN dout[301]
    DIRECTION OUTPUT ;
    USE SIGNAL ;
    PORT
      LAYER M5 ;
        RECT  58.272 75.916 58.296 76 ;
    END
  END dout[301]
  PIN dout[302]
    DIRECTION OUTPUT ;
    USE SIGNAL ;
    PORT
      LAYER M5 ;
        RECT  57.312 75.916 57.336 76 ;
    END
  END dout[302]
  PIN dout[303]
    DIRECTION OUTPUT ;
    USE SIGNAL ;
    PORT
      LAYER M5 ;
        RECT  58.8 75.916 58.824 76 ;
    END
  END dout[303]
  PIN dout[304]
    DIRECTION OUTPUT ;
    USE SIGNAL ;
    PORT
      LAYER M5 ;
        RECT  19.872 75.916 19.896 76 ;
    END
  END dout[304]
  PIN dout[305]
    DIRECTION OUTPUT ;
    USE SIGNAL ;
    PORT
      LAYER M5 ;
        RECT  9.888 75.916 9.912 76 ;
    END
  END dout[305]
  PIN dout[306]
    DIRECTION OUTPUT ;
    USE SIGNAL ;
    PORT
      LAYER M5 ;
        RECT  27.408 75.916 27.432 76 ;
    END
  END dout[306]
  PIN dout[307]
    DIRECTION OUTPUT ;
    USE SIGNAL ;
    PORT
      LAYER M5 ;
        RECT  16.224 75.916 16.248 76 ;
    END
  END dout[307]
  PIN dout[308]
    DIRECTION OUTPUT ;
    USE SIGNAL ;
    PORT
      LAYER M7 ;
        RECT  13.888 75.931 13.92 76 ;
    END
  END dout[308]
  PIN dout[309]
    DIRECTION OUTPUT ;
    USE SIGNAL ;
    PORT
      LAYER M5 ;
        RECT  57.888 75.916 57.912 76 ;
    END
  END dout[309]
  PIN dout[30]
    DIRECTION OUTPUT ;
    USE SIGNAL ;
    PORT
      LAYER M5 ;
        RECT  27.12 75.916 27.144 76 ;
    END
  END dout[30]
  PIN dout[310]
    DIRECTION OUTPUT ;
    USE SIGNAL ;
    PORT
      LAYER M7 ;
        RECT  23.424 75.931 23.456 76 ;
    END
  END dout[310]
  PIN dout[311]
    DIRECTION OUTPUT ;
    USE SIGNAL ;
    PORT
      LAYER M7 ;
        RECT  22.08 75.931 22.112 76 ;
    END
  END dout[311]
  PIN dout[312]
    DIRECTION OUTPUT ;
    USE SIGNAL ;
    PORT
      LAYER M7 ;
        RECT  24.96 75.931 24.992 76 ;
    END
  END dout[312]
  PIN dout[313]
    DIRECTION OUTPUT ;
    USE SIGNAL ;
    PORT
      LAYER M5 ;
        RECT  34.128 75.916 34.152 76 ;
    END
  END dout[313]
  PIN dout[314]
    DIRECTION OUTPUT ;
    USE SIGNAL ;
    PORT
      LAYER M7 ;
        RECT  53.44 75.931 53.472 76 ;
    END
  END dout[314]
  PIN dout[315]
    DIRECTION OUTPUT ;
    USE SIGNAL ;
    PORT
      LAYER M5 ;
        RECT  55.728 75.916 55.752 76 ;
    END
  END dout[315]
  PIN dout[316]
    DIRECTION OUTPUT ;
    USE SIGNAL ;
    PORT
      LAYER M7 ;
        RECT  51.968 75.931 52 76 ;
    END
  END dout[316]
  PIN dout[317]
    DIRECTION OUTPUT ;
    USE SIGNAL ;
    PORT
      LAYER M7 ;
        RECT  38.976 75.931 39.008 76 ;
    END
  END dout[317]
  PIN dout[318]
    DIRECTION OUTPUT ;
    USE SIGNAL ;
    PORT
      LAYER M5 ;
        RECT  56.544 75.916 56.568 76 ;
    END
  END dout[318]
  PIN dout[319]
    DIRECTION OUTPUT ;
    USE SIGNAL ;
    PORT
      LAYER M7 ;
        RECT  22.4 75.931 22.432 76 ;
    END
  END dout[319]
  PIN dout[31]
    DIRECTION OUTPUT ;
    USE SIGNAL ;
    PORT
      LAYER M7 ;
        RECT  23.616 75.931 23.648 76 ;
    END
  END dout[31]
  PIN dout[320]
    DIRECTION OUTPUT ;
    USE SIGNAL ;
    PORT
      LAYER M5 ;
        RECT  102.384 75.916 102.408 76 ;
    END
  END dout[320]
  PIN dout[321]
    DIRECTION OUTPUT ;
    USE SIGNAL ;
    PORT
      LAYER M5 ;
        RECT  108.96 75.916 108.984 76 ;
    END
  END dout[321]
  PIN dout[322]
    DIRECTION OUTPUT ;
    USE SIGNAL ;
    PORT
      LAYER M5 ;
        RECT  106.944 75.916 106.968 76 ;
    END
  END dout[322]
  PIN dout[323]
    DIRECTION OUTPUT ;
    USE SIGNAL ;
    PORT
      LAYER M5 ;
        RECT  108.192 75.916 108.216 76 ;
    END
  END dout[323]
  PIN dout[324]
    DIRECTION OUTPUT ;
    USE SIGNAL ;
    PORT
      LAYER M5 ;
        RECT  102.672 75.916 102.696 76 ;
    END
  END dout[324]
  PIN dout[325]
    DIRECTION OUTPUT ;
    USE SIGNAL ;
    PORT
      LAYER M5 ;
        RECT  109.2 75.916 109.224 76 ;
    END
  END dout[325]
  PIN dout[326]
    DIRECTION OUTPUT ;
    USE SIGNAL ;
    PORT
      LAYER M5 ;
        RECT  97.056 75.916 97.08 76 ;
    END
  END dout[326]
  PIN dout[327]
    DIRECTION OUTPUT ;
    USE SIGNAL ;
    PORT
      LAYER M5 ;
        RECT  99.744 75.916 99.768 76 ;
    END
  END dout[327]
  PIN dout[328]
    DIRECTION OUTPUT ;
    USE SIGNAL ;
    PORT
      LAYER M5 ;
        RECT  104.832 75.916 104.856 76 ;
    END
  END dout[328]
  PIN dout[329]
    DIRECTION OUTPUT ;
    USE SIGNAL ;
    PORT
      LAYER M5 ;
        RECT  104.688 75.916 104.712 76 ;
    END
  END dout[329]
  PIN dout[32]
    DIRECTION OUTPUT ;
    USE SIGNAL ;
    PORT
      LAYER M5 ;
        RECT  33.504 75.916 33.528 76 ;
    END
  END dout[32]
  PIN dout[330]
    DIRECTION OUTPUT ;
    USE SIGNAL ;
    PORT
      LAYER M5 ;
        RECT  102.48 75.916 102.504 76 ;
    END
  END dout[330]
  PIN dout[331]
    DIRECTION OUTPUT ;
    USE SIGNAL ;
    PORT
      LAYER M5 ;
        RECT  106.224 75.916 106.248 76 ;
    END
  END dout[331]
  PIN dout[332]
    DIRECTION OUTPUT ;
    USE SIGNAL ;
    PORT
      LAYER M5 ;
        RECT  100.896 75.916 100.92 76 ;
    END
  END dout[332]
  PIN dout[333]
    DIRECTION OUTPUT ;
    USE SIGNAL ;
    PORT
      LAYER M5 ;
        RECT  102.336 75.916 102.36 76 ;
    END
  END dout[333]
  PIN dout[334]
    DIRECTION OUTPUT ;
    USE SIGNAL ;
    PORT
      LAYER M5 ;
        RECT  103.872 75.916 103.896 76 ;
    END
  END dout[334]
  PIN dout[335]
    DIRECTION OUTPUT ;
    USE SIGNAL ;
    PORT
      LAYER M5 ;
        RECT  108.816 75.916 108.84 76 ;
    END
  END dout[335]
  PIN dout[336]
    DIRECTION OUTPUT ;
    USE SIGNAL ;
    PORT
      LAYER M5 ;
        RECT  99.984 75.916 100.008 76 ;
    END
  END dout[336]
  PIN dout[337]
    DIRECTION OUTPUT ;
    USE SIGNAL ;
    PORT
      LAYER M5 ;
        RECT  101.952 75.916 101.976 76 ;
    END
  END dout[337]
  PIN dout[338]
    DIRECTION OUTPUT ;
    USE SIGNAL ;
    PORT
      LAYER M5 ;
        RECT  102.816 75.916 102.84 76 ;
    END
  END dout[338]
  PIN dout[339]
    DIRECTION OUTPUT ;
    USE SIGNAL ;
    PORT
      LAYER M5 ;
        RECT  95.232 75.916 95.256 76 ;
    END
  END dout[339]
  PIN dout[33]
    DIRECTION OUTPUT ;
    USE SIGNAL ;
    PORT
      LAYER M5 ;
        RECT  2.88 75.916 2.904 76 ;
    END
  END dout[33]
  PIN dout[340]
    DIRECTION OUTPUT ;
    USE SIGNAL ;
    PORT
      LAYER M5 ;
        RECT  98.352 75.916 98.376 76 ;
    END
  END dout[340]
  PIN dout[341]
    DIRECTION OUTPUT ;
    USE SIGNAL ;
    PORT
      LAYER M5 ;
        RECT  96.72 75.916 96.744 76 ;
    END
  END dout[341]
  PIN dout[342]
    DIRECTION OUTPUT ;
    USE SIGNAL ;
    PORT
      LAYER M5 ;
        RECT  108.528 75.916 108.552 76 ;
    END
  END dout[342]
  PIN dout[343]
    DIRECTION OUTPUT ;
    USE SIGNAL ;
    PORT
      LAYER M7 ;
        RECT  99.84 75.931 99.872 76 ;
    END
  END dout[343]
  PIN dout[344]
    DIRECTION OUTPUT ;
    USE SIGNAL ;
    PORT
      LAYER M5 ;
        RECT  107.424 75.916 107.448 76 ;
    END
  END dout[344]
  PIN dout[345]
    DIRECTION OUTPUT ;
    USE SIGNAL ;
    PORT
      LAYER M5 ;
        RECT  106.128 75.916 106.152 76 ;
    END
  END dout[345]
  PIN dout[346]
    DIRECTION OUTPUT ;
    USE SIGNAL ;
    PORT
      LAYER M5 ;
        RECT  107.808 75.916 107.832 76 ;
    END
  END dout[346]
  PIN dout[347]
    DIRECTION OUTPUT ;
    USE SIGNAL ;
    PORT
      LAYER M5 ;
        RECT  108.432 75.916 108.456 76 ;
    END
  END dout[347]
  PIN dout[348]
    DIRECTION OUTPUT ;
    USE SIGNAL ;
    PORT
      LAYER M5 ;
        RECT  107.904 75.916 107.928 76 ;
    END
  END dout[348]
  PIN dout[349]
    DIRECTION OUTPUT ;
    USE SIGNAL ;
    PORT
      LAYER M7 ;
        RECT  101.824 75.931 101.856 76 ;
    END
  END dout[349]
  PIN dout[34]
    DIRECTION OUTPUT ;
    USE SIGNAL ;
    PORT
      LAYER M7 ;
        RECT  11.712 75.931 11.744 76 ;
    END
  END dout[34]
  PIN dout[350]
    DIRECTION OUTPUT ;
    USE SIGNAL ;
    PORT
      LAYER M7 ;
        RECT  99.52 75.931 99.552 76 ;
    END
  END dout[350]
  PIN dout[351]
    DIRECTION OUTPUT ;
    USE SIGNAL ;
    PORT
      LAYER M7 ;
        RECT  102.528 75.931 102.56 76 ;
    END
  END dout[351]
  PIN dout[352]
    DIRECTION OUTPUT ;
    USE SIGNAL ;
    PORT
      LAYER M5 ;
        RECT  95.952 75.916 95.976 76 ;
    END
  END dout[352]
  PIN dout[353]
    DIRECTION OUTPUT ;
    USE SIGNAL ;
    PORT
      LAYER M5 ;
        RECT  100.848 75.916 100.872 76 ;
    END
  END dout[353]
  PIN dout[354]
    DIRECTION OUTPUT ;
    USE SIGNAL ;
    PORT
      LAYER M7 ;
        RECT  100.928 75.931 100.96 76 ;
    END
  END dout[354]
  PIN dout[355]
    DIRECTION OUTPUT ;
    USE SIGNAL ;
    PORT
      LAYER M5 ;
        RECT  98.112 75.916 98.136 76 ;
    END
  END dout[355]
  PIN dout[356]
    DIRECTION OUTPUT ;
    USE SIGNAL ;
    PORT
      LAYER M5 ;
        RECT  96.624 75.916 96.648 76 ;
    END
  END dout[356]
  PIN dout[357]
    DIRECTION OUTPUT ;
    USE SIGNAL ;
    PORT
      LAYER M7 ;
        RECT  101.952 75.931 101.984 76 ;
    END
  END dout[357]
  PIN dout[358]
    DIRECTION OUTPUT ;
    USE SIGNAL ;
    PORT
      LAYER M7 ;
        RECT  100.096 75.931 100.128 76 ;
    END
  END dout[358]
  PIN dout[359]
    DIRECTION OUTPUT ;
    USE SIGNAL ;
    PORT
      LAYER M7 ;
        RECT  103.488 75.931 103.52 76 ;
    END
  END dout[359]
  PIN dout[35]
    DIRECTION OUTPUT ;
    USE SIGNAL ;
    PORT
      LAYER M7 ;
        RECT  24.32 75.931 24.352 76 ;
    END
  END dout[35]
  PIN dout[360]
    DIRECTION OUTPUT ;
    USE SIGNAL ;
    PORT
      LAYER M7 ;
        RECT  103.68 75.931 103.712 76 ;
    END
  END dout[360]
  PIN dout[361]
    DIRECTION OUTPUT ;
    USE SIGNAL ;
    PORT
      LAYER M5 ;
        RECT  103.44 75.916 103.464 76 ;
    END
  END dout[361]
  PIN dout[362]
    DIRECTION OUTPUT ;
    USE SIGNAL ;
    PORT
      LAYER M5 ;
        RECT  98.16 75.916 98.184 76 ;
    END
  END dout[362]
  PIN dout[363]
    DIRECTION OUTPUT ;
    USE SIGNAL ;
    PORT
      LAYER M7 ;
        RECT  90.112 75.931 90.144 76 ;
    END
  END dout[363]
  PIN dout[364]
    DIRECTION OUTPUT ;
    USE SIGNAL ;
    PORT
      LAYER M5 ;
        RECT  94.032 75.916 94.056 76 ;
    END
  END dout[364]
  PIN dout[365]
    DIRECTION OUTPUT ;
    USE SIGNAL ;
    PORT
      LAYER M7 ;
        RECT  99.392 75.931 99.424 76 ;
    END
  END dout[365]
  PIN dout[366]
    DIRECTION OUTPUT ;
    USE SIGNAL ;
    PORT
      LAYER M5 ;
        RECT  101.808 75.916 101.832 76 ;
    END
  END dout[366]
  PIN dout[367]
    DIRECTION OUTPUT ;
    USE SIGNAL ;
    PORT
      LAYER M7 ;
        RECT  99.968 75.931 100 76 ;
    END
  END dout[367]
  PIN dout[368]
    DIRECTION OUTPUT ;
    USE SIGNAL ;
    PORT
      LAYER M5 ;
        RECT  105.792 75.916 105.816 76 ;
    END
  END dout[368]
  PIN dout[369]
    DIRECTION OUTPUT ;
    USE SIGNAL ;
    PORT
      LAYER M5 ;
        RECT  104.544 75.916 104.568 76 ;
    END
  END dout[369]
  PIN dout[36]
    DIRECTION OUTPUT ;
    USE SIGNAL ;
    PORT
      LAYER M5 ;
        RECT  16.56 75.916 16.584 76 ;
    END
  END dout[36]
  PIN dout[370]
    DIRECTION OUTPUT ;
    USE SIGNAL ;
    PORT
      LAYER M5 ;
        RECT  108.288 75.916 108.312 76 ;
    END
  END dout[370]
  PIN dout[371]
    DIRECTION OUTPUT ;
    USE SIGNAL ;
    PORT
      LAYER M5 ;
        RECT  108.672 75.916 108.696 76 ;
    END
  END dout[371]
  PIN dout[372]
    DIRECTION OUTPUT ;
    USE SIGNAL ;
    PORT
      LAYER M5 ;
        RECT  100.32 75.916 100.344 76 ;
    END
  END dout[372]
  PIN dout[373]
    DIRECTION OUTPUT ;
    USE SIGNAL ;
    PORT
      LAYER M5 ;
        RECT  100.08 75.916 100.104 76 ;
    END
  END dout[373]
  PIN dout[374]
    DIRECTION OUTPUT ;
    USE SIGNAL ;
    PORT
      LAYER M5 ;
        RECT  103.104 75.916 103.128 76 ;
    END
  END dout[374]
  PIN dout[375]
    DIRECTION OUTPUT ;
    USE SIGNAL ;
    PORT
      LAYER M5 ;
        RECT  102.72 75.916 102.744 76 ;
    END
  END dout[375]
  PIN dout[376]
    DIRECTION OUTPUT ;
    USE SIGNAL ;
    PORT
      LAYER M5 ;
        RECT  106.656 75.916 106.68 76 ;
    END
  END dout[376]
  PIN dout[377]
    DIRECTION OUTPUT ;
    USE SIGNAL ;
    PORT
      LAYER M5 ;
        RECT  84.24 75.916 84.264 76 ;
    END
  END dout[377]
  PIN dout[378]
    DIRECTION OUTPUT ;
    USE SIGNAL ;
    PORT
      LAYER M5 ;
        RECT  75.168 75.916 75.192 76 ;
    END
  END dout[378]
  PIN dout[379]
    DIRECTION OUTPUT ;
    USE SIGNAL ;
    PORT
      LAYER M7 ;
        RECT  77.312 75.931 77.344 76 ;
    END
  END dout[379]
  PIN dout[37]
    DIRECTION OUTPUT ;
    USE SIGNAL ;
    PORT
      LAYER M5 ;
        RECT  19.152 75.916 19.176 76 ;
    END
  END dout[37]
  PIN dout[380]
    DIRECTION OUTPUT ;
    USE SIGNAL ;
    PORT
      LAYER M5 ;
        RECT  103.344 75.916 103.368 76 ;
    END
  END dout[380]
  PIN dout[381]
    DIRECTION OUTPUT ;
    USE SIGNAL ;
    PORT
      LAYER M5 ;
        RECT  75.36 75.916 75.384 76 ;
    END
  END dout[381]
  PIN dout[382]
    DIRECTION OUTPUT ;
    USE SIGNAL ;
    PORT
      LAYER M7 ;
        RECT  81.024 75.931 81.056 76 ;
    END
  END dout[382]
  PIN dout[383]
    DIRECTION OUTPUT ;
    USE SIGNAL ;
    PORT
      LAYER M7 ;
        RECT  76.672 75.931 76.704 76 ;
    END
  END dout[383]
  PIN dout[384]
    DIRECTION OUTPUT ;
    USE SIGNAL ;
    PORT
      LAYER M7 ;
        RECT  91.52 75.931 91.552 76 ;
    END
  END dout[384]
  PIN dout[385]
    DIRECTION OUTPUT ;
    USE SIGNAL ;
    PORT
      LAYER M5 ;
        RECT  106.704 75.916 106.728 76 ;
    END
  END dout[385]
  PIN dout[386]
    DIRECTION OUTPUT ;
    USE SIGNAL ;
    PORT
      LAYER M5 ;
        RECT  103.968 75.916 103.992 76 ;
    END
  END dout[386]
  PIN dout[387]
    DIRECTION OUTPUT ;
    USE SIGNAL ;
    PORT
      LAYER M5 ;
        RECT  106.032 75.916 106.056 76 ;
    END
  END dout[387]
  PIN dout[388]
    DIRECTION OUTPUT ;
    USE SIGNAL ;
    PORT
      LAYER M5 ;
        RECT  93.024 75.916 93.048 76 ;
    END
  END dout[388]
  PIN dout[389]
    DIRECTION OUTPUT ;
    USE SIGNAL ;
    PORT
      LAYER M7 ;
        RECT  88.768 75.931 88.8 76 ;
    END
  END dout[389]
  PIN dout[38]
    DIRECTION OUTPUT ;
    USE SIGNAL ;
    PORT
      LAYER M5 ;
        RECT  20.928 75.916 20.952 76 ;
    END
  END dout[38]
  PIN dout[390]
    DIRECTION OUTPUT ;
    USE SIGNAL ;
    PORT
      LAYER M5 ;
        RECT  101.328 75.916 101.352 76 ;
    END
  END dout[390]
  PIN dout[391]
    DIRECTION OUTPUT ;
    USE SIGNAL ;
    PORT
      LAYER M7 ;
        RECT  102.272 75.931 102.304 76 ;
    END
  END dout[391]
  PIN dout[392]
    DIRECTION OUTPUT ;
    USE SIGNAL ;
    PORT
      LAYER M5 ;
        RECT  96.096 75.916 96.12 76 ;
    END
  END dout[392]
  PIN dout[393]
    DIRECTION OUTPUT ;
    USE SIGNAL ;
    PORT
      LAYER M7 ;
        RECT  101.44 75.931 101.472 76 ;
    END
  END dout[393]
  PIN dout[394]
    DIRECTION OUTPUT ;
    USE SIGNAL ;
    PORT
      LAYER M5 ;
        RECT  100.512 75.916 100.536 76 ;
    END
  END dout[394]
  PIN dout[395]
    DIRECTION OUTPUT ;
    USE SIGNAL ;
    PORT
      LAYER M5 ;
        RECT  97.248 75.916 97.272 76 ;
    END
  END dout[395]
  PIN dout[396]
    DIRECTION OUTPUT ;
    USE SIGNAL ;
    PORT
      LAYER M5 ;
        RECT  109.056 75.916 109.08 76 ;
    END
  END dout[396]
  PIN dout[397]
    DIRECTION OUTPUT ;
    USE SIGNAL ;
    PORT
      LAYER M5 ;
        RECT  105.264 75.916 105.288 76 ;
    END
  END dout[397]
  PIN dout[398]
    DIRECTION OUTPUT ;
    USE SIGNAL ;
    PORT
      LAYER M5 ;
        RECT  109.104 75.916 109.128 76 ;
    END
  END dout[398]
  PIN dout[399]
    DIRECTION OUTPUT ;
    USE SIGNAL ;
    PORT
      LAYER M5 ;
        RECT  98.496 75.916 98.52 76 ;
    END
  END dout[399]
  PIN dout[39]
    DIRECTION OUTPUT ;
    USE SIGNAL ;
    PORT
      LAYER M5 ;
        RECT  36 75.916 36.024 76 ;
    END
  END dout[39]
  PIN dout[3]
    DIRECTION OUTPUT ;
    USE SIGNAL ;
    PORT
      LAYER M5 ;
        RECT  19.968 75.916 19.992 76 ;
    END
  END dout[3]
  PIN dout[400]
    DIRECTION OUTPUT ;
    USE SIGNAL ;
    PORT
      LAYER M5 ;
        RECT  105.6 75.916 105.624 76 ;
    END
  END dout[400]
  PIN dout[401]
    DIRECTION OUTPUT ;
    USE SIGNAL ;
    PORT
      LAYER M7 ;
        RECT  101.184 75.931 101.216 76 ;
    END
  END dout[401]
  PIN dout[402]
    DIRECTION OUTPUT ;
    USE SIGNAL ;
    PORT
      LAYER M5 ;
        RECT  100.8 75.916 100.824 76 ;
    END
  END dout[402]
  PIN dout[403]
    DIRECTION OUTPUT ;
    USE SIGNAL ;
    PORT
      LAYER M7 ;
        RECT  102.656 75.931 102.688 76 ;
    END
  END dout[403]
  PIN dout[404]
    DIRECTION OUTPUT ;
    USE SIGNAL ;
    PORT
      LAYER M7 ;
        RECT  100.672 75.931 100.704 76 ;
    END
  END dout[404]
  PIN dout[405]
    DIRECTION OUTPUT ;
    USE SIGNAL ;
    PORT
      LAYER M7 ;
        RECT  103.04 75.931 103.072 76 ;
    END
  END dout[405]
  PIN dout[406]
    DIRECTION OUTPUT ;
    USE SIGNAL ;
    PORT
      LAYER M5 ;
        RECT  99.888 75.916 99.912 76 ;
    END
  END dout[406]
  PIN dout[407]
    DIRECTION OUTPUT ;
    USE SIGNAL ;
    PORT
      LAYER M7 ;
        RECT  101.632 75.931 101.664 76 ;
    END
  END dout[407]
  PIN dout[408]
    DIRECTION OUTPUT ;
    USE SIGNAL ;
    PORT
      LAYER M5 ;
        RECT  100.272 75.916 100.296 76 ;
    END
  END dout[408]
  PIN dout[409]
    DIRECTION OUTPUT ;
    USE SIGNAL ;
    PORT
      LAYER M5 ;
        RECT  101.568 75.916 101.592 76 ;
    END
  END dout[409]
  PIN dout[40]
    DIRECTION OUTPUT ;
    USE SIGNAL ;
    PORT
      LAYER M5 ;
        RECT  35.616 75.916 35.64 76 ;
    END
  END dout[40]
  PIN dout[410]
    DIRECTION OUTPUT ;
    USE SIGNAL ;
    PORT
      LAYER M5 ;
        RECT  107.616 75.916 107.64 76 ;
    END
  END dout[410]
  PIN dout[411]
    DIRECTION OUTPUT ;
    USE SIGNAL ;
    PORT
      LAYER M5 ;
        RECT  106.08 75.916 106.104 76 ;
    END
  END dout[411]
  PIN dout[412]
    DIRECTION OUTPUT ;
    USE SIGNAL ;
    PORT
      LAYER M5 ;
        RECT  104.4 75.916 104.424 76 ;
    END
  END dout[412]
  PIN dout[413]
    DIRECTION OUTPUT ;
    USE SIGNAL ;
    PORT
      LAYER M5 ;
        RECT  104.448 75.916 104.472 76 ;
    END
  END dout[413]
  PIN dout[414]
    DIRECTION OUTPUT ;
    USE SIGNAL ;
    PORT
      LAYER M5 ;
        RECT  101.472 75.916 101.496 76 ;
    END
  END dout[414]
  PIN dout[415]
    DIRECTION OUTPUT ;
    USE SIGNAL ;
    PORT
      LAYER M5 ;
        RECT  102.96 75.916 102.984 76 ;
    END
  END dout[415]
  PIN dout[416]
    DIRECTION OUTPUT ;
    USE SIGNAL ;
    PORT
      LAYER M5 ;
        RECT  105.744 75.916 105.768 76 ;
    END
  END dout[416]
  PIN dout[417]
    DIRECTION OUTPUT ;
    USE SIGNAL ;
    PORT
      LAYER M5 ;
        RECT  104.112 75.916 104.136 76 ;
    END
  END dout[417]
  PIN dout[418]
    DIRECTION OUTPUT ;
    USE SIGNAL ;
    PORT
      LAYER M5 ;
        RECT  108.384 75.916 108.408 76 ;
    END
  END dout[418]
  PIN dout[419]
    DIRECTION OUTPUT ;
    USE SIGNAL ;
    PORT
      LAYER M5 ;
        RECT  102.576 75.916 102.6 76 ;
    END
  END dout[419]
  PIN dout[41]
    DIRECTION OUTPUT ;
    USE SIGNAL ;
    PORT
      LAYER M5 ;
        RECT  18.288 75.916 18.312 76 ;
    END
  END dout[41]
  PIN dout[420]
    DIRECTION OUTPUT ;
    USE SIGNAL ;
    PORT
      LAYER M5 ;
        RECT  101.376 75.916 101.4 76 ;
    END
  END dout[420]
  PIN dout[421]
    DIRECTION OUTPUT ;
    USE SIGNAL ;
    PORT
      LAYER M5 ;
        RECT  104.208 75.916 104.232 76 ;
    END
  END dout[421]
  PIN dout[422]
    DIRECTION OUTPUT ;
    USE SIGNAL ;
    PORT
      LAYER M5 ;
        RECT  105.36 75.916 105.384 76 ;
    END
  END dout[422]
  PIN dout[423]
    DIRECTION OUTPUT ;
    USE SIGNAL ;
    PORT
      LAYER M5 ;
        RECT  104.16 75.916 104.184 76 ;
    END
  END dout[423]
  PIN dout[424]
    DIRECTION OUTPUT ;
    USE SIGNAL ;
    PORT
      LAYER M5 ;
        RECT  105.504 75.916 105.528 76 ;
    END
  END dout[424]
  PIN dout[425]
    DIRECTION OUTPUT ;
    USE SIGNAL ;
    PORT
      LAYER M5 ;
        RECT  101.664 75.916 101.688 76 ;
    END
  END dout[425]
  PIN dout[426]
    DIRECTION OUTPUT ;
    USE SIGNAL ;
    PORT
      LAYER M5 ;
        RECT  102.768 75.916 102.792 76 ;
    END
  END dout[426]
  PIN dout[427]
    DIRECTION OUTPUT ;
    USE SIGNAL ;
    PORT
      LAYER M5 ;
        RECT  108.48 75.916 108.504 76 ;
    END
  END dout[427]
  PIN dout[428]
    DIRECTION OUTPUT ;
    USE SIGNAL ;
    PORT
      LAYER M5 ;
        RECT  101.04 75.916 101.064 76 ;
    END
  END dout[428]
  PIN dout[429]
    DIRECTION OUTPUT ;
    USE SIGNAL ;
    PORT
      LAYER M5 ;
        RECT  100.032 75.916 100.056 76 ;
    END
  END dout[429]
  PIN dout[42]
    DIRECTION OUTPUT ;
    USE SIGNAL ;
    PORT
      LAYER M5 ;
        RECT  20.208 75.916 20.232 76 ;
    END
  END dout[42]
  PIN dout[430]
    DIRECTION OUTPUT ;
    USE SIGNAL ;
    PORT
      LAYER M5 ;
        RECT  107.952 75.916 107.976 76 ;
    END
  END dout[430]
  PIN dout[431]
    DIRECTION OUTPUT ;
    USE SIGNAL ;
    PORT
      LAYER M5 ;
        RECT  101.28 75.916 101.304 76 ;
    END
  END dout[431]
  PIN dout[432]
    DIRECTION OUTPUT ;
    USE SIGNAL ;
    PORT
      LAYER M5 ;
        RECT  102.528 75.916 102.552 76 ;
    END
  END dout[432]
  PIN dout[433]
    DIRECTION OUTPUT ;
    USE SIGNAL ;
    PORT
      LAYER M7 ;
        RECT  103.232 75.931 103.264 76 ;
    END
  END dout[433]
  PIN dout[434]
    DIRECTION OUTPUT ;
    USE SIGNAL ;
    PORT
      LAYER M5 ;
        RECT  100.128 75.916 100.152 76 ;
    END
  END dout[434]
  PIN dout[435]
    DIRECTION OUTPUT ;
    USE SIGNAL ;
    PORT
      LAYER M5 ;
        RECT  109.008 75.916 109.032 76 ;
    END
  END dout[435]
  PIN dout[436]
    DIRECTION OUTPUT ;
    USE SIGNAL ;
    PORT
      LAYER M5 ;
        RECT  103.152 75.916 103.176 76 ;
    END
  END dout[436]
  PIN dout[437]
    DIRECTION OUTPUT ;
    USE SIGNAL ;
    PORT
      LAYER M5 ;
        RECT  102 75.916 102.024 76 ;
    END
  END dout[437]
  PIN dout[438]
    DIRECTION OUTPUT ;
    USE SIGNAL ;
    PORT
      LAYER M5 ;
        RECT  108.624 75.916 108.648 76 ;
    END
  END dout[438]
  PIN dout[439]
    DIRECTION OUTPUT ;
    USE SIGNAL ;
    PORT
      LAYER M5 ;
        RECT  108.912 75.916 108.936 76 ;
    END
  END dout[439]
  PIN dout[43]
    DIRECTION OUTPUT ;
    USE SIGNAL ;
    PORT
      LAYER M7 ;
        RECT  11.84 75.931 11.872 76 ;
    END
  END dout[43]
  PIN dout[440]
    DIRECTION OUTPUT ;
    USE SIGNAL ;
    PORT
      LAYER M5 ;
        RECT  105.936 75.916 105.96 76 ;
    END
  END dout[440]
  PIN dout[441]
    DIRECTION OUTPUT ;
    USE SIGNAL ;
    PORT
      LAYER M7 ;
        RECT  64.768 75.931 64.8 76 ;
    END
  END dout[441]
  PIN dout[442]
    DIRECTION OUTPUT ;
    USE SIGNAL ;
    PORT
      LAYER M7 ;
        RECT  62.848 75.931 62.88 76 ;
    END
  END dout[442]
  PIN dout[443]
    DIRECTION OUTPUT ;
    USE SIGNAL ;
    PORT
      LAYER M5 ;
        RECT  71.568 75.916 71.592 76 ;
    END
  END dout[443]
  PIN dout[444]
    DIRECTION OUTPUT ;
    USE SIGNAL ;
    PORT
      LAYER M5 ;
        RECT  108.24 75.916 108.264 76 ;
    END
  END dout[444]
  PIN dout[445]
    DIRECTION OUTPUT ;
    USE SIGNAL ;
    PORT
      LAYER M5 ;
        RECT  67.344 75.916 67.368 76 ;
    END
  END dout[445]
  PIN dout[446]
    DIRECTION OUTPUT ;
    USE SIGNAL ;
    PORT
      LAYER M5 ;
        RECT  66.912 75.916 66.936 76 ;
    END
  END dout[446]
  PIN dout[447]
    DIRECTION OUTPUT ;
    USE SIGNAL ;
    PORT
      LAYER M5 ;
        RECT  67.248 75.916 67.272 76 ;
    END
  END dout[447]
  PIN dout[448]
    DIRECTION OUTPUT ;
    USE SIGNAL ;
    PORT
      LAYER M7 ;
        RECT  91.072 75.931 91.104 76 ;
    END
  END dout[448]
  PIN dout[449]
    DIRECTION OUTPUT ;
    USE SIGNAL ;
    PORT
      LAYER M5 ;
        RECT  94.176 75.916 94.2 76 ;
    END
  END dout[449]
  PIN dout[44]
    DIRECTION OUTPUT ;
    USE SIGNAL ;
    PORT
      LAYER M5 ;
        RECT  7.68 75.916 7.704 76 ;
    END
  END dout[44]
  PIN dout[450]
    DIRECTION OUTPUT ;
    USE SIGNAL ;
    PORT
      LAYER M5 ;
        RECT  105.12 75.916 105.144 76 ;
    END
  END dout[450]
  PIN dout[451]
    DIRECTION OUTPUT ;
    USE SIGNAL ;
    PORT
      LAYER M5 ;
        RECT  95.136 75.916 95.16 76 ;
    END
  END dout[451]
  PIN dout[452]
    DIRECTION OUTPUT ;
    USE SIGNAL ;
    PORT
      LAYER M5 ;
        RECT  108.144 75.916 108.168 76 ;
    END
  END dout[452]
  PIN dout[453]
    DIRECTION OUTPUT ;
    USE SIGNAL ;
    PORT
      LAYER M5 ;
        RECT  105.408 75.916 105.432 76 ;
    END
  END dout[453]
  PIN dout[454]
    DIRECTION OUTPUT ;
    USE SIGNAL ;
    PORT
      LAYER M5 ;
        RECT  94.272 75.916 94.296 76 ;
    END
  END dout[454]
  PIN dout[455]
    DIRECTION OUTPUT ;
    USE SIGNAL ;
    PORT
      LAYER M5 ;
        RECT  106.464 75.916 106.488 76 ;
    END
  END dout[455]
  PIN dout[456]
    DIRECTION OUTPUT ;
    USE SIGNAL ;
    PORT
      LAYER M5 ;
        RECT  99.936 75.916 99.96 76 ;
    END
  END dout[456]
  PIN dout[457]
    DIRECTION OUTPUT ;
    USE SIGNAL ;
    PORT
      LAYER M7 ;
        RECT  100.544 75.931 100.576 76 ;
    END
  END dout[457]
  PIN dout[458]
    DIRECTION OUTPUT ;
    USE SIGNAL ;
    PORT
      LAYER M5 ;
        RECT  108.048 75.916 108.072 76 ;
    END
  END dout[458]
  PIN dout[459]
    DIRECTION OUTPUT ;
    USE SIGNAL ;
    PORT
      LAYER M5 ;
        RECT  104.736 75.916 104.76 76 ;
    END
  END dout[459]
  PIN dout[45]
    DIRECTION OUTPUT ;
    USE SIGNAL ;
    PORT
      LAYER M5 ;
        RECT  16.368 75.916 16.392 76 ;
    END
  END dout[45]
  PIN dout[460]
    DIRECTION OUTPUT ;
    USE SIGNAL ;
    PORT
      LAYER M5 ;
        RECT  103.392 75.916 103.416 76 ;
    END
  END dout[460]
  PIN dout[461]
    DIRECTION OUTPUT ;
    USE SIGNAL ;
    PORT
      LAYER M5 ;
        RECT  106.752 75.916 106.776 76 ;
    END
  END dout[461]
  PIN dout[462]
    DIRECTION OUTPUT ;
    USE SIGNAL ;
    PORT
      LAYER M5 ;
        RECT  106.848 75.916 106.872 76 ;
    END
  END dout[462]
  PIN dout[463]
    DIRECTION OUTPUT ;
    USE SIGNAL ;
    PORT
      LAYER M5 ;
        RECT  108.864 75.916 108.888 76 ;
    END
  END dout[463]
  PIN dout[464]
    DIRECTION OUTPUT ;
    USE SIGNAL ;
    PORT
      LAYER M5 ;
        RECT  105.552 75.916 105.576 76 ;
    END
  END dout[464]
  PIN dout[465]
    DIRECTION OUTPUT ;
    USE SIGNAL ;
    PORT
      LAYER M5 ;
        RECT  106.8 75.916 106.824 76 ;
    END
  END dout[465]
  PIN dout[466]
    DIRECTION OUTPUT ;
    USE SIGNAL ;
    PORT
      LAYER M5 ;
        RECT  107.52 75.916 107.544 76 ;
    END
  END dout[466]
  PIN dout[467]
    DIRECTION OUTPUT ;
    USE SIGNAL ;
    PORT
      LAYER M5 ;
        RECT  105.984 75.916 106.008 76 ;
    END
  END dout[467]
  PIN dout[468]
    DIRECTION OUTPUT ;
    USE SIGNAL ;
    PORT
      LAYER M7 ;
        RECT  91.776 75.931 91.808 76 ;
    END
  END dout[468]
  PIN dout[469]
    DIRECTION OUTPUT ;
    USE SIGNAL ;
    PORT
      LAYER M5 ;
        RECT  87.312 75.916 87.336 76 ;
    END
  END dout[469]
  PIN dout[46]
    DIRECTION OUTPUT ;
    USE SIGNAL ;
    PORT
      LAYER M7 ;
        RECT  4.48 75.931 4.512 76 ;
    END
  END dout[46]
  PIN dout[470]
    DIRECTION OUTPUT ;
    USE SIGNAL ;
    PORT
      LAYER M7 ;
        RECT  103.296 75.931 103.328 76 ;
    END
  END dout[470]
  PIN dout[471]
    DIRECTION OUTPUT ;
    USE SIGNAL ;
    PORT
      LAYER M5 ;
        RECT  105.888 75.916 105.912 76 ;
    END
  END dout[471]
  PIN dout[472]
    DIRECTION OUTPUT ;
    USE SIGNAL ;
    PORT
      LAYER M5 ;
        RECT  105.024 75.916 105.048 76 ;
    END
  END dout[472]
  PIN dout[473]
    DIRECTION OUTPUT ;
    USE SIGNAL ;
    PORT
      LAYER M7 ;
        RECT  102.848 75.931 102.88 76 ;
    END
  END dout[473]
  PIN dout[474]
    DIRECTION OUTPUT ;
    USE SIGNAL ;
    PORT
      LAYER M5 ;
        RECT  85.344 75.916 85.368 76 ;
    END
  END dout[474]
  PIN dout[475]
    DIRECTION OUTPUT ;
    USE SIGNAL ;
    PORT
      LAYER M5 ;
        RECT  104.784 75.916 104.808 76 ;
    END
  END dout[475]
  PIN dout[476]
    DIRECTION OUTPUT ;
    USE SIGNAL ;
    PORT
      LAYER M5 ;
        RECT  103.584 75.916 103.608 76 ;
    END
  END dout[476]
  PIN dout[477]
    DIRECTION OUTPUT ;
    USE SIGNAL ;
    PORT
      LAYER M5 ;
        RECT  97.872 75.916 97.896 76 ;
    END
  END dout[477]
  PIN dout[478]
    DIRECTION OUTPUT ;
    USE SIGNAL ;
    PORT
      LAYER M5 ;
        RECT  86.4 75.916 86.424 76 ;
    END
  END dout[478]
  PIN dout[479]
    DIRECTION OUTPUT ;
    USE SIGNAL ;
    PORT
      LAYER M7 ;
        RECT  100.224 75.931 100.256 76 ;
    END
  END dout[479]
  PIN dout[47]
    DIRECTION OUTPUT ;
    USE SIGNAL ;
    PORT
      LAYER M7 ;
        RECT  4.16 75.931 4.192 76 ;
    END
  END dout[47]
  PIN dout[480]
    DIRECTION OUTPUT ;
    USE SIGNAL ;
    PORT
      LAYER M5 ;
        RECT  92.4 75.916 92.424 76 ;
    END
  END dout[480]
  PIN dout[481]
    DIRECTION OUTPUT ;
    USE SIGNAL ;
    PORT
      LAYER M7 ;
        RECT  89.088 75.931 89.12 76 ;
    END
  END dout[481]
  PIN dout[482]
    DIRECTION OUTPUT ;
    USE SIGNAL ;
    PORT
      LAYER M7 ;
        RECT  89.472 75.931 89.504 76 ;
    END
  END dout[482]
  PIN dout[483]
    DIRECTION OUTPUT ;
    USE SIGNAL ;
    PORT
      LAYER M5 ;
        RECT  99.696 75.916 99.72 76 ;
    END
  END dout[483]
  PIN dout[484]
    DIRECTION OUTPUT ;
    USE SIGNAL ;
    PORT
      LAYER M7 ;
        RECT  101.76 75.931 101.792 76 ;
    END
  END dout[484]
  PIN dout[485]
    DIRECTION OUTPUT ;
    USE SIGNAL ;
    PORT
      LAYER M5 ;
        RECT  92.736 75.916 92.76 76 ;
    END
  END dout[485]
  PIN dout[486]
    DIRECTION OUTPUT ;
    USE SIGNAL ;
    PORT
      LAYER M5 ;
        RECT  74.448 75.916 74.472 76 ;
    END
  END dout[486]
  PIN dout[487]
    DIRECTION OUTPUT ;
    USE SIGNAL ;
    PORT
      LAYER M7 ;
        RECT  102.144 75.931 102.176 76 ;
    END
  END dout[487]
  PIN dout[488]
    DIRECTION OUTPUT ;
    USE SIGNAL ;
    PORT
      LAYER M5 ;
        RECT  98.4 75.916 98.424 76 ;
    END
  END dout[488]
  PIN dout[489]
    DIRECTION OUTPUT ;
    USE SIGNAL ;
    PORT
      LAYER M5 ;
        RECT  97.44 75.916 97.464 76 ;
    END
  END dout[489]
  PIN dout[48]
    DIRECTION OUTPUT ;
    USE SIGNAL ;
    PORT
      LAYER M7 ;
        RECT  3.584 75.931 3.616 76 ;
    END
  END dout[48]
  PIN dout[490]
    DIRECTION OUTPUT ;
    USE SIGNAL ;
    PORT
      LAYER M5 ;
        RECT  96.528 75.916 96.552 76 ;
    END
  END dout[490]
  PIN dout[491]
    DIRECTION OUTPUT ;
    USE SIGNAL ;
    PORT
      LAYER M5 ;
        RECT  104.256 75.916 104.28 76 ;
    END
  END dout[491]
  PIN dout[492]
    DIRECTION OUTPUT ;
    USE SIGNAL ;
    PORT
      LAYER M5 ;
        RECT  87.216 75.916 87.24 76 ;
    END
  END dout[492]
  PIN dout[493]
    DIRECTION OUTPUT ;
    USE SIGNAL ;
    PORT
      LAYER M7 ;
        RECT  99.648 75.931 99.68 76 ;
    END
  END dout[493]
  PIN dout[494]
    DIRECTION OUTPUT ;
    USE SIGNAL ;
    PORT
      LAYER M7 ;
        RECT  90.176 75.931 90.208 76 ;
    END
  END dout[494]
  PIN dout[495]
    DIRECTION OUTPUT ;
    USE SIGNAL ;
    PORT
      LAYER M5 ;
        RECT  105.312 75.916 105.336 76 ;
    END
  END dout[495]
  PIN dout[496]
    DIRECTION OUTPUT ;
    USE SIGNAL ;
    PORT
      LAYER M5 ;
        RECT  108.72 75.916 108.744 76 ;
    END
  END dout[496]
  PIN dout[497]
    DIRECTION OUTPUT ;
    USE SIGNAL ;
    PORT
      LAYER M5 ;
        RECT  93.216 75.916 93.24 76 ;
    END
  END dout[497]
  PIN dout[498]
    DIRECTION OUTPUT ;
    USE SIGNAL ;
    PORT
      LAYER M7 ;
        RECT  80.192 75.931 80.224 76 ;
    END
  END dout[498]
  PIN dout[499]
    DIRECTION OUTPUT ;
    USE SIGNAL ;
    PORT
      LAYER M5 ;
        RECT  92.592 75.916 92.616 76 ;
    END
  END dout[499]
  PIN dout[49]
    DIRECTION OUTPUT ;
    USE SIGNAL ;
    PORT
      LAYER M7 ;
        RECT  4.096 75.931 4.128 76 ;
    END
  END dout[49]
  PIN dout[4]
    DIRECTION OUTPUT ;
    USE SIGNAL ;
    PORT
      LAYER M7 ;
        RECT  38.912 75.931 38.944 76 ;
    END
  END dout[4]
  PIN dout[500]
    DIRECTION OUTPUT ;
    USE SIGNAL ;
    PORT
      LAYER M5 ;
        RECT  104.064 75.916 104.088 76 ;
    END
  END dout[500]
  PIN dout[501]
    DIRECTION OUTPUT ;
    USE SIGNAL ;
    PORT
      LAYER M7 ;
        RECT  103.552 75.931 103.584 76 ;
    END
  END dout[501]
  PIN dout[502]
    DIRECTION OUTPUT ;
    USE SIGNAL ;
    PORT
      LAYER M5 ;
        RECT  107.28 75.916 107.304 76 ;
    END
  END dout[502]
  PIN dout[503]
    DIRECTION OUTPUT ;
    USE SIGNAL ;
    PORT
      LAYER M7 ;
        RECT  102.464 75.931 102.496 76 ;
    END
  END dout[503]
  PIN dout[504]
    DIRECTION OUTPUT ;
    USE SIGNAL ;
    PORT
      LAYER M5 ;
        RECT  65.952 75.916 65.976 76 ;
    END
  END dout[504]
  PIN dout[505]
    DIRECTION OUTPUT ;
    USE SIGNAL ;
    PORT
      LAYER M5 ;
        RECT  95.616 75.916 95.64 76 ;
    END
  END dout[505]
  PIN dout[506]
    DIRECTION OUTPUT ;
    USE SIGNAL ;
    PORT
      LAYER M5 ;
        RECT  81.6 75.916 81.624 76 ;
    END
  END dout[506]
  PIN dout[507]
    DIRECTION OUTPUT ;
    USE SIGNAL ;
    PORT
      LAYER M5 ;
        RECT  97.968 75.916 97.992 76 ;
    END
  END dout[507]
  PIN dout[508]
    DIRECTION OUTPUT ;
    USE SIGNAL ;
    PORT
      LAYER M5 ;
        RECT  93.984 75.916 94.008 76 ;
    END
  END dout[508]
  PIN dout[509]
    DIRECTION OUTPUT ;
    USE SIGNAL ;
    PORT
      LAYER M7 ;
        RECT  61.76 75.931 61.792 76 ;
    END
  END dout[509]
  PIN dout[50]
    DIRECTION OUTPUT ;
    USE SIGNAL ;
    PORT
      LAYER M7 ;
        RECT  3.264 75.931 3.296 76 ;
    END
  END dout[50]
  PIN dout[510]
    DIRECTION OUTPUT ;
    USE SIGNAL ;
    PORT
      LAYER M7 ;
        RECT  78.592 75.931 78.624 76 ;
    END
  END dout[510]
  PIN dout[511]
    DIRECTION OUTPUT ;
    USE SIGNAL ;
    PORT
      LAYER M7 ;
        RECT  64.192 75.931 64.224 76 ;
    END
  END dout[511]
  PIN dout[512]
    DIRECTION OUTPUT ;
    USE SIGNAL ;
    PORT
      LAYER M7 ;
        RECT  14.592 75.931 14.624 76 ;
    END
  END dout[512]
  PIN dout[513]
    DIRECTION OUTPUT ;
    USE SIGNAL ;
    PORT
      LAYER M5 ;
        RECT  28.032 75.916 28.056 76 ;
    END
  END dout[513]
  PIN dout[514]
    DIRECTION OUTPUT ;
    USE SIGNAL ;
    PORT
      LAYER M7 ;
        RECT  15.04 75.931 15.072 76 ;
    END
  END dout[514]
  PIN dout[515]
    DIRECTION OUTPUT ;
    USE SIGNAL ;
    PORT
      LAYER M5 ;
        RECT  20.016 75.916 20.04 76 ;
    END
  END dout[515]
  PIN dout[516]
    DIRECTION OUTPUT ;
    USE SIGNAL ;
    PORT
      LAYER M7 ;
        RECT  38.848 75.931 38.88 76 ;
    END
  END dout[516]
  PIN dout[517]
    DIRECTION OUTPUT ;
    USE SIGNAL ;
    PORT
      LAYER M5 ;
        RECT  36.144 75.916 36.168 76 ;
    END
  END dout[517]
  PIN dout[518]
    DIRECTION OUTPUT ;
    USE SIGNAL ;
    PORT
      LAYER M7 ;
        RECT  39.168 75.931 39.2 76 ;
    END
  END dout[518]
  PIN dout[519]
    DIRECTION OUTPUT ;
    USE SIGNAL ;
    PORT
      LAYER M5 ;
        RECT  33.408 75.916 33.432 76 ;
    END
  END dout[519]
  PIN dout[51]
    DIRECTION OUTPUT ;
    USE SIGNAL ;
    PORT
      LAYER M5 ;
        RECT  2.304 75.916 2.328 76 ;
    END
  END dout[51]
  PIN dout[520]
    DIRECTION OUTPUT ;
    USE SIGNAL ;
    PORT
      LAYER M7 ;
        RECT  22.912 75.931 22.944 76 ;
    END
  END dout[520]
  PIN dout[521]
    DIRECTION OUTPUT ;
    USE SIGNAL ;
    PORT
      LAYER M5 ;
        RECT  20.256 75.916 20.28 76 ;
    END
  END dout[521]
  PIN dout[522]
    DIRECTION OUTPUT ;
    USE SIGNAL ;
    PORT
      LAYER M5 ;
        RECT  34.944 75.916 34.968 76 ;
    END
  END dout[522]
  PIN dout[523]
    DIRECTION OUTPUT ;
    USE SIGNAL ;
    PORT
      LAYER M5 ;
        RECT  36.624 75.916 36.648 76 ;
    END
  END dout[523]
  PIN dout[524]
    DIRECTION OUTPUT ;
    USE SIGNAL ;
    PORT
      LAYER M5 ;
        RECT  36.816 75.916 36.84 76 ;
    END
  END dout[524]
  PIN dout[525]
    DIRECTION OUTPUT ;
    USE SIGNAL ;
    PORT
      LAYER M7 ;
        RECT  40.832 75.931 40.864 76 ;
    END
  END dout[525]
  PIN dout[526]
    DIRECTION OUTPUT ;
    USE SIGNAL ;
    PORT
      LAYER M5 ;
        RECT  34.032 75.916 34.056 76 ;
    END
  END dout[526]
  PIN dout[527]
    DIRECTION OUTPUT ;
    USE SIGNAL ;
    PORT
      LAYER M5 ;
        RECT  37.296 75.916 37.32 76 ;
    END
  END dout[527]
  PIN dout[528]
    DIRECTION OUTPUT ;
    USE SIGNAL ;
    PORT
      LAYER M7 ;
        RECT  40 75.931 40.032 76 ;
    END
  END dout[528]
  PIN dout[529]
    DIRECTION OUTPUT ;
    USE SIGNAL ;
    PORT
      LAYER M7 ;
        RECT  38.784 75.931 38.816 76 ;
    END
  END dout[529]
  PIN dout[52]
    DIRECTION OUTPUT ;
    USE SIGNAL ;
    PORT
      LAYER M7 ;
        RECT  4.416 75.931 4.448 76 ;
    END
  END dout[52]
  PIN dout[530]
    DIRECTION OUTPUT ;
    USE SIGNAL ;
    PORT
      LAYER M5 ;
        RECT  35.472 75.916 35.496 76 ;
    END
  END dout[530]
  PIN dout[531]
    DIRECTION OUTPUT ;
    USE SIGNAL ;
    PORT
      LAYER M7 ;
        RECT  39.424 75.931 39.456 76 ;
    END
  END dout[531]
  PIN dout[532]
    DIRECTION OUTPUT ;
    USE SIGNAL ;
    PORT
      LAYER M5 ;
        RECT  37.776 75.916 37.8 76 ;
    END
  END dout[532]
  PIN dout[533]
    DIRECTION OUTPUT ;
    USE SIGNAL ;
    PORT
      LAYER M7 ;
        RECT  38.464 75.931 38.496 76 ;
    END
  END dout[533]
  PIN dout[534]
    DIRECTION OUTPUT ;
    USE SIGNAL ;
    PORT
      LAYER M5 ;
        RECT  37.008 75.916 37.032 76 ;
    END
  END dout[534]
  PIN dout[535]
    DIRECTION OUTPUT ;
    USE SIGNAL ;
    PORT
      LAYER M5 ;
        RECT  35.184 75.916 35.208 76 ;
    END
  END dout[535]
  PIN dout[536]
    DIRECTION OUTPUT ;
    USE SIGNAL ;
    PORT
      LAYER M5 ;
        RECT  32.88 75.916 32.904 76 ;
    END
  END dout[536]
  PIN dout[537]
    DIRECTION OUTPUT ;
    USE SIGNAL ;
    PORT
      LAYER M7 ;
        RECT  38.656 75.931 38.688 76 ;
    END
  END dout[537]
  PIN dout[538]
    DIRECTION OUTPUT ;
    USE SIGNAL ;
    PORT
      LAYER M5 ;
        RECT  30.768 75.916 30.792 76 ;
    END
  END dout[538]
  PIN dout[539]
    DIRECTION OUTPUT ;
    USE SIGNAL ;
    PORT
      LAYER M5 ;
        RECT  34.704 75.916 34.728 76 ;
    END
  END dout[539]
  PIN dout[53]
    DIRECTION OUTPUT ;
    USE SIGNAL ;
    PORT
      LAYER M7 ;
        RECT  3.904 75.931 3.936 76 ;
    END
  END dout[53]
  PIN dout[540]
    DIRECTION OUTPUT ;
    USE SIGNAL ;
    PORT
      LAYER M5 ;
        RECT  29.28 75.916 29.304 76 ;
    END
  END dout[540]
  PIN dout[541]
    DIRECTION OUTPUT ;
    USE SIGNAL ;
    PORT
      LAYER M5 ;
        RECT  27.168 75.916 27.192 76 ;
    END
  END dout[541]
  PIN dout[542]
    DIRECTION OUTPUT ;
    USE SIGNAL ;
    PORT
      LAYER M5 ;
        RECT  27.216 75.916 27.24 76 ;
    END
  END dout[542]
  PIN dout[543]
    DIRECTION OUTPUT ;
    USE SIGNAL ;
    PORT
      LAYER M7 ;
        RECT  23.552 75.931 23.584 76 ;
    END
  END dout[543]
  PIN dout[544]
    DIRECTION OUTPUT ;
    USE SIGNAL ;
    PORT
      LAYER M5 ;
        RECT  33.456 75.916 33.48 76 ;
    END
  END dout[544]
  PIN dout[545]
    DIRECTION OUTPUT ;
    USE SIGNAL ;
    PORT
      LAYER M5 ;
        RECT  2.928 75.916 2.952 76 ;
    END
  END dout[545]
  PIN dout[546]
    DIRECTION OUTPUT ;
    USE SIGNAL ;
    PORT
      LAYER M7 ;
        RECT  11.776 75.931 11.808 76 ;
    END
  END dout[546]
  PIN dout[547]
    DIRECTION OUTPUT ;
    USE SIGNAL ;
    PORT
      LAYER M7 ;
        RECT  24.256 75.931 24.288 76 ;
    END
  END dout[547]
  PIN dout[548]
    DIRECTION OUTPUT ;
    USE SIGNAL ;
    PORT
      LAYER M5 ;
        RECT  16.512 75.916 16.536 76 ;
    END
  END dout[548]
  PIN dout[549]
    DIRECTION OUTPUT ;
    USE SIGNAL ;
    PORT
      LAYER M5 ;
        RECT  19.2 75.916 19.224 76 ;
    END
  END dout[549]
  PIN dout[54]
    DIRECTION OUTPUT ;
    USE SIGNAL ;
    PORT
      LAYER M5 ;
        RECT  2.784 75.916 2.808 76 ;
    END
  END dout[54]
  PIN dout[550]
    DIRECTION OUTPUT ;
    USE SIGNAL ;
    PORT
      LAYER M5 ;
        RECT  20.976 75.916 21 76 ;
    END
  END dout[550]
  PIN dout[551]
    DIRECTION OUTPUT ;
    USE SIGNAL ;
    PORT
      LAYER M5 ;
        RECT  36.048 75.916 36.072 76 ;
    END
  END dout[551]
  PIN dout[552]
    DIRECTION OUTPUT ;
    USE SIGNAL ;
    PORT
      LAYER M5 ;
        RECT  35.664 75.916 35.688 76 ;
    END
  END dout[552]
  PIN dout[553]
    DIRECTION OUTPUT ;
    USE SIGNAL ;
    PORT
      LAYER M5 ;
        RECT  18.336 75.916 18.36 76 ;
    END
  END dout[553]
  PIN dout[554]
    DIRECTION OUTPUT ;
    USE SIGNAL ;
    PORT
      LAYER M5 ;
        RECT  20.16 75.916 20.184 76 ;
    END
  END dout[554]
  PIN dout[555]
    DIRECTION OUTPUT ;
    USE SIGNAL ;
    PORT
      LAYER M7 ;
        RECT  11.904 75.931 11.936 76 ;
    END
  END dout[555]
  PIN dout[556]
    DIRECTION OUTPUT ;
    USE SIGNAL ;
    PORT
      LAYER M5 ;
        RECT  7.632 75.916 7.656 76 ;
    END
  END dout[556]
  PIN dout[557]
    DIRECTION OUTPUT ;
    USE SIGNAL ;
    PORT
      LAYER M5 ;
        RECT  16.416 75.916 16.44 76 ;
    END
  END dout[557]
  PIN dout[558]
    DIRECTION OUTPUT ;
    USE SIGNAL ;
    PORT
      LAYER M7 ;
        RECT  4.544 75.931 4.576 76 ;
    END
  END dout[558]
  PIN dout[559]
    DIRECTION OUTPUT ;
    USE SIGNAL ;
    PORT
      LAYER M7 ;
        RECT  3.968 75.931 4 76 ;
    END
  END dout[559]
  PIN dout[55]
    DIRECTION OUTPUT ;
    USE SIGNAL ;
    PORT
      LAYER M7 ;
        RECT  5.696 75.931 5.728 76 ;
    END
  END dout[55]
  PIN dout[560]
    DIRECTION OUTPUT ;
    USE SIGNAL ;
    PORT
      LAYER M7 ;
        RECT  3.648 75.931 3.68 76 ;
    END
  END dout[560]
  PIN dout[561]
    DIRECTION OUTPUT ;
    USE SIGNAL ;
    PORT
      LAYER M7 ;
        RECT  4.032 75.931 4.064 76 ;
    END
  END dout[561]
  PIN dout[562]
    DIRECTION OUTPUT ;
    USE SIGNAL ;
    PORT
      LAYER M7 ;
        RECT  3.2 75.931 3.232 76 ;
    END
  END dout[562]
  PIN dout[563]
    DIRECTION OUTPUT ;
    USE SIGNAL ;
    PORT
      LAYER M5 ;
        RECT  2.352 75.916 2.376 76 ;
    END
  END dout[563]
  PIN dout[564]
    DIRECTION OUTPUT ;
    USE SIGNAL ;
    PORT
      LAYER M7 ;
        RECT  4.352 75.931 4.384 76 ;
    END
  END dout[564]
  PIN dout[565]
    DIRECTION OUTPUT ;
    USE SIGNAL ;
    PORT
      LAYER M7 ;
        RECT  3.84 75.931 3.872 76 ;
    END
  END dout[565]
  PIN dout[566]
    DIRECTION OUTPUT ;
    USE SIGNAL ;
    PORT
      LAYER M5 ;
        RECT  2.832 75.916 2.856 76 ;
    END
  END dout[566]
  PIN dout[567]
    DIRECTION OUTPUT ;
    USE SIGNAL ;
    PORT
      LAYER M7 ;
        RECT  5.76 75.931 5.792 76 ;
    END
  END dout[567]
  PIN dout[568]
    DIRECTION OUTPUT ;
    USE SIGNAL ;
    PORT
      LAYER M5 ;
        RECT  3.024 75.916 3.048 76 ;
    END
  END dout[568]
  PIN dout[569]
    DIRECTION OUTPUT ;
    USE SIGNAL ;
    PORT
      LAYER M5 ;
        RECT  27.024 75.916 27.048 76 ;
    END
  END dout[569]
  PIN dout[56]
    DIRECTION OUTPUT ;
    USE SIGNAL ;
    PORT
      LAYER M5 ;
        RECT  2.976 75.916 3 76 ;
    END
  END dout[56]
  PIN dout[570]
    DIRECTION OUTPUT ;
    USE SIGNAL ;
    PORT
      LAYER M5 ;
        RECT  6.384 75.916 6.408 76 ;
    END
  END dout[570]
  PIN dout[571]
    DIRECTION OUTPUT ;
    USE SIGNAL ;
    PORT
      LAYER M7 ;
        RECT  13.184 75.931 13.216 76 ;
    END
  END dout[571]
  PIN dout[572]
    DIRECTION OUTPUT ;
    USE SIGNAL ;
    PORT
      LAYER M5 ;
        RECT  8.928 75.916 8.952 76 ;
    END
  END dout[572]
  PIN dout[573]
    DIRECTION OUTPUT ;
    USE SIGNAL ;
    PORT
      LAYER M5 ;
        RECT  6.192 75.916 6.216 76 ;
    END
  END dout[573]
  PIN dout[574]
    DIRECTION OUTPUT ;
    USE SIGNAL ;
    PORT
      LAYER M7 ;
        RECT  4.288 75.931 4.32 76 ;
    END
  END dout[574]
  PIN dout[575]
    DIRECTION OUTPUT ;
    USE SIGNAL ;
    PORT
      LAYER M7 ;
        RECT  3.392 75.931 3.424 76 ;
    END
  END dout[575]
  PIN dout[576]
    DIRECTION OUTPUT ;
    USE SIGNAL ;
    PORT
      LAYER M5 ;
        RECT  70.992 75.916 71.016 76 ;
    END
  END dout[576]
  PIN dout[577]
    DIRECTION OUTPUT ;
    USE SIGNAL ;
    PORT
      LAYER M5 ;
        RECT  70.56 75.916 70.584 76 ;
    END
  END dout[577]
  PIN dout[578]
    DIRECTION OUTPUT ;
    USE SIGNAL ;
    PORT
      LAYER M5 ;
        RECT  71.856 75.916 71.88 76 ;
    END
  END dout[578]
  PIN dout[579]
    DIRECTION OUTPUT ;
    USE SIGNAL ;
    PORT
      LAYER M7 ;
        RECT  77.632 75.931 77.664 76 ;
    END
  END dout[579]
  PIN dout[57]
    DIRECTION OUTPUT ;
    USE SIGNAL ;
    PORT
      LAYER M5 ;
        RECT  26.928 75.916 26.952 76 ;
    END
  END dout[57]
  PIN dout[580]
    DIRECTION OUTPUT ;
    USE SIGNAL ;
    PORT
      LAYER M5 ;
        RECT  71.184 75.916 71.208 76 ;
    END
  END dout[580]
  PIN dout[581]
    DIRECTION OUTPUT ;
    USE SIGNAL ;
    PORT
      LAYER M5 ;
        RECT  76.272 75.916 76.296 76 ;
    END
  END dout[581]
  PIN dout[582]
    DIRECTION OUTPUT ;
    USE SIGNAL ;
    PORT
      LAYER M7 ;
        RECT  79.808 75.931 79.84 76 ;
    END
  END dout[582]
  PIN dout[583]
    DIRECTION OUTPUT ;
    USE SIGNAL ;
    PORT
      LAYER M5 ;
        RECT  73.2 75.916 73.224 76 ;
    END
  END dout[583]
  PIN dout[584]
    DIRECTION OUTPUT ;
    USE SIGNAL ;
    PORT
      LAYER M5 ;
        RECT  71.376 75.916 71.4 76 ;
    END
  END dout[584]
  PIN dout[585]
    DIRECTION OUTPUT ;
    USE SIGNAL ;
    PORT
      LAYER M5 ;
        RECT  74.784 75.916 74.808 76 ;
    END
  END dout[585]
  PIN dout[586]
    DIRECTION OUTPUT ;
    USE SIGNAL ;
    PORT
      LAYER M5 ;
        RECT  72.768 75.916 72.792 76 ;
    END
  END dout[586]
  PIN dout[587]
    DIRECTION OUTPUT ;
    USE SIGNAL ;
    PORT
      LAYER M5 ;
        RECT  72.864 75.916 72.888 76 ;
    END
  END dout[587]
  PIN dout[588]
    DIRECTION OUTPUT ;
    USE SIGNAL ;
    PORT
      LAYER M7 ;
        RECT  77.888 75.931 77.92 76 ;
    END
  END dout[588]
  PIN dout[589]
    DIRECTION OUTPUT ;
    USE SIGNAL ;
    PORT
      LAYER M5 ;
        RECT  66.336 75.916 66.36 76 ;
    END
  END dout[589]
  PIN dout[58]
    DIRECTION OUTPUT ;
    USE SIGNAL ;
    PORT
      LAYER M5 ;
        RECT  6.432 75.916 6.456 76 ;
    END
  END dout[58]
  PIN dout[590]
    DIRECTION OUTPUT ;
    USE SIGNAL ;
    PORT
      LAYER M5 ;
        RECT  73.824 75.916 73.848 76 ;
    END
  END dout[590]
  PIN dout[591]
    DIRECTION OUTPUT ;
    USE SIGNAL ;
    PORT
      LAYER M5 ;
        RECT  69.408 75.916 69.432 76 ;
    END
  END dout[591]
  PIN dout[592]
    DIRECTION OUTPUT ;
    USE SIGNAL ;
    PORT
      LAYER M5 ;
        RECT  65.328 75.916 65.352 76 ;
    END
  END dout[592]
  PIN dout[593]
    DIRECTION OUTPUT ;
    USE SIGNAL ;
    PORT
      LAYER M5 ;
        RECT  67.152 75.916 67.176 76 ;
    END
  END dout[593]
  PIN dout[594]
    DIRECTION OUTPUT ;
    USE SIGNAL ;
    PORT
      LAYER M5 ;
        RECT  70.752 75.916 70.776 76 ;
    END
  END dout[594]
  PIN dout[595]
    DIRECTION OUTPUT ;
    USE SIGNAL ;
    PORT
      LAYER M5 ;
        RECT  72.24 75.916 72.264 76 ;
    END
  END dout[595]
  PIN dout[596]
    DIRECTION OUTPUT ;
    USE SIGNAL ;
    PORT
      LAYER M7 ;
        RECT  76.48 75.931 76.512 76 ;
    END
  END dout[596]
  PIN dout[597]
    DIRECTION OUTPUT ;
    USE SIGNAL ;
    PORT
      LAYER M7 ;
        RECT  64.512 75.931 64.544 76 ;
    END
  END dout[597]
  PIN dout[598]
    DIRECTION OUTPUT ;
    USE SIGNAL ;
    PORT
      LAYER M5 ;
        RECT  66.432 75.916 66.456 76 ;
    END
  END dout[598]
  PIN dout[599]
    DIRECTION OUTPUT ;
    USE SIGNAL ;
    PORT
      LAYER M5 ;
        RECT  67.488 75.916 67.512 76 ;
    END
  END dout[599]
  PIN dout[59]
    DIRECTION OUTPUT ;
    USE SIGNAL ;
    PORT
      LAYER M7 ;
        RECT  13.248 75.931 13.28 76 ;
    END
  END dout[59]
  PIN dout[5]
    DIRECTION OUTPUT ;
    USE SIGNAL ;
    PORT
      LAYER M5 ;
        RECT  36.192 75.916 36.216 76 ;
    END
  END dout[5]
  PIN dout[600]
    DIRECTION OUTPUT ;
    USE SIGNAL ;
    PORT
      LAYER M5 ;
        RECT  68.832 75.916 68.856 76 ;
    END
  END dout[600]
  PIN dout[601]
    DIRECTION OUTPUT ;
    USE SIGNAL ;
    PORT
      LAYER M7 ;
        RECT  65.024 75.931 65.056 76 ;
    END
  END dout[601]
  PIN dout[602]
    DIRECTION OUTPUT ;
    USE SIGNAL ;
    PORT
      LAYER M5 ;
        RECT  67.104 75.916 67.128 76 ;
    END
  END dout[602]
  PIN dout[603]
    DIRECTION OUTPUT ;
    USE SIGNAL ;
    PORT
      LAYER M5 ;
        RECT  73.44 75.916 73.464 76 ;
    END
  END dout[603]
  PIN dout[604]
    DIRECTION OUTPUT ;
    USE SIGNAL ;
    PORT
      LAYER M7 ;
        RECT  62.784 75.931 62.816 76 ;
    END
  END dout[604]
  PIN dout[605]
    DIRECTION OUTPUT ;
    USE SIGNAL ;
    PORT
      LAYER M5 ;
        RECT  71.712 75.916 71.736 76 ;
    END
  END dout[605]
  PIN dout[606]
    DIRECTION OUTPUT ;
    USE SIGNAL ;
    PORT
      LAYER M5 ;
        RECT  58.848 75.916 58.872 76 ;
    END
  END dout[606]
  PIN dout[607]
    DIRECTION OUTPUT ;
    USE SIGNAL ;
    PORT
      LAYER M5 ;
        RECT  70.224 75.916 70.248 76 ;
    END
  END dout[607]
  PIN dout[608]
    DIRECTION OUTPUT ;
    USE SIGNAL ;
    PORT
      LAYER M7 ;
        RECT  77.504 75.931 77.536 76 ;
    END
  END dout[608]
  PIN dout[609]
    DIRECTION OUTPUT ;
    USE SIGNAL ;
    PORT
      LAYER M7 ;
        RECT  63.232 75.931 63.264 76 ;
    END
  END dout[609]
  PIN dout[60]
    DIRECTION OUTPUT ;
    USE SIGNAL ;
    PORT
      LAYER M5 ;
        RECT  8.88 75.916 8.904 76 ;
    END
  END dout[60]
  PIN dout[610]
    DIRECTION OUTPUT ;
    USE SIGNAL ;
    PORT
      LAYER M5 ;
        RECT  59.376 75.916 59.4 76 ;
    END
  END dout[610]
  PIN dout[611]
    DIRECTION OUTPUT ;
    USE SIGNAL ;
    PORT
      LAYER M7 ;
        RECT  50.688 75.931 50.72 76 ;
    END
  END dout[611]
  PIN dout[612]
    DIRECTION OUTPUT ;
    USE SIGNAL ;
    PORT
      LAYER M7 ;
        RECT  80.896 75.931 80.928 76 ;
    END
  END dout[612]
  PIN dout[613]
    DIRECTION OUTPUT ;
    USE SIGNAL ;
    PORT
      LAYER M5 ;
        RECT  66.48 75.916 66.504 76 ;
    END
  END dout[613]
  PIN dout[614]
    DIRECTION OUTPUT ;
    USE SIGNAL ;
    PORT
      LAYER M5 ;
        RECT  60.288 75.916 60.312 76 ;
    END
  END dout[614]
  PIN dout[615]
    DIRECTION OUTPUT ;
    USE SIGNAL ;
    PORT
      LAYER M5 ;
        RECT  72.528 75.916 72.552 76 ;
    END
  END dout[615]
  PIN dout[616]
    DIRECTION OUTPUT ;
    USE SIGNAL ;
    PORT
      LAYER M5 ;
        RECT  66.288 75.916 66.312 76 ;
    END
  END dout[616]
  PIN dout[617]
    DIRECTION OUTPUT ;
    USE SIGNAL ;
    PORT
      LAYER M5 ;
        RECT  54.816 75.916 54.84 76 ;
    END
  END dout[617]
  PIN dout[618]
    DIRECTION OUTPUT ;
    USE SIGNAL ;
    PORT
      LAYER M5 ;
        RECT  72.576 75.916 72.6 76 ;
    END
  END dout[618]
  PIN dout[619]
    DIRECTION OUTPUT ;
    USE SIGNAL ;
    PORT
      LAYER M5 ;
        RECT  71.424 75.916 71.448 76 ;
    END
  END dout[619]
  PIN dout[61]
    DIRECTION OUTPUT ;
    USE SIGNAL ;
    PORT
      LAYER M5 ;
        RECT  6.144 75.916 6.168 76 ;
    END
  END dout[61]
  PIN dout[620]
    DIRECTION OUTPUT ;
    USE SIGNAL ;
    PORT
      LAYER M5 ;
        RECT  74.256 75.916 74.28 76 ;
    END
  END dout[620]
  PIN dout[621]
    DIRECTION OUTPUT ;
    USE SIGNAL ;
    PORT
      LAYER M5 ;
        RECT  72.432 75.916 72.456 76 ;
    END
  END dout[621]
  PIN dout[622]
    DIRECTION OUTPUT ;
    USE SIGNAL ;
    PORT
      LAYER M5 ;
        RECT  45.792 75.916 45.816 76 ;
    END
  END dout[622]
  PIN dout[623]
    DIRECTION OUTPUT ;
    USE SIGNAL ;
    PORT
      LAYER M5 ;
        RECT  74.352 75.916 74.376 76 ;
    END
  END dout[623]
  PIN dout[624]
    DIRECTION OUTPUT ;
    USE SIGNAL ;
    PORT
      LAYER M5 ;
        RECT  74.016 75.916 74.04 76 ;
    END
  END dout[624]
  PIN dout[625]
    DIRECTION OUTPUT ;
    USE SIGNAL ;
    PORT
      LAYER M5 ;
        RECT  65.232 75.916 65.256 76 ;
    END
  END dout[625]
  PIN dout[626]
    DIRECTION OUTPUT ;
    USE SIGNAL ;
    PORT
      LAYER M5 ;
        RECT  34.608 75.916 34.632 76 ;
    END
  END dout[626]
  PIN dout[627]
    DIRECTION OUTPUT ;
    USE SIGNAL ;
    PORT
      LAYER M7 ;
        RECT  60.928 75.931 60.96 76 ;
    END
  END dout[627]
  PIN dout[628]
    DIRECTION OUTPUT ;
    USE SIGNAL ;
    PORT
      LAYER M5 ;
        RECT  66.24 75.916 66.264 76 ;
    END
  END dout[628]
  PIN dout[629]
    DIRECTION OUTPUT ;
    USE SIGNAL ;
    PORT
      LAYER M5 ;
        RECT  47.328 75.916 47.352 76 ;
    END
  END dout[629]
  PIN dout[62]
    DIRECTION OUTPUT ;
    USE SIGNAL ;
    PORT
      LAYER M7 ;
        RECT  4.224 75.931 4.256 76 ;
    END
  END dout[62]
  PIN dout[630]
    DIRECTION OUTPUT ;
    USE SIGNAL ;
    PORT
      LAYER M5 ;
        RECT  70.608 75.916 70.632 76 ;
    END
  END dout[630]
  PIN dout[631]
    DIRECTION OUTPUT ;
    USE SIGNAL ;
    PORT
      LAYER M5 ;
        RECT  66.048 75.916 66.072 76 ;
    END
  END dout[631]
  PIN dout[632]
    DIRECTION OUTPUT ;
    USE SIGNAL ;
    PORT
      LAYER M5 ;
        RECT  66.864 75.916 66.888 76 ;
    END
  END dout[632]
  PIN dout[633]
    DIRECTION OUTPUT ;
    USE SIGNAL ;
    PORT
      LAYER M7 ;
        RECT  42.304 75.931 42.336 76 ;
    END
  END dout[633]
  PIN dout[634]
    DIRECTION OUTPUT ;
    USE SIGNAL ;
    PORT
      LAYER M7 ;
        RECT  41.6 75.931 41.632 76 ;
    END
  END dout[634]
  PIN dout[635]
    DIRECTION OUTPUT ;
    USE SIGNAL ;
    PORT
      LAYER M5 ;
        RECT  42.768 75.916 42.792 76 ;
    END
  END dout[635]
  PIN dout[636]
    DIRECTION OUTPUT ;
    USE SIGNAL ;
    PORT
      LAYER M7 ;
        RECT  41.216 75.931 41.248 76 ;
    END
  END dout[636]
  PIN dout[637]
    DIRECTION OUTPUT ;
    USE SIGNAL ;
    PORT
      LAYER M7 ;
        RECT  49.92 75.931 49.952 76 ;
    END
  END dout[637]
  PIN dout[638]
    DIRECTION OUTPUT ;
    USE SIGNAL ;
    PORT
      LAYER M7 ;
        RECT  41.088 75.931 41.12 76 ;
    END
  END dout[638]
  PIN dout[639]
    DIRECTION OUTPUT ;
    USE SIGNAL ;
    PORT
      LAYER M5 ;
        RECT  44.736 75.916 44.76 76 ;
    END
  END dout[639]
  PIN dout[63]
    DIRECTION OUTPUT ;
    USE SIGNAL ;
    PORT
      LAYER M7 ;
        RECT  3.328 75.931 3.36 76 ;
    END
  END dout[63]
  PIN dout[640]
    DIRECTION OUTPUT ;
    USE SIGNAL ;
    PORT
      LAYER M5 ;
        RECT  72.288 75.916 72.312 76 ;
    END
  END dout[640]
  PIN dout[641]
    DIRECTION OUTPUT ;
    USE SIGNAL ;
    PORT
      LAYER M7 ;
        RECT  65.088 75.931 65.12 76 ;
    END
  END dout[641]
  PIN dout[642]
    DIRECTION OUTPUT ;
    USE SIGNAL ;
    PORT
      LAYER M5 ;
        RECT  72.048 75.916 72.072 76 ;
    END
  END dout[642]
  PIN dout[643]
    DIRECTION OUTPUT ;
    USE SIGNAL ;
    PORT
      LAYER M5 ;
        RECT  58.224 75.916 58.248 76 ;
    END
  END dout[643]
  PIN dout[644]
    DIRECTION OUTPUT ;
    USE SIGNAL ;
    PORT
      LAYER M5 ;
        RECT  71.28 75.916 71.304 76 ;
    END
  END dout[644]
  PIN dout[645]
    DIRECTION OUTPUT ;
    USE SIGNAL ;
    PORT
      LAYER M7 ;
        RECT  63.104 75.931 63.136 76 ;
    END
  END dout[645]
  PIN dout[646]
    DIRECTION OUTPUT ;
    USE SIGNAL ;
    PORT
      LAYER M7 ;
        RECT  61.248 75.931 61.28 76 ;
    END
  END dout[646]
  PIN dout[647]
    DIRECTION OUTPUT ;
    USE SIGNAL ;
    PORT
      LAYER M5 ;
        RECT  71.136 75.916 71.16 76 ;
    END
  END dout[647]
  PIN dout[648]
    DIRECTION OUTPUT ;
    USE SIGNAL ;
    PORT
      LAYER M7 ;
        RECT  63.424 75.931 63.456 76 ;
    END
  END dout[648]
  PIN dout[649]
    DIRECTION OUTPUT ;
    USE SIGNAL ;
    PORT
      LAYER M5 ;
        RECT  65.376 75.916 65.4 76 ;
    END
  END dout[649]
  PIN dout[64]
    DIRECTION OUTPUT ;
    USE SIGNAL ;
    PORT
      LAYER M5 ;
        RECT  71.088 75.916 71.112 76 ;
    END
  END dout[64]
  PIN dout[650]
    DIRECTION OUTPUT ;
    USE SIGNAL ;
    PORT
      LAYER M5 ;
        RECT  72.144 75.916 72.168 76 ;
    END
  END dout[650]
  PIN dout[651]
    DIRECTION OUTPUT ;
    USE SIGNAL ;
    PORT
      LAYER M5 ;
        RECT  71.664 75.916 71.688 76 ;
    END
  END dout[651]
  PIN dout[652]
    DIRECTION OUTPUT ;
    USE SIGNAL ;
    PORT
      LAYER M5 ;
        RECT  67.632 75.916 67.656 76 ;
    END
  END dout[652]
  PIN dout[653]
    DIRECTION OUTPUT ;
    USE SIGNAL ;
    PORT
      LAYER M5 ;
        RECT  68.592 75.916 68.616 76 ;
    END
  END dout[653]
  PIN dout[654]
    DIRECTION OUTPUT ;
    USE SIGNAL ;
    PORT
      LAYER M7 ;
        RECT  60.8 75.931 60.832 76 ;
    END
  END dout[654]
  PIN dout[655]
    DIRECTION OUTPUT ;
    USE SIGNAL ;
    PORT
      LAYER M5 ;
        RECT  70.176 75.916 70.2 76 ;
    END
  END dout[655]
  PIN dout[656]
    DIRECTION OUTPUT ;
    USE SIGNAL ;
    PORT
      LAYER M5 ;
        RECT  66.72 75.916 66.744 76 ;
    END
  END dout[656]
  PIN dout[657]
    DIRECTION OUTPUT ;
    USE SIGNAL ;
    PORT
      LAYER M5 ;
        RECT  68.736 75.916 68.76 76 ;
    END
  END dout[657]
  PIN dout[658]
    DIRECTION OUTPUT ;
    USE SIGNAL ;
    PORT
      LAYER M5 ;
        RECT  67.968 75.916 67.992 76 ;
    END
  END dout[658]
  PIN dout[659]
    DIRECTION OUTPUT ;
    USE SIGNAL ;
    PORT
      LAYER M5 ;
        RECT  68.976 75.916 69 76 ;
    END
  END dout[659]
  PIN dout[65]
    DIRECTION OUTPUT ;
    USE SIGNAL ;
    PORT
      LAYER M5 ;
        RECT  70.656 75.916 70.68 76 ;
    END
  END dout[65]
  PIN dout[660]
    DIRECTION OUTPUT ;
    USE SIGNAL ;
    PORT
      LAYER M5 ;
        RECT  69.6 75.916 69.624 76 ;
    END
  END dout[660]
  PIN dout[661]
    DIRECTION OUTPUT ;
    USE SIGNAL ;
    PORT
      LAYER M5 ;
        RECT  70.416 75.916 70.44 76 ;
    END
  END dout[661]
  PIN dout[662]
    DIRECTION OUTPUT ;
    USE SIGNAL ;
    PORT
      LAYER M7 ;
        RECT  64.64 75.931 64.672 76 ;
    END
  END dout[662]
  PIN dout[663]
    DIRECTION OUTPUT ;
    USE SIGNAL ;
    PORT
      LAYER M5 ;
        RECT  65.856 75.916 65.88 76 ;
    END
  END dout[663]
  PIN dout[664]
    DIRECTION OUTPUT ;
    USE SIGNAL ;
    PORT
      LAYER M5 ;
        RECT  69.888 75.916 69.912 76 ;
    END
  END dout[664]
  PIN dout[665]
    DIRECTION OUTPUT ;
    USE SIGNAL ;
    PORT
      LAYER M5 ;
        RECT  56.352 75.916 56.376 76 ;
    END
  END dout[665]
  PIN dout[666]
    DIRECTION OUTPUT ;
    USE SIGNAL ;
    PORT
      LAYER M5 ;
        RECT  57.456 75.916 57.48 76 ;
    END
  END dout[666]
  PIN dout[667]
    DIRECTION OUTPUT ;
    USE SIGNAL ;
    PORT
      LAYER M5 ;
        RECT  59.856 75.916 59.88 76 ;
    END
  END dout[667]
  PIN dout[668]
    DIRECTION OUTPUT ;
    USE SIGNAL ;
    PORT
      LAYER M5 ;
        RECT  60.384 75.916 60.408 76 ;
    END
  END dout[668]
  PIN dout[669]
    DIRECTION OUTPUT ;
    USE SIGNAL ;
    PORT
      LAYER M7 ;
        RECT  51.648 75.931 51.68 76 ;
    END
  END dout[669]
  PIN dout[66]
    DIRECTION OUTPUT ;
    USE SIGNAL ;
    PORT
      LAYER M5 ;
        RECT  71.76 75.916 71.784 76 ;
    END
  END dout[66]
  PIN dout[670]
    DIRECTION OUTPUT ;
    USE SIGNAL ;
    PORT
      LAYER M5 ;
        RECT  59.616 75.916 59.64 76 ;
    END
  END dout[670]
  PIN dout[671]
    DIRECTION OUTPUT ;
    USE SIGNAL ;
    PORT
      LAYER M5 ;
        RECT  56.4 75.916 56.424 76 ;
    END
  END dout[671]
  PIN dout[672]
    DIRECTION OUTPUT ;
    USE SIGNAL ;
    PORT
      LAYER M7 ;
        RECT  53.696 75.931 53.728 76 ;
    END
  END dout[672]
  PIN dout[673]
    DIRECTION OUTPUT ;
    USE SIGNAL ;
    PORT
      LAYER M5 ;
        RECT  66.576 75.916 66.6 76 ;
    END
  END dout[673]
  PIN dout[674]
    DIRECTION OUTPUT ;
    USE SIGNAL ;
    PORT
      LAYER M7 ;
        RECT  50.432 75.931 50.464 76 ;
    END
  END dout[674]
  PIN dout[675]
    DIRECTION OUTPUT ;
    USE SIGNAL ;
    PORT
      LAYER M5 ;
        RECT  43.44 75.916 43.464 76 ;
    END
  END dout[675]
  PIN dout[676]
    DIRECTION OUTPUT ;
    USE SIGNAL ;
    PORT
      LAYER M5 ;
        RECT  46.608 75.916 46.632 76 ;
    END
  END dout[676]
  PIN dout[677]
    DIRECTION OUTPUT ;
    USE SIGNAL ;
    PORT
      LAYER M5 ;
        RECT  44.112 75.916 44.136 76 ;
    END
  END dout[677]
  PIN dout[678]
    DIRECTION OUTPUT ;
    USE SIGNAL ;
    PORT
      LAYER M5 ;
        RECT  55.68 75.916 55.704 76 ;
    END
  END dout[678]
  PIN dout[679]
    DIRECTION OUTPUT ;
    USE SIGNAL ;
    PORT
      LAYER M5 ;
        RECT  46.752 75.916 46.776 76 ;
    END
  END dout[679]
  PIN dout[67]
    DIRECTION OUTPUT ;
    USE SIGNAL ;
    PORT
      LAYER M7 ;
        RECT  77.696 75.931 77.728 76 ;
    END
  END dout[67]
  PIN dout[680]
    DIRECTION OUTPUT ;
    USE SIGNAL ;
    PORT
      LAYER M7 ;
        RECT  49.152 75.931 49.184 76 ;
    END
  END dout[680]
  PIN dout[681]
    DIRECTION OUTPUT ;
    USE SIGNAL ;
    PORT
      LAYER M7 ;
        RECT  50.56 75.931 50.592 76 ;
    END
  END dout[681]
  PIN dout[682]
    DIRECTION OUTPUT ;
    USE SIGNAL ;
    PORT
      LAYER M5 ;
        RECT  48.192 75.916 48.216 76 ;
    END
  END dout[682]
  PIN dout[683]
    DIRECTION OUTPUT ;
    USE SIGNAL ;
    PORT
      LAYER M5 ;
        RECT  54.528 75.916 54.552 76 ;
    END
  END dout[683]
  PIN dout[684]
    DIRECTION OUTPUT ;
    USE SIGNAL ;
    PORT
      LAYER M7 ;
        RECT  49.216 75.931 49.248 76 ;
    END
  END dout[684]
  PIN dout[685]
    DIRECTION OUTPUT ;
    USE SIGNAL ;
    PORT
      LAYER M5 ;
        RECT  44.304 75.916 44.328 76 ;
    END
  END dout[685]
  PIN dout[686]
    DIRECTION OUTPUT ;
    USE SIGNAL ;
    PORT
      LAYER M5 ;
        RECT  35.952 75.916 35.976 76 ;
    END
  END dout[686]
  PIN dout[687]
    DIRECTION OUTPUT ;
    USE SIGNAL ;
    PORT
      LAYER M7 ;
        RECT  41.536 75.931 41.568 76 ;
    END
  END dout[687]
  PIN dout[688]
    DIRECTION OUTPUT ;
    USE SIGNAL ;
    PORT
      LAYER M5 ;
        RECT  35.712 75.916 35.736 76 ;
    END
  END dout[688]
  PIN dout[689]
    DIRECTION OUTPUT ;
    USE SIGNAL ;
    PORT
      LAYER M5 ;
        RECT  67.536 75.916 67.56 76 ;
    END
  END dout[689]
  PIN dout[68]
    DIRECTION OUTPUT ;
    USE SIGNAL ;
    PORT
      LAYER M5 ;
        RECT  71.232 75.916 71.256 76 ;
    END
  END dout[68]
  PIN dout[690]
    DIRECTION OUTPUT ;
    USE SIGNAL ;
    PORT
      LAYER M7 ;
        RECT  53.312 75.931 53.344 76 ;
    END
  END dout[690]
  PIN dout[691]
    DIRECTION OUTPUT ;
    USE SIGNAL ;
    PORT
      LAYER M5 ;
        RECT  48.336 75.916 48.36 76 ;
    END
  END dout[691]
  PIN dout[692]
    DIRECTION OUTPUT ;
    USE SIGNAL ;
    PORT
      LAYER M5 ;
        RECT  37.488 75.916 37.512 76 ;
    END
  END dout[692]
  PIN dout[693]
    DIRECTION OUTPUT ;
    USE SIGNAL ;
    PORT
      LAYER M5 ;
        RECT  70.944 75.916 70.968 76 ;
    END
  END dout[693]
  PIN dout[694]
    DIRECTION OUTPUT ;
    USE SIGNAL ;
    PORT
      LAYER M5 ;
        RECT  43.152 75.916 43.176 76 ;
    END
  END dout[694]
  PIN dout[695]
    DIRECTION OUTPUT ;
    USE SIGNAL ;
    PORT
      LAYER M5 ;
        RECT  73.536 75.916 73.56 76 ;
    END
  END dout[695]
  PIN dout[696]
    DIRECTION OUTPUT ;
    USE SIGNAL ;
    PORT
      LAYER M5 ;
        RECT  71.904 75.916 71.928 76 ;
    END
  END dout[696]
  PIN dout[697]
    DIRECTION OUTPUT ;
    USE SIGNAL ;
    PORT
      LAYER M5 ;
        RECT  36.096 75.916 36.12 76 ;
    END
  END dout[697]
  PIN dout[698]
    DIRECTION OUTPUT ;
    USE SIGNAL ;
    PORT
      LAYER M5 ;
        RECT  34.08 75.916 34.104 76 ;
    END
  END dout[698]
  PIN dout[699]
    DIRECTION OUTPUT ;
    USE SIGNAL ;
    PORT
      LAYER M7 ;
        RECT  63.68 75.931 63.712 76 ;
    END
  END dout[699]
  PIN dout[69]
    DIRECTION OUTPUT ;
    USE SIGNAL ;
    PORT
      LAYER M5 ;
        RECT  76.224 75.916 76.248 76 ;
    END
  END dout[69]
  PIN dout[6]
    DIRECTION OUTPUT ;
    USE SIGNAL ;
    PORT
      LAYER M7 ;
        RECT  39.232 75.931 39.264 76 ;
    END
  END dout[6]
  PIN dout[700]
    DIRECTION OUTPUT ;
    USE SIGNAL ;
    PORT
      LAYER M5 ;
        RECT  73.008 75.916 73.032 76 ;
    END
  END dout[700]
  PIN dout[701]
    DIRECTION OUTPUT ;
    USE SIGNAL ;
    PORT
      LAYER M5 ;
        RECT  36.432 75.916 36.456 76 ;
    END
  END dout[701]
  PIN dout[702]
    DIRECTION OUTPUT ;
    USE SIGNAL ;
    PORT
      LAYER M5 ;
        RECT  72.336 75.916 72.36 76 ;
    END
  END dout[702]
  PIN dout[703]
    DIRECTION OUTPUT ;
    USE SIGNAL ;
    PORT
      LAYER M5 ;
        RECT  72.672 75.916 72.696 76 ;
    END
  END dout[703]
  PIN dout[704]
    DIRECTION OUTPUT ;
    USE SIGNAL ;
    PORT
      LAYER M7 ;
        RECT  23.488 75.931 23.52 76 ;
    END
  END dout[704]
  PIN dout[705]
    DIRECTION OUTPUT ;
    USE SIGNAL ;
    PORT
      LAYER M5 ;
        RECT  9.504 75.916 9.528 76 ;
    END
  END dout[705]
  PIN dout[706]
    DIRECTION OUTPUT ;
    USE SIGNAL ;
    PORT
      LAYER M5 ;
        RECT  21.072 75.916 21.096 76 ;
    END
  END dout[706]
  PIN dout[707]
    DIRECTION OUTPUT ;
    USE SIGNAL ;
    PORT
      LAYER M5 ;
        RECT  9.216 75.916 9.24 76 ;
    END
  END dout[707]
  PIN dout[708]
    DIRECTION OUTPUT ;
    USE SIGNAL ;
    PORT
      LAYER M5 ;
        RECT  16.32 75.916 16.344 76 ;
    END
  END dout[708]
  PIN dout[709]
    DIRECTION OUTPUT ;
    USE SIGNAL ;
    PORT
      LAYER M5 ;
        RECT  6.864 75.916 6.888 76 ;
    END
  END dout[709]
  PIN dout[70]
    DIRECTION OUTPUT ;
    USE SIGNAL ;
    PORT
      LAYER M7 ;
        RECT  79.744 75.931 79.776 76 ;
    END
  END dout[70]
  PIN dout[710]
    DIRECTION OUTPUT ;
    USE SIGNAL ;
    PORT
      LAYER M7 ;
        RECT  22.72 75.931 22.752 76 ;
    END
  END dout[710]
  PIN dout[711]
    DIRECTION OUTPUT ;
    USE SIGNAL ;
    PORT
      LAYER M5 ;
        RECT  32.256 75.916 32.28 76 ;
    END
  END dout[711]
  PIN dout[712]
    DIRECTION OUTPUT ;
    USE SIGNAL ;
    PORT
      LAYER M5 ;
        RECT  26.976 75.916 27 76 ;
    END
  END dout[712]
  PIN dout[713]
    DIRECTION OUTPUT ;
    USE SIGNAL ;
    PORT
      LAYER M5 ;
        RECT  27.696 75.916 27.72 76 ;
    END
  END dout[713]
  PIN dout[714]
    DIRECTION OUTPUT ;
    USE SIGNAL ;
    PORT
      LAYER M5 ;
        RECT  21.024 75.916 21.048 76 ;
    END
  END dout[714]
  PIN dout[715]
    DIRECTION OUTPUT ;
    USE SIGNAL ;
    PORT
      LAYER M7 ;
        RECT  23.232 75.931 23.264 76 ;
    END
  END dout[715]
  PIN dout[716]
    DIRECTION OUTPUT ;
    USE SIGNAL ;
    PORT
      LAYER M5 ;
        RECT  6.96 75.916 6.984 76 ;
    END
  END dout[716]
  PIN dout[717]
    DIRECTION OUTPUT ;
    USE SIGNAL ;
    PORT
      LAYER M7 ;
        RECT  12.352 75.931 12.384 76 ;
    END
  END dout[717]
  PIN dout[718]
    DIRECTION OUTPUT ;
    USE SIGNAL ;
    PORT
      LAYER M5 ;
        RECT  7.872 75.916 7.896 76 ;
    END
  END dout[718]
  PIN dout[719]
    DIRECTION OUTPUT ;
    USE SIGNAL ;
    PORT
      LAYER M7 ;
        RECT  14.72 75.931 14.752 76 ;
    END
  END dout[719]
  PIN dout[71]
    DIRECTION OUTPUT ;
    USE SIGNAL ;
    PORT
      LAYER M5 ;
        RECT  73.248 75.916 73.272 76 ;
    END
  END dout[71]
  PIN dout[720]
    DIRECTION OUTPUT ;
    USE SIGNAL ;
    PORT
      LAYER M7 ;
        RECT  5.888 75.931 5.92 76 ;
    END
  END dout[720]
  PIN dout[721]
    DIRECTION OUTPUT ;
    USE SIGNAL ;
    PORT
      LAYER M7 ;
        RECT  14.912 75.931 14.944 76 ;
    END
  END dout[721]
  PIN dout[722]
    DIRECTION OUTPUT ;
    USE SIGNAL ;
    PORT
      LAYER M7 ;
        RECT  3.776 75.931 3.808 76 ;
    END
  END dout[722]
  PIN dout[723]
    DIRECTION OUTPUT ;
    USE SIGNAL ;
    PORT
      LAYER M5 ;
        RECT  10.32 75.916 10.344 76 ;
    END
  END dout[723]
  PIN dout[724]
    DIRECTION OUTPUT ;
    USE SIGNAL ;
    PORT
      LAYER M7 ;
        RECT  12.224 75.931 12.256 76 ;
    END
  END dout[724]
  PIN dout[725]
    DIRECTION OUTPUT ;
    USE SIGNAL ;
    PORT
      LAYER M5 ;
        RECT  10.08 75.916 10.104 76 ;
    END
  END dout[725]
  PIN dout[726]
    DIRECTION OUTPUT ;
    USE SIGNAL ;
    PORT
      LAYER M7 ;
        RECT  10.88 75.931 10.912 76 ;
    END
  END dout[726]
  PIN dout[727]
    DIRECTION OUTPUT ;
    USE SIGNAL ;
    PORT
      LAYER M5 ;
        RECT  7.824 75.916 7.848 76 ;
    END
  END dout[727]
  PIN dout[728]
    DIRECTION OUTPUT ;
    USE SIGNAL ;
    PORT
      LAYER M5 ;
        RECT  29.136 75.916 29.16 76 ;
    END
  END dout[728]
  PIN dout[729]
    DIRECTION OUTPUT ;
    USE SIGNAL ;
    PORT
      LAYER M5 ;
        RECT  10.8 75.916 10.824 76 ;
    END
  END dout[729]
  PIN dout[72]
    DIRECTION OUTPUT ;
    USE SIGNAL ;
    PORT
      LAYER M5 ;
        RECT  71.472 75.916 71.496 76 ;
    END
  END dout[72]
  PIN dout[730]
    DIRECTION OUTPUT ;
    USE SIGNAL ;
    PORT
      LAYER M7 ;
        RECT  24.832 75.931 24.864 76 ;
    END
  END dout[730]
  PIN dout[731]
    DIRECTION OUTPUT ;
    USE SIGNAL ;
    PORT
      LAYER M5 ;
        RECT  18.048 75.916 18.072 76 ;
    END
  END dout[731]
  PIN dout[732]
    DIRECTION OUTPUT ;
    USE SIGNAL ;
    PORT
      LAYER M5 ;
        RECT  16.848 75.916 16.872 76 ;
    END
  END dout[732]
  PIN dout[733]
    DIRECTION OUTPUT ;
    USE SIGNAL ;
    PORT
      LAYER M7 ;
        RECT  11.328 75.931 11.36 76 ;
    END
  END dout[733]
  PIN dout[734]
    DIRECTION OUTPUT ;
    USE SIGNAL ;
    PORT
      LAYER M5 ;
        RECT  33.024 75.916 33.048 76 ;
    END
  END dout[734]
  PIN dout[735]
    DIRECTION OUTPUT ;
    USE SIGNAL ;
    PORT
      LAYER M7 ;
        RECT  14.208 75.931 14.24 76 ;
    END
  END dout[735]
  PIN dout[736]
    DIRECTION OUTPUT ;
    USE SIGNAL ;
    PORT
      LAYER M5 ;
        RECT  18.912 75.916 18.936 76 ;
    END
  END dout[736]
  PIN dout[737]
    DIRECTION OUTPUT ;
    USE SIGNAL ;
    PORT
      LAYER M5 ;
        RECT  31.92 75.916 31.944 76 ;
    END
  END dout[737]
  PIN dout[738]
    DIRECTION OUTPUT ;
    USE SIGNAL ;
    PORT
      LAYER M5 ;
        RECT  28.656 75.916 28.68 76 ;
    END
  END dout[738]
  PIN dout[739]
    DIRECTION OUTPUT ;
    USE SIGNAL ;
    PORT
      LAYER M5 ;
        RECT  15.984 75.916 16.008 76 ;
    END
  END dout[739]
  PIN dout[73]
    DIRECTION OUTPUT ;
    USE SIGNAL ;
    PORT
      LAYER M5 ;
        RECT  74.832 75.916 74.856 76 ;
    END
  END dout[73]
  PIN dout[740]
    DIRECTION OUTPUT ;
    USE SIGNAL ;
    PORT
      LAYER M5 ;
        RECT  18.24 75.916 18.264 76 ;
    END
  END dout[740]
  PIN dout[741]
    DIRECTION OUTPUT ;
    USE SIGNAL ;
    PORT
      LAYER M5 ;
        RECT  30.384 75.916 30.408 76 ;
    END
  END dout[741]
  PIN dout[742]
    DIRECTION OUTPUT ;
    USE SIGNAL ;
    PORT
      LAYER M5 ;
        RECT  20.832 75.916 20.856 76 ;
    END
  END dout[742]
  PIN dout[743]
    DIRECTION OUTPUT ;
    USE SIGNAL ;
    PORT
      LAYER M5 ;
        RECT  27.6 75.916 27.624 76 ;
    END
  END dout[743]
  PIN dout[744]
    DIRECTION OUTPUT ;
    USE SIGNAL ;
    PORT
      LAYER M5 ;
        RECT  30.864 75.916 30.888 76 ;
    END
  END dout[744]
  PIN dout[745]
    DIRECTION OUTPUT ;
    USE SIGNAL ;
    PORT
      LAYER M5 ;
        RECT  31.2 75.916 31.224 76 ;
    END
  END dout[745]
  PIN dout[746]
    DIRECTION OUTPUT ;
    USE SIGNAL ;
    PORT
      LAYER M5 ;
        RECT  20.064 75.916 20.088 76 ;
    END
  END dout[746]
  PIN dout[747]
    DIRECTION OUTPUT ;
    USE SIGNAL ;
    PORT
      LAYER M7 ;
        RECT  14.336 75.931 14.368 76 ;
    END
  END dout[747]
  PIN dout[748]
    DIRECTION OUTPUT ;
    USE SIGNAL ;
    PORT
      LAYER M5 ;
        RECT  18.144 75.916 18.168 76 ;
    END
  END dout[748]
  PIN dout[749]
    DIRECTION OUTPUT ;
    USE SIGNAL ;
    PORT
      LAYER M7 ;
        RECT  25.024 75.931 25.056 76 ;
    END
  END dout[749]
  PIN dout[74]
    DIRECTION OUTPUT ;
    USE SIGNAL ;
    PORT
      LAYER M5 ;
        RECT  72.816 75.916 72.84 76 ;
    END
  END dout[74]
  PIN dout[750]
    DIRECTION OUTPUT ;
    USE SIGNAL ;
    PORT
      LAYER M5 ;
        RECT  28.896 75.916 28.92 76 ;
    END
  END dout[750]
  PIN dout[751]
    DIRECTION OUTPUT ;
    USE SIGNAL ;
    PORT
      LAYER M5 ;
        RECT  28.752 75.916 28.776 76 ;
    END
  END dout[751]
  PIN dout[752]
    DIRECTION OUTPUT ;
    USE SIGNAL ;
    PORT
      LAYER M7 ;
        RECT  23.168 75.931 23.2 76 ;
    END
  END dout[752]
  PIN dout[753]
    DIRECTION OUTPUT ;
    USE SIGNAL ;
    PORT
      LAYER M5 ;
        RECT  33.552 75.916 33.576 76 ;
    END
  END dout[753]
  PIN dout[754]
    DIRECTION OUTPUT ;
    USE SIGNAL ;
    PORT
      LAYER M7 ;
        RECT  22.464 75.931 22.496 76 ;
    END
  END dout[754]
  PIN dout[755]
    DIRECTION OUTPUT ;
    USE SIGNAL ;
    PORT
      LAYER M5 ;
        RECT  19.824 75.916 19.848 76 ;
    END
  END dout[755]
  PIN dout[756]
    DIRECTION OUTPUT ;
    USE SIGNAL ;
    PORT
      LAYER M7 ;
        RECT  22.592 75.931 22.624 76 ;
    END
  END dout[756]
  PIN dout[757]
    DIRECTION OUTPUT ;
    USE SIGNAL ;
    PORT
      LAYER M5 ;
        RECT  21.888 75.916 21.912 76 ;
    END
  END dout[757]
  PIN dout[758]
    DIRECTION OUTPUT ;
    USE SIGNAL ;
    PORT
      LAYER M7 ;
        RECT  26.56 75.931 26.592 76 ;
    END
  END dout[758]
  PIN dout[759]
    DIRECTION OUTPUT ;
    USE SIGNAL ;
    PORT
      LAYER M5 ;
        RECT  33.264 75.916 33.288 76 ;
    END
  END dout[759]
  PIN dout[75]
    DIRECTION OUTPUT ;
    USE SIGNAL ;
    PORT
      LAYER M5 ;
        RECT  72.48 75.916 72.504 76 ;
    END
  END dout[75]
  PIN dout[760]
    DIRECTION OUTPUT ;
    USE SIGNAL ;
    PORT
      LAYER M5 ;
        RECT  30.336 75.916 30.36 76 ;
    END
  END dout[760]
  PIN dout[761]
    DIRECTION OUTPUT ;
    USE SIGNAL ;
    PORT
      LAYER M5 ;
        RECT  17.664 75.916 17.688 76 ;
    END
  END dout[761]
  PIN dout[762]
    DIRECTION OUTPUT ;
    USE SIGNAL ;
    PORT
      LAYER M7 ;
        RECT  25.728 75.931 25.76 76 ;
    END
  END dout[762]
  PIN dout[763]
    DIRECTION OUTPUT ;
    USE SIGNAL ;
    PORT
      LAYER M7 ;
        RECT  13.696 75.931 13.728 76 ;
    END
  END dout[763]
  PIN dout[764]
    DIRECTION OUTPUT ;
    USE SIGNAL ;
    PORT
      LAYER M7 ;
        RECT  22.272 75.931 22.304 76 ;
    END
  END dout[764]
  PIN dout[765]
    DIRECTION OUTPUT ;
    USE SIGNAL ;
    PORT
      LAYER M7 ;
        RECT  13.12 75.931 13.152 76 ;
    END
  END dout[765]
  PIN dout[766]
    DIRECTION OUTPUT ;
    USE SIGNAL ;
    PORT
      LAYER M7 ;
        RECT  10.944 75.931 10.976 76 ;
    END
  END dout[766]
  PIN dout[767]
    DIRECTION OUTPUT ;
    USE SIGNAL ;
    PORT
      LAYER M5 ;
        RECT  16.464 75.916 16.488 76 ;
    END
  END dout[767]
  PIN dout[768]
    DIRECTION OUTPUT ;
    USE SIGNAL ;
    PORT
      LAYER M5 ;
        RECT  57.6 75.916 57.624 76 ;
    END
  END dout[768]
  PIN dout[769]
    DIRECTION OUTPUT ;
    USE SIGNAL ;
    PORT
      LAYER M5 ;
        RECT  58.752 75.916 58.776 76 ;
    END
  END dout[769]
  PIN dout[76]
    DIRECTION OUTPUT ;
    USE SIGNAL ;
    PORT
      LAYER M7 ;
        RECT  77.824 75.931 77.856 76 ;
    END
  END dout[76]
  PIN dout[770]
    DIRECTION OUTPUT ;
    USE SIGNAL ;
    PORT
      LAYER M5 ;
        RECT  58.992 75.916 59.016 76 ;
    END
  END dout[770]
  PIN dout[771]
    DIRECTION OUTPUT ;
    USE SIGNAL ;
    PORT
      LAYER M5 ;
        RECT  58.944 75.916 58.968 76 ;
    END
  END dout[771]
  PIN dout[772]
    DIRECTION OUTPUT ;
    USE SIGNAL ;
    PORT
      LAYER M5 ;
        RECT  57.264 75.916 57.288 76 ;
    END
  END dout[772]
  PIN dout[773]
    DIRECTION OUTPUT ;
    USE SIGNAL ;
    PORT
      LAYER M5 ;
        RECT  56.496 75.916 56.52 76 ;
    END
  END dout[773]
  PIN dout[774]
    DIRECTION OUTPUT ;
    USE SIGNAL ;
    PORT
      LAYER M5 ;
        RECT  56.736 75.916 56.76 76 ;
    END
  END dout[774]
  PIN dout[775]
    DIRECTION OUTPUT ;
    USE SIGNAL ;
    PORT
      LAYER M5 ;
        RECT  56.784 75.916 56.808 76 ;
    END
  END dout[775]
  PIN dout[776]
    DIRECTION OUTPUT ;
    USE SIGNAL ;
    PORT
      LAYER M5 ;
        RECT  48 75.916 48.024 76 ;
    END
  END dout[776]
  PIN dout[777]
    DIRECTION OUTPUT ;
    USE SIGNAL ;
    PORT
      LAYER M5 ;
        RECT  58.032 75.916 58.056 76 ;
    END
  END dout[777]
  PIN dout[778]
    DIRECTION OUTPUT ;
    USE SIGNAL ;
    PORT
      LAYER M7 ;
        RECT  52.224 75.931 52.256 76 ;
    END
  END dout[778]
  PIN dout[779]
    DIRECTION OUTPUT ;
    USE SIGNAL ;
    PORT
      LAYER M5 ;
        RECT  55.104 75.916 55.128 76 ;
    END
  END dout[779]
  PIN dout[77]
    DIRECTION OUTPUT ;
    USE SIGNAL ;
    PORT
      LAYER M5 ;
        RECT  66.096 75.916 66.12 76 ;
    END
  END dout[77]
  PIN dout[780]
    DIRECTION OUTPUT ;
    USE SIGNAL ;
    PORT
      LAYER M5 ;
        RECT  56.832 75.916 56.856 76 ;
    END
  END dout[780]
  PIN dout[781]
    DIRECTION OUTPUT ;
    USE SIGNAL ;
    PORT
      LAYER M5 ;
        RECT  56.16 75.916 56.184 76 ;
    END
  END dout[781]
  PIN dout[782]
    DIRECTION OUTPUT ;
    USE SIGNAL ;
    PORT
      LAYER M5 ;
        RECT  55.92 75.916 55.944 76 ;
    END
  END dout[782]
  PIN dout[783]
    DIRECTION OUTPUT ;
    USE SIGNAL ;
    PORT
      LAYER M7 ;
        RECT  51.52 75.931 51.552 76 ;
    END
  END dout[783]
  PIN dout[784]
    DIRECTION OUTPUT ;
    USE SIGNAL ;
    PORT
      LAYER M7 ;
        RECT  53.888 75.931 53.92 76 ;
    END
  END dout[784]
  PIN dout[785]
    DIRECTION OUTPUT ;
    USE SIGNAL ;
    PORT
      LAYER M5 ;
        RECT  57.744 75.916 57.768 76 ;
    END
  END dout[785]
  PIN dout[786]
    DIRECTION OUTPUT ;
    USE SIGNAL ;
    PORT
      LAYER M5 ;
        RECT  56.928 75.916 56.952 76 ;
    END
  END dout[786]
  PIN dout[787]
    DIRECTION OUTPUT ;
    USE SIGNAL ;
    PORT
      LAYER M5 ;
        RECT  48.48 75.916 48.504 76 ;
    END
  END dout[787]
  PIN dout[788]
    DIRECTION OUTPUT ;
    USE SIGNAL ;
    PORT
      LAYER M5 ;
        RECT  58.32 75.916 58.344 76 ;
    END
  END dout[788]
  PIN dout[789]
    DIRECTION OUTPUT ;
    USE SIGNAL ;
    PORT
      LAYER M5 ;
        RECT  45.312 75.916 45.336 76 ;
    END
  END dout[789]
  PIN dout[78]
    DIRECTION OUTPUT ;
    USE SIGNAL ;
    PORT
      LAYER M5 ;
        RECT  73.776 75.916 73.8 76 ;
    END
  END dout[78]
  PIN dout[790]
    DIRECTION OUTPUT ;
    USE SIGNAL ;
    PORT
      LAYER M5 ;
        RECT  46.656 75.916 46.68 76 ;
    END
  END dout[790]
  PIN dout[791]
    DIRECTION OUTPUT ;
    USE SIGNAL ;
    PORT
      LAYER M5 ;
        RECT  55.344 75.916 55.368 76 ;
    END
  END dout[791]
  PIN dout[792]
    DIRECTION OUTPUT ;
    USE SIGNAL ;
    PORT
      LAYER M7 ;
        RECT  49.6 75.931 49.632 76 ;
    END
  END dout[792]
  PIN dout[793]
    DIRECTION OUTPUT ;
    USE SIGNAL ;
    PORT
      LAYER M5 ;
        RECT  58.464 75.916 58.488 76 ;
    END
  END dout[793]
  PIN dout[794]
    DIRECTION OUTPUT ;
    USE SIGNAL ;
    PORT
      LAYER M7 ;
        RECT  50.048 75.931 50.08 76 ;
    END
  END dout[794]
  PIN dout[795]
    DIRECTION OUTPUT ;
    USE SIGNAL ;
    PORT
      LAYER M5 ;
        RECT  45.552 75.916 45.576 76 ;
    END
  END dout[795]
  PIN dout[796]
    DIRECTION OUTPUT ;
    USE SIGNAL ;
    PORT
      LAYER M5 ;
        RECT  43.296 75.916 43.32 76 ;
    END
  END dout[796]
  PIN dout[797]
    DIRECTION OUTPUT ;
    USE SIGNAL ;
    PORT
      LAYER M5 ;
        RECT  49.008 75.916 49.032 76 ;
    END
  END dout[797]
  PIN dout[798]
    DIRECTION OUTPUT ;
    USE SIGNAL ;
    PORT
      LAYER M7 ;
        RECT  53.184 75.931 53.216 76 ;
    END
  END dout[798]
  PIN dout[799]
    DIRECTION OUTPUT ;
    USE SIGNAL ;
    PORT
      LAYER M7 ;
        RECT  23.936 75.931 23.968 76 ;
    END
  END dout[799]
  PIN dout[79]
    DIRECTION OUTPUT ;
    USE SIGNAL ;
    PORT
      LAYER M5 ;
        RECT  69.36 75.916 69.384 76 ;
    END
  END dout[79]
  PIN dout[7]
    DIRECTION OUTPUT ;
    USE SIGNAL ;
    PORT
      LAYER M5 ;
        RECT  33.6 75.916 33.624 76 ;
    END
  END dout[7]
  PIN dout[800]
    DIRECTION OUTPUT ;
    USE SIGNAL ;
    PORT
      LAYER M5 ;
        RECT  31.488 75.916 31.512 76 ;
    END
  END dout[800]
  PIN dout[801]
    DIRECTION OUTPUT ;
    USE SIGNAL ;
    PORT
      LAYER M7 ;
        RECT  51.008 75.931 51.04 76 ;
    END
  END dout[801]
  PIN dout[802]
    DIRECTION OUTPUT ;
    USE SIGNAL ;
    PORT
      LAYER M5 ;
        RECT  58.608 75.916 58.632 76 ;
    END
  END dout[802]
  PIN dout[803]
    DIRECTION OUTPUT ;
    USE SIGNAL ;
    PORT
      LAYER M5 ;
        RECT  59.232 75.916 59.256 76 ;
    END
  END dout[803]
  PIN dout[804]
    DIRECTION OUTPUT ;
    USE SIGNAL ;
    PORT
      LAYER M5 ;
        RECT  58.512 75.916 58.536 76 ;
    END
  END dout[804]
  PIN dout[805]
    DIRECTION OUTPUT ;
    USE SIGNAL ;
    PORT
      LAYER M7 ;
        RECT  53.632 75.931 53.664 76 ;
    END
  END dout[805]
  PIN dout[806]
    DIRECTION OUTPUT ;
    USE SIGNAL ;
    PORT
      LAYER M5 ;
        RECT  55.824 75.916 55.848 76 ;
    END
  END dout[806]
  PIN dout[807]
    DIRECTION OUTPUT ;
    USE SIGNAL ;
    PORT
      LAYER M7 ;
        RECT  39.104 75.931 39.136 76 ;
    END
  END dout[807]
  PIN dout[808]
    DIRECTION OUTPUT ;
    USE SIGNAL ;
    PORT
      LAYER M7 ;
        RECT  23.104 75.931 23.136 76 ;
    END
  END dout[808]
  PIN dout[809]
    DIRECTION OUTPUT ;
    USE SIGNAL ;
    PORT
      LAYER M5 ;
        RECT  57.984 75.916 58.008 76 ;
    END
  END dout[809]
  PIN dout[80]
    DIRECTION OUTPUT ;
    USE SIGNAL ;
    PORT
      LAYER M5 ;
        RECT  65.28 75.916 65.304 76 ;
    END
  END dout[80]
  PIN dout[810]
    DIRECTION OUTPUT ;
    USE SIGNAL ;
    PORT
      LAYER M5 ;
        RECT  59.088 75.916 59.112 76 ;
    END
  END dout[810]
  PIN dout[811]
    DIRECTION OUTPUT ;
    USE SIGNAL ;
    PORT
      LAYER M5 ;
        RECT  57.792 75.916 57.816 76 ;
    END
  END dout[811]
  PIN dout[812]
    DIRECTION OUTPUT ;
    USE SIGNAL ;
    PORT
      LAYER M5 ;
        RECT  56.016 75.916 56.04 76 ;
    END
  END dout[812]
  PIN dout[813]
    DIRECTION OUTPUT ;
    USE SIGNAL ;
    PORT
      LAYER M5 ;
        RECT  58.368 75.916 58.392 76 ;
    END
  END dout[813]
  PIN dout[814]
    DIRECTION OUTPUT ;
    USE SIGNAL ;
    PORT
      LAYER M5 ;
        RECT  57.36 75.916 57.384 76 ;
    END
  END dout[814]
  PIN dout[815]
    DIRECTION OUTPUT ;
    USE SIGNAL ;
    PORT
      LAYER M5 ;
        RECT  59.28 75.916 59.304 76 ;
    END
  END dout[815]
  PIN dout[816]
    DIRECTION OUTPUT ;
    USE SIGNAL ;
    PORT
      LAYER M5 ;
        RECT  19.92 75.916 19.944 76 ;
    END
  END dout[816]
  PIN dout[817]
    DIRECTION OUTPUT ;
    USE SIGNAL ;
    PORT
      LAYER M5 ;
        RECT  9.936 75.916 9.96 76 ;
    END
  END dout[817]
  PIN dout[818]
    DIRECTION OUTPUT ;
    USE SIGNAL ;
    PORT
      LAYER M5 ;
        RECT  27.36 75.916 27.384 76 ;
    END
  END dout[818]
  PIN dout[819]
    DIRECTION OUTPUT ;
    USE SIGNAL ;
    PORT
      LAYER M5 ;
        RECT  16.272 75.916 16.296 76 ;
    END
  END dout[819]
  PIN dout[81]
    DIRECTION OUTPUT ;
    USE SIGNAL ;
    PORT
      LAYER M5 ;
        RECT  66.96 75.916 66.984 76 ;
    END
  END dout[81]
  PIN dout[820]
    DIRECTION OUTPUT ;
    USE SIGNAL ;
    PORT
      LAYER M7 ;
        RECT  13.824 75.931 13.856 76 ;
    END
  END dout[820]
  PIN dout[821]
    DIRECTION OUTPUT ;
    USE SIGNAL ;
    PORT
      LAYER M5 ;
        RECT  57.936 75.916 57.96 76 ;
    END
  END dout[821]
  PIN dout[822]
    DIRECTION OUTPUT ;
    USE SIGNAL ;
    PORT
      LAYER M7 ;
        RECT  23.36 75.931 23.392 76 ;
    END
  END dout[822]
  PIN dout[823]
    DIRECTION OUTPUT ;
    USE SIGNAL ;
    PORT
      LAYER M7 ;
        RECT  22.144 75.931 22.176 76 ;
    END
  END dout[823]
  PIN dout[824]
    DIRECTION OUTPUT ;
    USE SIGNAL ;
    PORT
      LAYER M7 ;
        RECT  24.896 75.931 24.928 76 ;
    END
  END dout[824]
  PIN dout[825]
    DIRECTION OUTPUT ;
    USE SIGNAL ;
    PORT
      LAYER M5 ;
        RECT  34.176 75.916 34.2 76 ;
    END
  END dout[825]
  PIN dout[826]
    DIRECTION OUTPUT ;
    USE SIGNAL ;
    PORT
      LAYER M7 ;
        RECT  53.504 75.931 53.536 76 ;
    END
  END dout[826]
  PIN dout[827]
    DIRECTION OUTPUT ;
    USE SIGNAL ;
    PORT
      LAYER M5 ;
        RECT  55.776 75.916 55.8 76 ;
    END
  END dout[827]
  PIN dout[828]
    DIRECTION OUTPUT ;
    USE SIGNAL ;
    PORT
      LAYER M7 ;
        RECT  52.032 75.931 52.064 76 ;
    END
  END dout[828]
  PIN dout[829]
    DIRECTION OUTPUT ;
    USE SIGNAL ;
    PORT
      LAYER M7 ;
        RECT  39.04 75.931 39.072 76 ;
    END
  END dout[829]
  PIN dout[82]
    DIRECTION OUTPUT ;
    USE SIGNAL ;
    PORT
      LAYER M5 ;
        RECT  70.8 75.916 70.824 76 ;
    END
  END dout[82]
  PIN dout[830]
    DIRECTION OUTPUT ;
    USE SIGNAL ;
    PORT
      LAYER M5 ;
        RECT  56.592 75.916 56.616 76 ;
    END
  END dout[830]
  PIN dout[831]
    DIRECTION OUTPUT ;
    USE SIGNAL ;
    PORT
      LAYER M7 ;
        RECT  22.656 75.931 22.688 76 ;
    END
  END dout[831]
  PIN dout[832]
    DIRECTION OUTPUT ;
    USE SIGNAL ;
    PORT
      LAYER M5 ;
        RECT  101.52 75.916 101.544 76 ;
    END
  END dout[832]
  PIN dout[833]
    DIRECTION OUTPUT ;
    USE SIGNAL ;
    PORT
      LAYER M5 ;
        RECT  101.712 75.916 101.736 76 ;
    END
  END dout[833]
  PIN dout[834]
    DIRECTION OUTPUT ;
    USE SIGNAL ;
    PORT
      LAYER M5 ;
        RECT  107.088 75.916 107.112 76 ;
    END
  END dout[834]
  PIN dout[835]
    DIRECTION OUTPUT ;
    USE SIGNAL ;
    PORT
      LAYER M5 ;
        RECT  100.464 75.916 100.488 76 ;
    END
  END dout[835]
  PIN dout[836]
    DIRECTION OUTPUT ;
    USE SIGNAL ;
    PORT
      LAYER M5 ;
        RECT  101.184 75.916 101.208 76 ;
    END
  END dout[836]
  PIN dout[837]
    DIRECTION OUTPUT ;
    USE SIGNAL ;
    PORT
      LAYER M5 ;
        RECT  102.144 75.916 102.168 76 ;
    END
  END dout[837]
  PIN dout[838]
    DIRECTION OUTPUT ;
    USE SIGNAL ;
    PORT
      LAYER M5 ;
        RECT  97.008 75.916 97.032 76 ;
    END
  END dout[838]
  PIN dout[839]
    DIRECTION OUTPUT ;
    USE SIGNAL ;
    PORT
      LAYER M5 ;
        RECT  103.296 75.916 103.32 76 ;
    END
  END dout[839]
  PIN dout[83]
    DIRECTION OUTPUT ;
    USE SIGNAL ;
    PORT
      LAYER M5 ;
        RECT  73.056 75.916 73.08 76 ;
    END
  END dout[83]
  PIN dout[840]
    DIRECTION OUTPUT ;
    USE SIGNAL ;
    PORT
      LAYER M5 ;
        RECT  101.136 75.916 101.16 76 ;
    END
  END dout[840]
  PIN dout[841]
    DIRECTION OUTPUT ;
    USE SIGNAL ;
    PORT
      LAYER M5 ;
        RECT  100.56 75.916 100.584 76 ;
    END
  END dout[841]
  PIN dout[842]
    DIRECTION OUTPUT ;
    USE SIGNAL ;
    PORT
      LAYER M5 ;
        RECT  106.608 75.916 106.632 76 ;
    END
  END dout[842]
  PIN dout[843]
    DIRECTION OUTPUT ;
    USE SIGNAL ;
    PORT
      LAYER M5 ;
        RECT  106.512 75.916 106.536 76 ;
    END
  END dout[843]
  PIN dout[844]
    DIRECTION OUTPUT ;
    USE SIGNAL ;
    PORT
      LAYER M5 ;
        RECT  100.224 75.916 100.248 76 ;
    END
  END dout[844]
  PIN dout[845]
    DIRECTION OUTPUT ;
    USE SIGNAL ;
    PORT
      LAYER M5 ;
        RECT  103.488 75.916 103.512 76 ;
    END
  END dout[845]
  PIN dout[846]
    DIRECTION OUTPUT ;
    USE SIGNAL ;
    PORT
      LAYER M5 ;
        RECT  99.792 75.916 99.816 76 ;
    END
  END dout[846]
  PIN dout[847]
    DIRECTION OUTPUT ;
    USE SIGNAL ;
    PORT
      LAYER M5 ;
        RECT  107.184 75.916 107.208 76 ;
    END
  END dout[847]
  PIN dout[848]
    DIRECTION OUTPUT ;
    USE SIGNAL ;
    PORT
      LAYER M5 ;
        RECT  107.232 75.916 107.256 76 ;
    END
  END dout[848]
  PIN dout[849]
    DIRECTION OUTPUT ;
    USE SIGNAL ;
    PORT
      LAYER M5 ;
        RECT  104.64 75.916 104.664 76 ;
    END
  END dout[849]
  PIN dout[84]
    DIRECTION OUTPUT ;
    USE SIGNAL ;
    PORT
      LAYER M7 ;
        RECT  76.544 75.931 76.576 76 ;
    END
  END dout[84]
  PIN dout[850]
    DIRECTION OUTPUT ;
    USE SIGNAL ;
    PORT
      LAYER M5 ;
        RECT  104.976 75.916 105 76 ;
    END
  END dout[850]
  PIN dout[851]
    DIRECTION OUTPUT ;
    USE SIGNAL ;
    PORT
      LAYER M5 ;
        RECT  95.28 75.916 95.304 76 ;
    END
  END dout[851]
  PIN dout[852]
    DIRECTION OUTPUT ;
    USE SIGNAL ;
    PORT
      LAYER M5 ;
        RECT  98.304 75.916 98.328 76 ;
    END
  END dout[852]
  PIN dout[853]
    DIRECTION OUTPUT ;
    USE SIGNAL ;
    PORT
      LAYER M5 ;
        RECT  96.672 75.916 96.696 76 ;
    END
  END dout[853]
  PIN dout[854]
    DIRECTION OUTPUT ;
    USE SIGNAL ;
    PORT
      LAYER M5 ;
        RECT  103.008 75.916 103.032 76 ;
    END
  END dout[854]
  PIN dout[855]
    DIRECTION OUTPUT ;
    USE SIGNAL ;
    PORT
      LAYER M7 ;
        RECT  99.776 75.931 99.808 76 ;
    END
  END dout[855]
  PIN dout[856]
    DIRECTION OUTPUT ;
    USE SIGNAL ;
    PORT
      LAYER M5 ;
        RECT  100.416 75.916 100.44 76 ;
    END
  END dout[856]
  PIN dout[857]
    DIRECTION OUTPUT ;
    USE SIGNAL ;
    PORT
      LAYER M5 ;
        RECT  107.04 75.916 107.064 76 ;
    END
  END dout[857]
  PIN dout[858]
    DIRECTION OUTPUT ;
    USE SIGNAL ;
    PORT
      LAYER M5 ;
        RECT  101.616 75.916 101.64 76 ;
    END
  END dout[858]
  PIN dout[859]
    DIRECTION OUTPUT ;
    USE SIGNAL ;
    PORT
      LAYER M5 ;
        RECT  108.768 75.916 108.792 76 ;
    END
  END dout[859]
  PIN dout[85]
    DIRECTION OUTPUT ;
    USE SIGNAL ;
    PORT
      LAYER M7 ;
        RECT  64.448 75.931 64.48 76 ;
    END
  END dout[85]
  PIN dout[860]
    DIRECTION OUTPUT ;
    USE SIGNAL ;
    PORT
      LAYER M5 ;
        RECT  107.328 75.916 107.352 76 ;
    END
  END dout[860]
  PIN dout[861]
    DIRECTION OUTPUT ;
    USE SIGNAL ;
    PORT
      LAYER M7 ;
        RECT  101.888 75.931 101.92 76 ;
    END
  END dout[861]
  PIN dout[862]
    DIRECTION OUTPUT ;
    USE SIGNAL ;
    PORT
      LAYER M7 ;
        RECT  99.584 75.931 99.616 76 ;
    END
  END dout[862]
  PIN dout[863]
    DIRECTION OUTPUT ;
    USE SIGNAL ;
    PORT
      LAYER M7 ;
        RECT  102.592 75.931 102.624 76 ;
    END
  END dout[863]
  PIN dout[864]
    DIRECTION OUTPUT ;
    USE SIGNAL ;
    PORT
      LAYER M5 ;
        RECT  96 75.916 96.024 76 ;
    END
  END dout[864]
  PIN dout[865]
    DIRECTION OUTPUT ;
    USE SIGNAL ;
    PORT
      LAYER M5 ;
        RECT  103.056 75.916 103.08 76 ;
    END
  END dout[865]
  PIN dout[866]
    DIRECTION OUTPUT ;
    USE SIGNAL ;
    PORT
      LAYER M7 ;
        RECT  100.864 75.931 100.896 76 ;
    END
  END dout[866]
  PIN dout[867]
    DIRECTION OUTPUT ;
    USE SIGNAL ;
    PORT
      LAYER M5 ;
        RECT  98.256 75.916 98.28 76 ;
    END
  END dout[867]
  PIN dout[868]
    DIRECTION OUTPUT ;
    USE SIGNAL ;
    PORT
      LAYER M5 ;
        RECT  96.576 75.916 96.6 76 ;
    END
  END dout[868]
  PIN dout[869]
    DIRECTION OUTPUT ;
    USE SIGNAL ;
    PORT
      LAYER M7 ;
        RECT  102.016 75.931 102.048 76 ;
    END
  END dout[869]
  PIN dout[86]
    DIRECTION OUTPUT ;
    USE SIGNAL ;
    PORT
      LAYER M5 ;
        RECT  66.528 75.916 66.552 76 ;
    END
  END dout[86]
  PIN dout[870]
    DIRECTION OUTPUT ;
    USE SIGNAL ;
    PORT
      LAYER M7 ;
        RECT  100.032 75.931 100.064 76 ;
    END
  END dout[870]
  PIN dout[871]
    DIRECTION OUTPUT ;
    USE SIGNAL ;
    PORT
      LAYER M7 ;
        RECT  103.424 75.931 103.456 76 ;
    END
  END dout[871]
  PIN dout[872]
    DIRECTION OUTPUT ;
    USE SIGNAL ;
    PORT
      LAYER M7 ;
        RECT  103.744 75.931 103.776 76 ;
    END
  END dout[872]
  PIN dout[873]
    DIRECTION OUTPUT ;
    USE SIGNAL ;
    PORT
      LAYER M5 ;
        RECT  102.192 75.916 102.216 76 ;
    END
  END dout[873]
  PIN dout[874]
    DIRECTION OUTPUT ;
    USE SIGNAL ;
    PORT
      LAYER M5 ;
        RECT  98.208 75.916 98.232 76 ;
    END
  END dout[874]
  PIN dout[875]
    DIRECTION OUTPUT ;
    USE SIGNAL ;
    PORT
      LAYER M7 ;
        RECT  90.048 75.931 90.08 76 ;
    END
  END dout[875]
  PIN dout[876]
    DIRECTION OUTPUT ;
    USE SIGNAL ;
    PORT
      LAYER M5 ;
        RECT  94.08 75.916 94.104 76 ;
    END
  END dout[876]
  PIN dout[877]
    DIRECTION OUTPUT ;
    USE SIGNAL ;
    PORT
      LAYER M7 ;
        RECT  99.456 75.931 99.488 76 ;
    END
  END dout[877]
  PIN dout[878]
    DIRECTION OUTPUT ;
    USE SIGNAL ;
    PORT
      LAYER M5 ;
        RECT  106.416 75.916 106.44 76 ;
    END
  END dout[878]
  PIN dout[879]
    DIRECTION OUTPUT ;
    USE SIGNAL ;
    PORT
      LAYER M7 ;
        RECT  99.904 75.931 99.936 76 ;
    END
  END dout[879]
  PIN dout[87]
    DIRECTION OUTPUT ;
    USE SIGNAL ;
    PORT
      LAYER M5 ;
        RECT  67.44 75.916 67.464 76 ;
    END
  END dout[87]
  PIN dout[880]
    DIRECTION OUTPUT ;
    USE SIGNAL ;
    PORT
      LAYER M5 ;
        RECT  102.432 75.916 102.456 76 ;
    END
  END dout[880]
  PIN dout[881]
    DIRECTION OUTPUT ;
    USE SIGNAL ;
    PORT
      LAYER M5 ;
        RECT  104.352 75.916 104.376 76 ;
    END
  END dout[881]
  PIN dout[882]
    DIRECTION OUTPUT ;
    USE SIGNAL ;
    PORT
      LAYER M5 ;
        RECT  107.568 75.916 107.592 76 ;
    END
  END dout[882]
  PIN dout[883]
    DIRECTION OUTPUT ;
    USE SIGNAL ;
    PORT
      LAYER M5 ;
        RECT  100.752 75.916 100.776 76 ;
    END
  END dout[883]
  PIN dout[884]
    DIRECTION OUTPUT ;
    USE SIGNAL ;
    PORT
      LAYER M5 ;
        RECT  100.704 75.916 100.728 76 ;
    END
  END dout[884]
  PIN dout[885]
    DIRECTION OUTPUT ;
    USE SIGNAL ;
    PORT
      LAYER M5 ;
        RECT  106.272 75.916 106.296 76 ;
    END
  END dout[885]
  PIN dout[886]
    DIRECTION OUTPUT ;
    USE SIGNAL ;
    PORT
      LAYER M5 ;
        RECT  101.856 75.916 101.88 76 ;
    END
  END dout[886]
  PIN dout[887]
    DIRECTION OUTPUT ;
    USE SIGNAL ;
    PORT
      LAYER M5 ;
        RECT  108.576 75.916 108.6 76 ;
    END
  END dout[887]
  PIN dout[888]
    DIRECTION OUTPUT ;
    USE SIGNAL ;
    PORT
      LAYER M5 ;
        RECT  103.824 75.916 103.848 76 ;
    END
  END dout[888]
  PIN dout[889]
    DIRECTION OUTPUT ;
    USE SIGNAL ;
    PORT
      LAYER M5 ;
        RECT  84.288 75.916 84.312 76 ;
    END
  END dout[889]
  PIN dout[88]
    DIRECTION OUTPUT ;
    USE SIGNAL ;
    PORT
      LAYER M5 ;
        RECT  68.784 75.916 68.808 76 ;
    END
  END dout[88]
  PIN dout[890]
    DIRECTION OUTPUT ;
    USE SIGNAL ;
    PORT
      LAYER M5 ;
        RECT  75.216 75.916 75.24 76 ;
    END
  END dout[890]
  PIN dout[891]
    DIRECTION OUTPUT ;
    USE SIGNAL ;
    PORT
      LAYER M7 ;
        RECT  77.376 75.931 77.408 76 ;
    END
  END dout[891]
  PIN dout[892]
    DIRECTION OUTPUT ;
    USE SIGNAL ;
    PORT
      LAYER M5 ;
        RECT  103.2 75.916 103.224 76 ;
    END
  END dout[892]
  PIN dout[893]
    DIRECTION OUTPUT ;
    USE SIGNAL ;
    PORT
      LAYER M5 ;
        RECT  75.408 75.916 75.432 76 ;
    END
  END dout[893]
  PIN dout[894]
    DIRECTION OUTPUT ;
    USE SIGNAL ;
    PORT
      LAYER M7 ;
        RECT  80.96 75.931 80.992 76 ;
    END
  END dout[894]
  PIN dout[895]
    DIRECTION OUTPUT ;
    USE SIGNAL ;
    PORT
      LAYER M7 ;
        RECT  76.736 75.931 76.768 76 ;
    END
  END dout[895]
  PIN dout[896]
    DIRECTION OUTPUT ;
    USE SIGNAL ;
    PORT
      LAYER M7 ;
        RECT  91.584 75.931 91.616 76 ;
    END
  END dout[896]
  PIN dout[897]
    DIRECTION OUTPUT ;
    USE SIGNAL ;
    PORT
      LAYER M5 ;
        RECT  106.56 75.916 106.584 76 ;
    END
  END dout[897]
  PIN dout[898]
    DIRECTION OUTPUT ;
    USE SIGNAL ;
    PORT
      LAYER M5 ;
        RECT  103.92 75.916 103.944 76 ;
    END
  END dout[898]
  PIN dout[899]
    DIRECTION OUTPUT ;
    USE SIGNAL ;
    PORT
      LAYER M5 ;
        RECT  103.248 75.916 103.272 76 ;
    END
  END dout[899]
  PIN dout[89]
    DIRECTION OUTPUT ;
    USE SIGNAL ;
    PORT
      LAYER M7 ;
        RECT  64.96 75.931 64.992 76 ;
    END
  END dout[89]
  PIN dout[8]
    DIRECTION OUTPUT ;
    USE SIGNAL ;
    PORT
      LAYER M7 ;
        RECT  22.976 75.931 23.008 76 ;
    END
  END dout[8]
  PIN dout[900]
    DIRECTION OUTPUT ;
    USE SIGNAL ;
    PORT
      LAYER M5 ;
        RECT  93.072 75.916 93.096 76 ;
    END
  END dout[900]
  PIN dout[901]
    DIRECTION OUTPUT ;
    USE SIGNAL ;
    PORT
      LAYER M7 ;
        RECT  88.832 75.931 88.864 76 ;
    END
  END dout[901]
  PIN dout[902]
    DIRECTION OUTPUT ;
    USE SIGNAL ;
    PORT
      LAYER M5 ;
        RECT  101.904 75.916 101.928 76 ;
    END
  END dout[902]
  PIN dout[903]
    DIRECTION OUTPUT ;
    USE SIGNAL ;
    PORT
      LAYER M7 ;
        RECT  102.336 75.931 102.368 76 ;
    END
  END dout[903]
  PIN dout[904]
    DIRECTION OUTPUT ;
    USE SIGNAL ;
    PORT
      LAYER M5 ;
        RECT  96.144 75.916 96.168 76 ;
    END
  END dout[904]
  PIN dout[905]
    DIRECTION OUTPUT ;
    USE SIGNAL ;
    PORT
      LAYER M7 ;
        RECT  101.504 75.931 101.536 76 ;
    END
  END dout[905]
  PIN dout[906]
    DIRECTION OUTPUT ;
    USE SIGNAL ;
    PORT
      LAYER M5 ;
        RECT  103.728 75.916 103.752 76 ;
    END
  END dout[906]
  PIN dout[907]
    DIRECTION OUTPUT ;
    USE SIGNAL ;
    PORT
      LAYER M5 ;
        RECT  97.2 75.916 97.224 76 ;
    END
  END dout[907]
  PIN dout[908]
    DIRECTION OUTPUT ;
    USE SIGNAL ;
    PORT
      LAYER M5 ;
        RECT  101.424 75.916 101.448 76 ;
    END
  END dout[908]
  PIN dout[909]
    DIRECTION OUTPUT ;
    USE SIGNAL ;
    PORT
      LAYER M5 ;
        RECT  100.992 75.916 101.016 76 ;
    END
  END dout[909]
  PIN dout[90]
    DIRECTION OUTPUT ;
    USE SIGNAL ;
    PORT
      LAYER M5 ;
        RECT  67.056 75.916 67.08 76 ;
    END
  END dout[90]
  PIN dout[910]
    DIRECTION OUTPUT ;
    USE SIGNAL ;
    PORT
      LAYER M5 ;
        RECT  102.24 75.916 102.264 76 ;
    END
  END dout[910]
  PIN dout[911]
    DIRECTION OUTPUT ;
    USE SIGNAL ;
    PORT
      LAYER M5 ;
        RECT  98.448 75.916 98.472 76 ;
    END
  END dout[911]
  PIN dout[912]
    DIRECTION OUTPUT ;
    USE SIGNAL ;
    PORT
      LAYER M5 ;
        RECT  105.648 75.916 105.672 76 ;
    END
  END dout[912]
  PIN dout[913]
    DIRECTION OUTPUT ;
    USE SIGNAL ;
    PORT
      LAYER M7 ;
        RECT  101.12 75.931 101.152 76 ;
    END
  END dout[913]
  PIN dout[914]
    DIRECTION OUTPUT ;
    USE SIGNAL ;
    PORT
      LAYER M5 ;
        RECT  100.656 75.916 100.68 76 ;
    END
  END dout[914]
  PIN dout[915]
    DIRECTION OUTPUT ;
    USE SIGNAL ;
    PORT
      LAYER M7 ;
        RECT  102.72 75.931 102.752 76 ;
    END
  END dout[915]
  PIN dout[916]
    DIRECTION OUTPUT ;
    USE SIGNAL ;
    PORT
      LAYER M7 ;
        RECT  100.736 75.931 100.768 76 ;
    END
  END dout[916]
  PIN dout[917]
    DIRECTION OUTPUT ;
    USE SIGNAL ;
    PORT
      LAYER M7 ;
        RECT  103.104 75.931 103.136 76 ;
    END
  END dout[917]
  PIN dout[918]
    DIRECTION OUTPUT ;
    USE SIGNAL ;
    PORT
      LAYER M5 ;
        RECT  103.68 75.916 103.704 76 ;
    END
  END dout[918]
  PIN dout[919]
    DIRECTION OUTPUT ;
    USE SIGNAL ;
    PORT
      LAYER M7 ;
        RECT  101.568 75.931 101.6 76 ;
    END
  END dout[919]
  PIN dout[91]
    DIRECTION OUTPUT ;
    USE SIGNAL ;
    PORT
      LAYER M5 ;
        RECT  73.488 75.916 73.512 76 ;
    END
  END dout[91]
  PIN dout[920]
    DIRECTION OUTPUT ;
    USE SIGNAL ;
    PORT
      LAYER M5 ;
        RECT  101.088 75.916 101.112 76 ;
    END
  END dout[920]
  PIN dout[921]
    DIRECTION OUTPUT ;
    USE SIGNAL ;
    PORT
      LAYER M5 ;
        RECT  101.76 75.916 101.784 76 ;
    END
  END dout[921]
  PIN dout[922]
    DIRECTION OUTPUT ;
    USE SIGNAL ;
    PORT
      LAYER M5 ;
        RECT  107.712 75.916 107.736 76 ;
    END
  END dout[922]
  PIN dout[923]
    DIRECTION OUTPUT ;
    USE SIGNAL ;
    PORT
      LAYER M5 ;
        RECT  101.232 75.916 101.256 76 ;
    END
  END dout[923]
  PIN dout[924]
    DIRECTION OUTPUT ;
    USE SIGNAL ;
    PORT
      LAYER M5 ;
        RECT  104.496 75.916 104.52 76 ;
    END
  END dout[924]
  PIN dout[925]
    DIRECTION OUTPUT ;
    USE SIGNAL ;
    PORT
      LAYER M5 ;
        RECT  108.096 75.916 108.12 76 ;
    END
  END dout[925]
  PIN dout[926]
    DIRECTION OUTPUT ;
    USE SIGNAL ;
    PORT
      LAYER M5 ;
        RECT  106.992 75.916 107.016 76 ;
    END
  END dout[926]
  PIN dout[927]
    DIRECTION OUTPUT ;
    USE SIGNAL ;
    PORT
      LAYER M5 ;
        RECT  100.368 75.916 100.392 76 ;
    END
  END dout[927]
  PIN dout[928]
    DIRECTION OUTPUT ;
    USE SIGNAL ;
    PORT
      LAYER M5 ;
        RECT  103.776 75.916 103.8 76 ;
    END
  END dout[928]
  PIN dout[929]
    DIRECTION OUTPUT ;
    USE SIGNAL ;
    PORT
      LAYER M5 ;
        RECT  108 75.916 108.024 76 ;
    END
  END dout[929]
  PIN dout[92]
    DIRECTION OUTPUT ;
    USE SIGNAL ;
    PORT
      LAYER M7 ;
        RECT  62.72 75.931 62.752 76 ;
    END
  END dout[92]
  PIN dout[930]
    DIRECTION OUTPUT ;
    USE SIGNAL ;
    PORT
      LAYER M5 ;
        RECT  108.336 75.916 108.36 76 ;
    END
  END dout[930]
  PIN dout[931]
    DIRECTION OUTPUT ;
    USE SIGNAL ;
    PORT
      LAYER M5 ;
        RECT  106.368 75.916 106.392 76 ;
    END
  END dout[931]
  PIN dout[932]
    DIRECTION OUTPUT ;
    USE SIGNAL ;
    PORT
      LAYER M5 ;
        RECT  104.592 75.916 104.616 76 ;
    END
  END dout[932]
  PIN dout[933]
    DIRECTION OUTPUT ;
    USE SIGNAL ;
    PORT
      LAYER M5 ;
        RECT  106.32 75.916 106.344 76 ;
    END
  END dout[933]
  PIN dout[934]
    DIRECTION OUTPUT ;
    USE SIGNAL ;
    PORT
      LAYER M5 ;
        RECT  103.632 75.916 103.656 76 ;
    END
  END dout[934]
  PIN dout[935]
    DIRECTION OUTPUT ;
    USE SIGNAL ;
    PORT
      LAYER M5 ;
        RECT  100.176 75.916 100.2 76 ;
    END
  END dout[935]
  PIN dout[936]
    DIRECTION OUTPUT ;
    USE SIGNAL ;
    PORT
      LAYER M5 ;
        RECT  105.84 75.916 105.864 76 ;
    END
  END dout[936]
  PIN dout[937]
    DIRECTION OUTPUT ;
    USE SIGNAL ;
    PORT
      LAYER M5 ;
        RECT  102.288 75.916 102.312 76 ;
    END
  END dout[937]
  PIN dout[938]
    DIRECTION OUTPUT ;
    USE SIGNAL ;
    PORT
      LAYER M5 ;
        RECT  102.048 75.916 102.072 76 ;
    END
  END dout[938]
  PIN dout[939]
    DIRECTION OUTPUT ;
    USE SIGNAL ;
    PORT
      LAYER M5 ;
        RECT  107.136 75.916 107.16 76 ;
    END
  END dout[939]
  PIN dout[93]
    DIRECTION OUTPUT ;
    USE SIGNAL ;
    PORT
      LAYER M5 ;
        RECT  71.808 75.916 71.832 76 ;
    END
  END dout[93]
  PIN dout[940]
    DIRECTION OUTPUT ;
    USE SIGNAL ;
    PORT
      LAYER M5 ;
        RECT  105.072 75.916 105.096 76 ;
    END
  END dout[940]
  PIN dout[941]
    DIRECTION OUTPUT ;
    USE SIGNAL ;
    PORT
      LAYER M5 ;
        RECT  107.664 75.916 107.688 76 ;
    END
  END dout[941]
  PIN dout[942]
    DIRECTION OUTPUT ;
    USE SIGNAL ;
    PORT
      LAYER M5 ;
        RECT  107.472 75.916 107.496 76 ;
    END
  END dout[942]
  PIN dout[943]
    DIRECTION OUTPUT ;
    USE SIGNAL ;
    PORT
      LAYER M5 ;
        RECT  107.856 75.916 107.88 76 ;
    END
  END dout[943]
  PIN dout[944]
    DIRECTION OUTPUT ;
    USE SIGNAL ;
    PORT
      LAYER M5 ;
        RECT  102.912 75.916 102.936 76 ;
    END
  END dout[944]
  PIN dout[945]
    DIRECTION OUTPUT ;
    USE SIGNAL ;
    PORT
      LAYER M7 ;
        RECT  103.168 75.931 103.2 76 ;
    END
  END dout[945]
  PIN dout[946]
    DIRECTION OUTPUT ;
    USE SIGNAL ;
    PORT
      LAYER M5 ;
        RECT  99.84 75.916 99.864 76 ;
    END
  END dout[946]
  PIN dout[947]
    DIRECTION OUTPUT ;
    USE SIGNAL ;
    PORT
      LAYER M5 ;
        RECT  102.624 75.916 102.648 76 ;
    END
  END dout[947]
  PIN dout[948]
    DIRECTION OUTPUT ;
    USE SIGNAL ;
    PORT
      LAYER M5 ;
        RECT  104.928 75.916 104.952 76 ;
    END
  END dout[948]
  PIN dout[949]
    DIRECTION OUTPUT ;
    USE SIGNAL ;
    PORT
      LAYER M5 ;
        RECT  107.76 75.916 107.784 76 ;
    END
  END dout[949]
  PIN dout[94]
    DIRECTION OUTPUT ;
    USE SIGNAL ;
    PORT
      LAYER M5 ;
        RECT  59.04 75.916 59.064 76 ;
    END
  END dout[94]
  PIN dout[950]
    DIRECTION OUTPUT ;
    USE SIGNAL ;
    PORT
      LAYER M5 ;
        RECT  106.176 75.916 106.2 76 ;
    END
  END dout[950]
  PIN dout[951]
    DIRECTION OUTPUT ;
    USE SIGNAL ;
    PORT
      LAYER M5 ;
        RECT  100.608 75.916 100.632 76 ;
    END
  END dout[951]
  PIN dout[952]
    DIRECTION OUTPUT ;
    USE SIGNAL ;
    PORT
      LAYER M5 ;
        RECT  100.944 75.916 100.968 76 ;
    END
  END dout[952]
  PIN dout[953]
    DIRECTION OUTPUT ;
    USE SIGNAL ;
    PORT
      LAYER M7 ;
        RECT  64.704 75.931 64.736 76 ;
    END
  END dout[953]
  PIN dout[954]
    DIRECTION OUTPUT ;
    USE SIGNAL ;
    PORT
      LAYER M7 ;
        RECT  62.912 75.931 62.944 76 ;
    END
  END dout[954]
  PIN dout[955]
    DIRECTION OUTPUT ;
    USE SIGNAL ;
    PORT
      LAYER M5 ;
        RECT  71.52 75.916 71.544 76 ;
    END
  END dout[955]
  PIN dout[956]
    DIRECTION OUTPUT ;
    USE SIGNAL ;
    PORT
      LAYER M5 ;
        RECT  102.864 75.916 102.888 76 ;
    END
  END dout[956]
  PIN dout[957]
    DIRECTION OUTPUT ;
    USE SIGNAL ;
    PORT
      LAYER M5 ;
        RECT  67.392 75.916 67.416 76 ;
    END
  END dout[957]
  PIN dout[958]
    DIRECTION OUTPUT ;
    USE SIGNAL ;
    PORT
      LAYER M5 ;
        RECT  67.008 75.916 67.032 76 ;
    END
  END dout[958]
  PIN dout[959]
    DIRECTION OUTPUT ;
    USE SIGNAL ;
    PORT
      LAYER M5 ;
        RECT  67.2 75.916 67.224 76 ;
    END
  END dout[959]
  PIN dout[95]
    DIRECTION OUTPUT ;
    USE SIGNAL ;
    PORT
      LAYER M5 ;
        RECT  70.272 75.916 70.296 76 ;
    END
  END dout[95]
  PIN dout[960]
    DIRECTION OUTPUT ;
    USE SIGNAL ;
    PORT
      LAYER M7 ;
        RECT  91.136 75.931 91.168 76 ;
    END
  END dout[960]
  PIN dout[961]
    DIRECTION OUTPUT ;
    USE SIGNAL ;
    PORT
      LAYER M5 ;
        RECT  94.128 75.916 94.152 76 ;
    END
  END dout[961]
  PIN dout[962]
    DIRECTION OUTPUT ;
    USE SIGNAL ;
    PORT
      LAYER M5 ;
        RECT  105.168 75.916 105.192 76 ;
    END
  END dout[962]
  PIN dout[963]
    DIRECTION OUTPUT ;
    USE SIGNAL ;
    PORT
      LAYER M5 ;
        RECT  95.184 75.916 95.208 76 ;
    END
  END dout[963]
  PIN dout[964]
    DIRECTION OUTPUT ;
    USE SIGNAL ;
    PORT
      LAYER M5 ;
        RECT  109.152 75.916 109.176 76 ;
    END
  END dout[964]
  PIN dout[965]
    DIRECTION OUTPUT ;
    USE SIGNAL ;
    PORT
      LAYER M5 ;
        RECT  105.456 75.916 105.48 76 ;
    END
  END dout[965]
  PIN dout[966]
    DIRECTION OUTPUT ;
    USE SIGNAL ;
    PORT
      LAYER M5 ;
        RECT  94.32 75.916 94.344 76 ;
    END
  END dout[966]
  PIN dout[967]
    DIRECTION OUTPUT ;
    USE SIGNAL ;
    PORT
      LAYER M5 ;
        RECT  106.896 75.916 106.92 76 ;
    END
  END dout[967]
  PIN dout[968]
    DIRECTION OUTPUT ;
    USE SIGNAL ;
    PORT
      LAYER M5 ;
        RECT  105.696 75.916 105.72 76 ;
    END
  END dout[968]
  PIN dout[969]
    DIRECTION OUTPUT ;
    USE SIGNAL ;
    PORT
      LAYER M7 ;
        RECT  100.48 75.931 100.512 76 ;
    END
  END dout[969]
  PIN dout[96]
    DIRECTION OUTPUT ;
    USE SIGNAL ;
    PORT
      LAYER M7 ;
        RECT  77.568 75.931 77.6 76 ;
    END
  END dout[96]
  PIN dout[970]
    DIRECTION OUTPUT ;
    USE SIGNAL ;
    PORT
      LAYER M5 ;
        RECT  102.096 75.916 102.12 76 ;
    END
  END dout[970]
  PIN dout[971]
    DIRECTION OUTPUT ;
    USE SIGNAL ;
    PORT
      LAYER M5 ;
        RECT  104.88 75.916 104.904 76 ;
    END
  END dout[971]
  PIN dout[972]
    DIRECTION OUTPUT ;
    USE SIGNAL ;
    PORT
      LAYER M5 ;
        RECT  103.536 75.916 103.56 76 ;
    END
  END dout[972]
  PIN dout[973]
    DIRECTION OUTPUT ;
    USE SIGNAL ;
    PORT
      LAYER M7 ;
        RECT  107.008 75.931 107.04 76 ;
    END
  END dout[973]
  PIN dout[974]
    DIRECTION OUTPUT ;
    USE SIGNAL ;
    PORT
      LAYER M7 ;
        RECT  106.88 75.931 106.912 76 ;
    END
  END dout[974]
  PIN dout[975]
    DIRECTION OUTPUT ;
    USE SIGNAL ;
    PORT
      LAYER M7 ;
        RECT  108.352 75.931 108.384 76 ;
    END
  END dout[975]
  PIN dout[976]
    DIRECTION OUTPUT ;
    USE SIGNAL ;
    PORT
      LAYER M7 ;
        RECT  105.536 75.931 105.568 76 ;
    END
  END dout[976]
  PIN dout[977]
    DIRECTION OUTPUT ;
    USE SIGNAL ;
    PORT
      LAYER M7 ;
        RECT  106.816 75.931 106.848 76 ;
    END
  END dout[977]
  PIN dout[978]
    DIRECTION OUTPUT ;
    USE SIGNAL ;
    PORT
      LAYER M7 ;
        RECT  107.584 75.931 107.616 76 ;
    END
  END dout[978]
  PIN dout[979]
    DIRECTION OUTPUT ;
    USE SIGNAL ;
    PORT
      LAYER M7 ;
        RECT  105.984 75.931 106.016 76 ;
    END
  END dout[979]
  PIN dout[97]
    DIRECTION OUTPUT ;
    USE SIGNAL ;
    PORT
      LAYER M7 ;
        RECT  63.296 75.931 63.328 76 ;
    END
  END dout[97]
  PIN dout[980]
    DIRECTION OUTPUT ;
    USE SIGNAL ;
    PORT
      LAYER M7 ;
        RECT  91.84 75.931 91.872 76 ;
    END
  END dout[980]
  PIN dout[981]
    DIRECTION OUTPUT ;
    USE SIGNAL ;
    PORT
      LAYER M5 ;
        RECT  87.36 75.916 87.384 76 ;
    END
  END dout[981]
  PIN dout[982]
    DIRECTION OUTPUT ;
    USE SIGNAL ;
    PORT
      LAYER M7 ;
        RECT  103.36 75.931 103.392 76 ;
    END
  END dout[982]
  PIN dout[983]
    DIRECTION OUTPUT ;
    USE SIGNAL ;
    PORT
      LAYER M7 ;
        RECT  106.048 75.931 106.08 76 ;
    END
  END dout[983]
  PIN dout[984]
    DIRECTION OUTPUT ;
    USE SIGNAL ;
    PORT
      LAYER M7 ;
        RECT  105.024 75.931 105.056 76 ;
    END
  END dout[984]
  PIN dout[985]
    DIRECTION OUTPUT ;
    USE SIGNAL ;
    PORT
      LAYER M7 ;
        RECT  102.784 75.931 102.816 76 ;
    END
  END dout[985]
  PIN dout[986]
    DIRECTION OUTPUT ;
    USE SIGNAL ;
    PORT
      LAYER M5 ;
        RECT  85.392 75.916 85.416 76 ;
    END
  END dout[986]
  PIN dout[987]
    DIRECTION OUTPUT ;
    USE SIGNAL ;
    PORT
      LAYER M7 ;
        RECT  104.768 75.931 104.8 76 ;
    END
  END dout[987]
  PIN dout[988]
    DIRECTION OUTPUT ;
    USE SIGNAL ;
    PORT
      LAYER M7 ;
        RECT  103.616 75.931 103.648 76 ;
    END
  END dout[988]
  PIN dout[989]
    DIRECTION OUTPUT ;
    USE SIGNAL ;
    PORT
      LAYER M5 ;
        RECT  97.92 75.916 97.944 76 ;
    END
  END dout[989]
  PIN dout[98]
    DIRECTION OUTPUT ;
    USE SIGNAL ;
    PORT
      LAYER M5 ;
        RECT  59.328 75.916 59.352 76 ;
    END
  END dout[98]
  PIN dout[990]
    DIRECTION OUTPUT ;
    USE SIGNAL ;
    PORT
      LAYER M5 ;
        RECT  86.448 75.916 86.472 76 ;
    END
  END dout[990]
  PIN dout[991]
    DIRECTION OUTPUT ;
    USE SIGNAL ;
    PORT
      LAYER M7 ;
        RECT  100.288 75.931 100.32 76 ;
    END
  END dout[991]
  PIN dout[992]
    DIRECTION OUTPUT ;
    USE SIGNAL ;
    PORT
      LAYER M5 ;
        RECT  92.352 75.916 92.376 76 ;
    END
  END dout[992]
  PIN dout[993]
    DIRECTION OUTPUT ;
    USE SIGNAL ;
    PORT
      LAYER M7 ;
        RECT  89.152 75.931 89.184 76 ;
    END
  END dout[993]
  PIN dout[994]
    DIRECTION OUTPUT ;
    USE SIGNAL ;
    PORT
      LAYER M7 ;
        RECT  89.536 75.931 89.568 76 ;
    END
  END dout[994]
  PIN dout[995]
    DIRECTION OUTPUT ;
    USE SIGNAL ;
    PORT
      LAYER M7 ;
        RECT  107.648 75.931 107.68 76 ;
    END
  END dout[995]
  PIN dout[996]
    DIRECTION OUTPUT ;
    USE SIGNAL ;
    PORT
      LAYER M7 ;
        RECT  101.696 75.931 101.728 76 ;
    END
  END dout[996]
  PIN dout[997]
    DIRECTION OUTPUT ;
    USE SIGNAL ;
    PORT
      LAYER M5 ;
        RECT  92.784 75.916 92.808 76 ;
    END
  END dout[997]
  PIN dout[998]
    DIRECTION OUTPUT ;
    USE SIGNAL ;
    PORT
      LAYER M5 ;
        RECT  74.496 75.916 74.52 76 ;
    END
  END dout[998]
  PIN dout[999]
    DIRECTION OUTPUT ;
    USE SIGNAL ;
    PORT
      LAYER M7 ;
        RECT  102.208 75.931 102.24 76 ;
    END
  END dout[999]
  PIN dout[99]
    DIRECTION OUTPUT ;
    USE SIGNAL ;
    PORT
      LAYER M7 ;
        RECT  50.624 75.931 50.656 76 ;
    END
  END dout[99]
  PIN dout[9]
    DIRECTION OUTPUT ;
    USE SIGNAL ;
    PORT
      LAYER M5 ;
        RECT  20.304 75.916 20.328 76 ;
    END
  END dout[9]
  PIN go_check
    DIRECTION INPUT ;
    USE SIGNAL ;
    PORT
      LAYER M5 ;
        RECT  30.048 0 30.072 0.084 ;
    END
  END go_check
  PIN go_commit
    DIRECTION INPUT ;
    USE SIGNAL ;
    PORT
      LAYER M5 ;
        RECT  30.432 0 30.456 0.084 ;
    END
  END go_commit
  PIN go_repair
    DIRECTION INPUT ;
    USE SIGNAL ;
    PORT
      LAYER M5 ;
        RECT  32.352 0 32.376 0.084 ;
    END
  END go_repair
  PIN go_sel
    DIRECTION INPUT ;
    USE SIGNAL ;
    PORT
      LAYER M5 ;
        RECT  30.624 0 30.648 0.084 ;
    END
  END go_sel
  PIN gr
    DIRECTION INPUT ;
    USE SIGNAL ;
    PORT
      LAYER M5 ;
        RECT  19.92 0 19.944 0.084 ;
    END
  END gr
  PIN grc_o[0]
    DIRECTION OUTPUT ;
    USE SIGNAL ;
    PORT
      LAYER M5 ;
        RECT  27.888 0 27.912 0.084 ;
    END
  END grc_o[0]
  PIN grc_o[1]
    DIRECTION OUTPUT ;
    USE SIGNAL ;
    PORT
      LAYER M5 ;
        RECT  36.336 0 36.36 0.084 ;
    END
  END grc_o[1]
  PIN grc_o[2]
    DIRECTION OUTPUT ;
    USE SIGNAL ;
    PORT
      LAYER M5 ;
        RECT  37.488 0 37.512 0.084 ;
    END
  END grc_o[2]
  PIN grc_o[3]
    DIRECTION OUTPUT ;
    USE SIGNAL ;
    PORT
      LAYER M7 ;
        RECT  7.296 0 7.328 0.069 ;
    END
  END grc_o[3]
  PIN grc_o[4]
    DIRECTION OUTPUT ;
    USE SIGNAL ;
    PORT
      LAYER M5 ;
        RECT  15.12 0 15.144 0.084 ;
    END
  END grc_o[4]
  PIN grc_o[5]
    DIRECTION OUTPUT ;
    USE SIGNAL ;
    PORT
      LAYER M5 ;
        RECT  68.064 0 68.088 0.084 ;
    END
  END grc_o[5]
  PIN grc_o[6]
    DIRECTION OUTPUT ;
    USE SIGNAL ;
    PORT
      LAYER M5 ;
        RECT  74.784 0 74.808 0.084 ;
    END
  END grc_o[6]
  PIN grc_o[7]
    DIRECTION OUTPUT ;
    USE SIGNAL ;
    PORT
      LAYER M5 ;
        RECT  62.736 0 62.76 0.084 ;
    END
  END grc_o[7]
  PIN ph4[0]
    DIRECTION INPUT ;
    USE SIGNAL ;
    PORT
      LAYER M5 ;
        RECT  34.032 0 34.056 0.084 ;
    END
  END ph4[0]
  PIN ph4[1]
    DIRECTION INPUT ;
    USE SIGNAL ;
    PORT
      LAYER M5 ;
        RECT  33.936 0 33.96 0.084 ;
    END
  END ph4[1]
  PIN ph4[2]
    DIRECTION INPUT ;
    USE SIGNAL ;
    PORT
      LAYER M5 ;
        RECT  34.128 0 34.152 0.084 ;
    END
  END ph4[2]
  PIN ph4[3]
    DIRECTION INPUT ;
    USE SIGNAL ;
    PORT
      LAYER M7 ;
        RECT  31.936 0 31.968 0.069 ;
    END
  END ph4[3]
  PIN rst_e
    DIRECTION INPUT ;
    USE SIGNAL ;
    PORT
      LAYER M5 ;
        RECT  19.968 0 19.992 0.084 ;
    END
  END rst_e
  PIN rst_p
    DIRECTION INPUT ;
    USE SIGNAL ;
    PORT
      LAYER M5 ;
        RECT  30 0 30.024 0.084 ;
    END
  END rst_p
  PIN v_bad
    DIRECTION OUTPUT ;
    USE SIGNAL ;
    PORT
      LAYER M5 ;
        RECT  54.576 0 54.6 0.084 ;
    END
  END v_bad
  PIN v_cbad
    DIRECTION OUTPUT ;
    USE SIGNAL ;
    PORT
      LAYER M5 ;
        RECT  38.112 0 38.136 0.084 ;
    END
  END v_cbad
  PIN v_ce
    DIRECTION OUTPUT ;
    USE SIGNAL ;
    PORT
      LAYER M7 ;
        RECT  46.4 0 46.432 0.069 ;
    END
  END v_ce
  PIN v_clean
    DIRECTION OUTPUT ;
    USE SIGNAL ;
    PORT
      LAYER M5 ;
        RECT  41.568 0 41.592 0.084 ;
    END
  END v_clean
  PIN v_same
    DIRECTION OUTPUT ;
    USE SIGNAL ;
    PORT
      LAYER M5 ;
        RECT  37.872 0 37.896 0.084 ;
    END
  END v_same
  PIN v_ue
    DIRECTION OUTPUT ;
    USE SIGNAL ;
    PORT
      LAYER M5 ;
        RECT  50.928 0 50.952 0.084 ;
    END
  END v_ue
  PIN VDD
    DIRECTION INOUT ;
    USE POWER ;
    PORT
      LAYER M6 ;
        RECT  1.08 72.033 108.918 72.321 ;
        RECT  1.08 66.633 108.918 66.921 ;
        RECT  1.08 61.233 108.918 61.521 ;
        RECT  1.08 55.833 108.918 56.121 ;
        RECT  1.08 50.433 108.918 50.721 ;
        RECT  1.08 45.033 108.918 45.321 ;
        RECT  1.08 39.633 108.918 39.921 ;
        RECT  1.08 34.233 108.918 34.521 ;
        RECT  1.08 28.833 108.918 29.121 ;
        RECT  1.08 23.433 108.918 23.721 ;
        RECT  1.08 18.033 108.918 18.321 ;
        RECT  1.08 12.633 108.918 12.921 ;
        RECT  1.08 7.233 108.918 7.521 ;
        RECT  1.08 1.833 108.918 2.121 ;
    END
  END VDD
  PIN VSS
    DIRECTION INOUT ;
    USE GROUND ;
    PORT
      LAYER M6 ;
        RECT  1.08 71.649 108.918 71.937 ;
        RECT  1.08 66.249 108.918 66.537 ;
        RECT  1.08 60.849 108.918 61.137 ;
        RECT  1.08 55.449 108.918 55.737 ;
        RECT  1.08 50.049 108.918 50.337 ;
        RECT  1.08 44.649 108.918 44.937 ;
        RECT  1.08 39.249 108.918 39.537 ;
        RECT  1.08 33.849 108.918 34.137 ;
        RECT  1.08 28.449 108.918 28.737 ;
        RECT  1.08 23.049 108.918 23.337 ;
        RECT  1.08 17.649 108.918 17.937 ;
        RECT  1.08 12.249 108.918 12.537 ;
        RECT  1.08 6.849 108.918 7.137 ;
        RECT  1.08 1.449 108.918 1.737 ;
    END
  END VSS
  OBS
    LAYER RVTN ;
     RECT  0.709 0 109.283 76 ;
    LAYER RVTP ;
     RECT  0.709 0 109.283 76 ;
    LAYER M1 ;
     RECT  0.709 0 109.283 76 ;
    LAYER M2 ;
     RECT  0.709 0 109.283 76 ;
    LAYER M3 ;
     RECT  0.709 0 109.283 76 ;
    LAYER M4 ;
     RECT  0.709 0 109.283 76 ;
    LAYER M5 ;
     RECT  0.709 0 109.283 76 ;
    LAYER M6 ;
     RECT  0.709 0 109.283 76 ;
    LAYER M7 ;
     RECT  0.709 0 109.283 76 ;
  END
END ot_hbm_w2_stn_slice8
END LIBRARY
